VERSION 5.7 ;
  NOWIREEXTENSIONATPIN ON ;
  DIVIDERCHAR "/" ;
  BUSBITCHARS "[]" ;
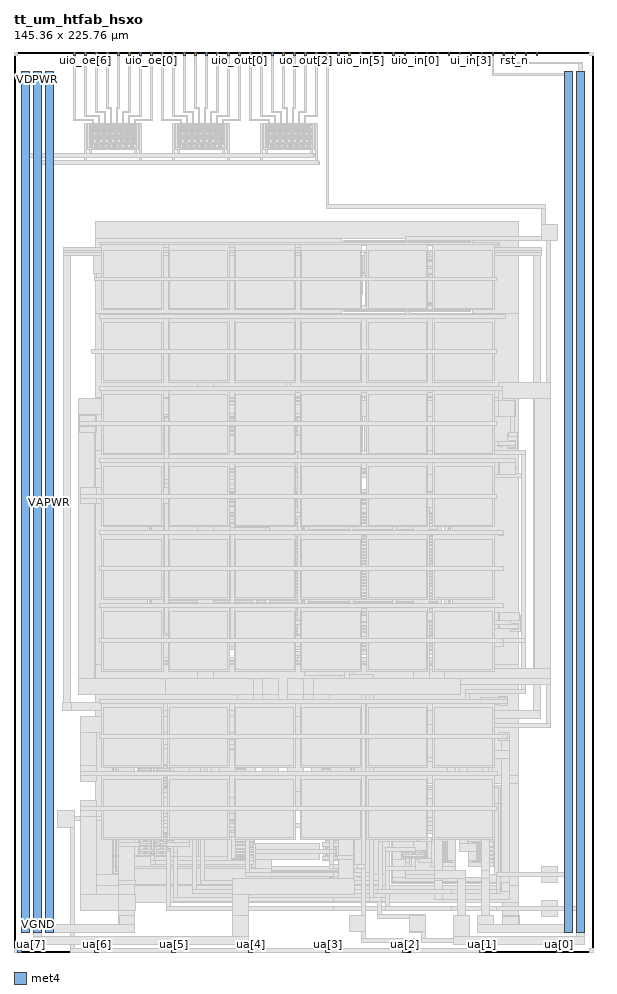
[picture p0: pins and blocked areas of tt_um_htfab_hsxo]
MACRO tt_um_htfab_hsxo
  CLASS BLOCK ;
  FOREIGN tt_um_htfab_hsxo ;
  ORIGIN 0.000 0.000 ;
  SIZE 145.360 BY 225.760 ;
  PIN clk
    DIRECTION INPUT ;
    USE SIGNAL ;
    PORT
      LAYER met4 ;
        RECT 128.190 224.760 128.490 225.760 ;
    END
  END clk
  PIN ena
    DIRECTION INPUT ;
    USE SIGNAL ;
    PORT
      LAYER met4 ;
        RECT 130.950 224.760 131.250 225.760 ;
    END
  END ena
  PIN rst_n
    DIRECTION INPUT ;
    USE SIGNAL ;
    PORT
      LAYER met4 ;
        RECT 125.430 224.760 125.730 225.760 ;
    END
  END rst_n
  PIN ua[0]
    DIRECTION INOUT ;
    USE SIGNAL ;
    ANTENNADIFFAREA 157.759995 ;
    PORT
      LAYER met4 ;
        RECT 136.170 0.000 137.070 1.000 ;
    END
  END ua[0]
  PIN ua[1]
    DIRECTION INOUT ;
    USE SIGNAL ;
    ANTENNAGATEAREA 18.202499 ;
    ANTENNADIFFAREA 0.405000 ;
    PORT
      LAYER met4 ;
        RECT 116.850 0.000 117.750 1.000 ;
    END
  END ua[1]
  PIN ua[2]
    DIRECTION INOUT ;
    USE SIGNAL ;
    ANTENNADIFFAREA 5.800000 ;
    PORT
      LAYER met4 ;
        RECT 97.530 0.000 98.430 1.000 ;
    END
  END ua[2]
  PIN ua[3]
    DIRECTION INOUT ;
    USE SIGNAL ;
    PORT
      LAYER met4 ;
        RECT 78.210 0.000 79.110 1.000 ;
    END
  END ua[3]
  PIN ua[4]
    DIRECTION INOUT ;
    USE SIGNAL ;
    PORT
      LAYER met4 ;
        RECT 58.890 0.000 59.790 1.000 ;
    END
  END ua[4]
  PIN ua[5]
    DIRECTION INOUT ;
    USE SIGNAL ;
    PORT
      LAYER met4 ;
        RECT 39.570 0.000 40.470 1.000 ;
    END
  END ua[5]
  PIN ua[6]
    DIRECTION INOUT ;
    USE SIGNAL ;
    PORT
      LAYER met4 ;
        RECT 20.250 0.000 21.150 1.000 ;
    END
  END ua[6]
  PIN ua[7]
    DIRECTION INOUT ;
    USE SIGNAL ;
    PORT
      LAYER met4 ;
        RECT 0.930 0.000 1.830 1.000 ;
    END
  END ua[7]
  PIN ui_in[0]
    DIRECTION INPUT ;
    USE SIGNAL ;
    ANTENNAGATEAREA 0.800000 ;
    PORT
      LAYER met4 ;
        RECT 122.670 224.760 122.970 225.760 ;
    END
  END ui_in[0]
  PIN ui_in[1]
    DIRECTION INPUT ;
    USE SIGNAL ;
    ANTENNAGATEAREA 10.400000 ;
    PORT
      LAYER met4 ;
        RECT 119.910 224.760 120.210 225.760 ;
    END
  END ui_in[1]
  PIN ui_in[2]
    DIRECTION INPUT ;
    USE SIGNAL ;
    PORT
      LAYER met4 ;
        RECT 117.150 224.760 117.450 225.760 ;
    END
  END ui_in[2]
  PIN ui_in[3]
    DIRECTION INPUT ;
    USE SIGNAL ;
    PORT
      LAYER met4 ;
        RECT 114.390 224.760 114.690 225.760 ;
    END
  END ui_in[3]
  PIN ui_in[4]
    DIRECTION INPUT ;
    USE SIGNAL ;
    PORT
      LAYER met4 ;
        RECT 111.630 224.760 111.930 225.760 ;
    END
  END ui_in[4]
  PIN ui_in[5]
    DIRECTION INPUT ;
    USE SIGNAL ;
    PORT
      LAYER met4 ;
        RECT 108.870 224.760 109.170 225.760 ;
    END
  END ui_in[5]
  PIN ui_in[6]
    DIRECTION INPUT ;
    USE SIGNAL ;
    PORT
      LAYER met4 ;
        RECT 106.110 224.760 106.410 225.760 ;
    END
  END ui_in[6]
  PIN ui_in[7]
    DIRECTION INPUT ;
    USE SIGNAL ;
    PORT
      LAYER met4 ;
        RECT 103.350 224.760 103.650 225.760 ;
    END
  END ui_in[7]
  PIN uio_in[0]
    DIRECTION INPUT ;
    USE SIGNAL ;
    PORT
      LAYER met4 ;
        RECT 100.590 224.760 100.890 225.760 ;
    END
  END uio_in[0]
  PIN uio_in[1]
    DIRECTION INPUT ;
    USE SIGNAL ;
    PORT
      LAYER met4 ;
        RECT 97.830 224.760 98.130 225.760 ;
    END
  END uio_in[1]
  PIN uio_in[2]
    DIRECTION INPUT ;
    USE SIGNAL ;
    PORT
      LAYER met4 ;
        RECT 95.070 224.760 95.370 225.760 ;
    END
  END uio_in[2]
  PIN uio_in[3]
    DIRECTION INPUT ;
    USE SIGNAL ;
    PORT
      LAYER met4 ;
        RECT 92.310 224.760 92.610 225.760 ;
    END
  END uio_in[3]
  PIN uio_in[4]
    DIRECTION INPUT ;
    USE SIGNAL ;
    PORT
      LAYER met4 ;
        RECT 89.550 224.760 89.850 225.760 ;
    END
  END uio_in[4]
  PIN uio_in[5]
    DIRECTION INPUT ;
    USE SIGNAL ;
    PORT
      LAYER met4 ;
        RECT 86.790 224.760 87.090 225.760 ;
    END
  END uio_in[5]
  PIN uio_in[6]
    DIRECTION INPUT ;
    USE SIGNAL ;
    PORT
      LAYER met4 ;
        RECT 84.030 224.760 84.330 225.760 ;
    END
  END uio_in[6]
  PIN uio_in[7]
    DIRECTION INPUT ;
    USE SIGNAL ;
    PORT
      LAYER met4 ;
        RECT 81.270 224.760 81.570 225.760 ;
    END
  END uio_in[7]
  PIN uio_oe[0]
    DIRECTION OUTPUT ;
    USE SIGNAL ;
    ANTENNADIFFAREA 0.227500 ;
    PORT
      LAYER met4 ;
        RECT 34.350 224.760 34.650 225.760 ;
    END
  END uio_oe[0]
  PIN uio_oe[1]
    DIRECTION OUTPUT ;
    USE SIGNAL ;
    ANTENNADIFFAREA 0.227500 ;
    PORT
      LAYER met4 ;
        RECT 31.590 224.760 31.890 225.760 ;
    END
  END uio_oe[1]
  PIN uio_oe[2]
    DIRECTION OUTPUT ;
    USE SIGNAL ;
    ANTENNADIFFAREA 0.227500 ;
    PORT
      LAYER met4 ;
        RECT 28.830 224.760 29.130 225.760 ;
    END
  END uio_oe[2]
  PIN uio_oe[3]
    DIRECTION OUTPUT ;
    USE SIGNAL ;
    ANTENNADIFFAREA 0.227500 ;
    PORT
      LAYER met4 ;
        RECT 26.070 224.760 26.370 225.760 ;
    END
  END uio_oe[3]
  PIN uio_oe[4]
    DIRECTION OUTPUT ;
    USE SIGNAL ;
    ANTENNADIFFAREA 0.227500 ;
    PORT
      LAYER met4 ;
        RECT 23.310 224.760 23.610 225.760 ;
    END
  END uio_oe[4]
  PIN uio_oe[5]
    DIRECTION OUTPUT ;
    USE SIGNAL ;
    ANTENNADIFFAREA 0.227500 ;
    PORT
      LAYER met4 ;
        RECT 20.550 224.760 20.850 225.760 ;
    END
  END uio_oe[5]
  PIN uio_oe[6]
    DIRECTION OUTPUT ;
    USE SIGNAL ;
    ANTENNADIFFAREA 0.227500 ;
    PORT
      LAYER met4 ;
        RECT 17.790 224.760 18.090 225.760 ;
    END
  END uio_oe[6]
  PIN uio_oe[7]
    DIRECTION OUTPUT ;
    USE SIGNAL ;
    ANTENNADIFFAREA 0.227500 ;
    PORT
      LAYER met4 ;
        RECT 15.030 224.760 15.330 225.760 ;
    END
  END uio_oe[7]
  PIN uio_out[0]
    DIRECTION OUTPUT ;
    USE SIGNAL ;
    ANTENNADIFFAREA 0.227500 ;
    PORT
      LAYER met4 ;
        RECT 56.430 224.760 56.730 225.760 ;
    END
  END uio_out[0]
  PIN uio_out[1]
    DIRECTION OUTPUT ;
    USE SIGNAL ;
    ANTENNADIFFAREA 0.227500 ;
    PORT
      LAYER met4 ;
        RECT 53.670 224.760 53.970 225.760 ;
    END
  END uio_out[1]
  PIN uio_out[2]
    DIRECTION OUTPUT ;
    USE SIGNAL ;
    ANTENNADIFFAREA 0.227500 ;
    PORT
      LAYER met4 ;
        RECT 50.910 224.760 51.210 225.760 ;
    END
  END uio_out[2]
  PIN uio_out[3]
    DIRECTION OUTPUT ;
    USE SIGNAL ;
    ANTENNADIFFAREA 0.227500 ;
    PORT
      LAYER met4 ;
        RECT 48.150 224.760 48.450 225.760 ;
    END
  END uio_out[3]
  PIN uio_out[4]
    DIRECTION OUTPUT ;
    USE SIGNAL ;
    ANTENNADIFFAREA 0.227500 ;
    PORT
      LAYER met4 ;
        RECT 45.390 224.760 45.690 225.760 ;
    END
  END uio_out[4]
  PIN uio_out[5]
    DIRECTION OUTPUT ;
    USE SIGNAL ;
    ANTENNADIFFAREA 0.227500 ;
    PORT
      LAYER met4 ;
        RECT 42.630 224.760 42.930 225.760 ;
    END
  END uio_out[5]
  PIN uio_out[6]
    DIRECTION OUTPUT ;
    USE SIGNAL ;
    ANTENNADIFFAREA 0.227500 ;
    PORT
      LAYER met4 ;
        RECT 39.870 224.760 40.170 225.760 ;
    END
  END uio_out[6]
  PIN uio_out[7]
    DIRECTION OUTPUT ;
    USE SIGNAL ;
    ANTENNADIFFAREA 0.227500 ;
    PORT
      LAYER met4 ;
        RECT 37.110 224.760 37.410 225.760 ;
    END
  END uio_out[7]
  PIN uo_out[0]
    DIRECTION OUTPUT ;
    USE SIGNAL ;
    ANTENNAGATEAREA 0.500000 ;
    ANTENNADIFFAREA 7.020000 ;
    PORT
      LAYER met4 ;
        RECT 78.510 224.760 78.810 225.760 ;
    END
  END uo_out[0]
  PIN uo_out[1]
    DIRECTION OUTPUT ;
    USE SIGNAL ;
    ANTENNADIFFAREA 0.227500 ;
    PORT
      LAYER met4 ;
        RECT 75.750 224.760 76.050 225.760 ;
    END
  END uo_out[1]
  PIN uo_out[2]
    DIRECTION OUTPUT ;
    USE SIGNAL ;
    ANTENNADIFFAREA 0.227500 ;
    PORT
      LAYER met4 ;
        RECT 72.990 224.760 73.290 225.760 ;
    END
  END uo_out[2]
  PIN uo_out[3]
    DIRECTION OUTPUT ;
    USE SIGNAL ;
    ANTENNADIFFAREA 0.227500 ;
    PORT
      LAYER met4 ;
        RECT 70.230 224.760 70.530 225.760 ;
    END
  END uo_out[3]
  PIN uo_out[4]
    DIRECTION OUTPUT ;
    USE SIGNAL ;
    ANTENNADIFFAREA 0.227500 ;
    PORT
      LAYER met4 ;
        RECT 67.470 224.760 67.770 225.760 ;
    END
  END uo_out[4]
  PIN uo_out[5]
    DIRECTION OUTPUT ;
    USE SIGNAL ;
    ANTENNADIFFAREA 0.227500 ;
    PORT
      LAYER met4 ;
        RECT 64.710 224.760 65.010 225.760 ;
    END
  END uo_out[5]
  PIN uo_out[6]
    DIRECTION OUTPUT ;
    USE SIGNAL ;
    ANTENNADIFFAREA 0.227500 ;
    PORT
      LAYER met4 ;
        RECT 61.950 224.760 62.250 225.760 ;
    END
  END uo_out[6]
  PIN uo_out[7]
    DIRECTION OUTPUT ;
    USE SIGNAL ;
    ANTENNADIFFAREA 0.227500 ;
    PORT
      LAYER met4 ;
        RECT 59.190 224.760 59.490 225.760 ;
    END
  END uo_out[7]
  PIN VDPWR
    DIRECTION INOUT ;
    USE POWER ;
    PORT
      LAYER met4 ;
        RECT 2.000 5.000 4.000 220.760 ;
    END
    PORT
      LAYER met4 ;
        RECT 141.000 5.000 143.000 220.760 ;
    END
  END VDPWR
  PIN VGND
    DIRECTION INOUT ;
    USE GROUND ;
    PORT
      LAYER met4 ;
        RECT 5.000 5.000 7.000 220.760 ;
    END
    PORT
      LAYER met4 ;
        RECT 138.000 5.000 140.000 220.760 ;
    END
  END VGND
  PIN VAPWR
    DIRECTION INOUT ;
    USE POWER ;
    PORT
      LAYER met4 ;
        RECT 8.000 5.000 10.000 220.760 ;
    END
  END VAPWR
  OBS
      LAYER nwell ;
        RECT 17.850 204.450 31.330 207.880 ;
        RECT 39.930 204.450 53.410 207.880 ;
        RECT 62.010 204.450 75.490 207.880 ;
      LAYER pwell ;
        RECT 17.850 204.200 18.780 204.205 ;
        RECT 39.930 204.200 40.860 204.205 ;
        RECT 62.010 204.200 62.940 204.205 ;
        RECT 17.850 201.420 31.330 204.200 ;
        RECT 39.930 201.420 53.410 204.200 ;
        RECT 62.010 201.420 75.490 204.200 ;
      LAYER nwell ;
        RECT 82.720 177.125 114.590 178.555 ;
        RECT 82.720 177.110 84.380 177.125 ;
        RECT 82.720 162.160 84.165 177.110 ;
      LAYER pwell ;
        RECT 84.235 170.340 94.215 174.810 ;
      LAYER nwell ;
        RECT 94.295 173.600 98.745 177.125 ;
        RECT 94.285 170.410 98.745 173.600 ;
      LAYER pwell ;
        RECT 98.745 173.560 101.845 175.720 ;
        RECT 103.015 173.560 112.995 174.810 ;
        RECT 98.785 170.460 112.995 173.560 ;
        RECT 103.015 170.340 112.995 170.460 ;
        RECT 84.235 170.310 112.995 170.340 ;
      LAYER nwell ;
        RECT 82.720 162.145 84.380 162.160 ;
        RECT 88.145 162.145 90.645 169.460 ;
      LAYER pwell ;
        RECT 90.975 162.520 112.995 170.310 ;
      LAYER nwell ;
        RECT 113.160 162.145 114.590 177.125 ;
        RECT 82.720 160.715 114.590 162.145 ;
        RECT 33.895 137.230 87.445 138.810 ;
        RECT 33.895 127.740 78.345 137.230 ;
      LAYER pwell ;
        RECT 78.615 129.710 85.195 132.490 ;
      LAYER nwell ;
        RECT 85.865 127.740 87.445 137.230 ;
        RECT 33.895 126.160 87.445 127.740 ;
        RECT 33.895 119.380 109.595 120.960 ;
        RECT 33.895 78.560 72.445 119.380 ;
      LAYER pwell ;
        RECT 96.715 115.960 107.295 118.690 ;
      LAYER nwell ;
        RECT 33.895 73.990 48.295 78.560 ;
      LAYER pwell ;
        RECT 72.715 78.400 107.295 115.960 ;
        RECT 50.085 75.850 107.295 78.400 ;
        RECT 72.715 75.810 107.295 75.850 ;
      LAYER nwell ;
        RECT 108.015 73.990 109.595 119.380 ;
        RECT 33.895 72.410 109.595 73.990 ;
        RECT 25.015 55.180 85.065 56.760 ;
        RECT 25.015 55.160 34.665 55.180 ;
        RECT 82.915 55.160 85.065 55.180 ;
        RECT 25.015 30.810 28.665 55.160 ;
      LAYER pwell ;
        RECT 35.135 51.740 81.585 55.030 ;
      LAYER nwell ;
        RECT 30.885 30.810 34.885 47.230 ;
      LAYER pwell ;
        RECT 35.135 47.030 46.335 51.740 ;
      LAYER nwell ;
        RECT 53.285 51.680 60.335 51.690 ;
      LAYER pwell ;
        RECT 35.155 44.280 46.335 47.030 ;
        RECT 35.135 44.030 46.335 44.280 ;
        RECT 35.155 41.230 46.335 44.030 ;
        RECT 38.735 41.180 46.335 41.230 ;
      LAYER nwell ;
        RECT 25.015 24.130 34.885 30.810 ;
      LAYER pwell ;
        RECT 35.135 29.980 46.335 41.180 ;
        RECT 38.735 29.960 46.335 29.980 ;
      LAYER nwell ;
        RECT 25.015 23.880 34.905 24.130 ;
      LAYER pwell ;
        RECT 34.905 23.880 46.335 29.960 ;
      LAYER nwell ;
        RECT 46.335 23.880 60.335 51.680 ;
      LAYER pwell ;
        RECT 60.335 48.580 74.985 51.740 ;
        RECT 75.005 43.430 81.585 51.740 ;
        RECT 75.035 40.740 81.535 43.430 ;
        RECT 75.005 32.430 81.585 40.740 ;
        RECT 76.135 31.680 81.285 32.430 ;
        RECT 78.135 27.360 81.285 31.680 ;
      LAYER nwell ;
        RECT 25.015 21.340 60.335 23.880 ;
      LAYER pwell ;
        RECT 77.605 26.460 81.835 27.360 ;
        RECT 77.605 24.030 78.505 26.460 ;
      LAYER nwell ;
        RECT 78.505 24.030 80.935 26.460 ;
      LAYER pwell ;
        RECT 80.935 24.030 81.835 26.460 ;
        RECT 77.605 23.130 81.835 24.030 ;
      LAYER nwell ;
        RECT 83.415 21.340 85.065 55.160 ;
        RECT 25.015 19.760 85.065 21.340 ;
        RECT 94.615 37.230 121.915 41.660 ;
        RECT 94.615 35.570 97.375 37.230 ;
        RECT 94.615 23.190 100.315 35.570 ;
      LAYER pwell ;
        RECT 100.315 35.560 103.415 35.570 ;
        RECT 100.315 35.540 106.265 35.560 ;
        RECT 111.615 35.540 120.165 36.640 ;
        RECT 100.315 31.110 120.165 35.540 ;
        RECT 100.315 25.340 103.415 31.110 ;
        RECT 100.315 23.190 103.415 25.300 ;
      LAYER nwell ;
        RECT 104.575 23.190 110.765 27.850 ;
        RECT 94.615 18.590 110.765 23.190 ;
      LAYER pwell ;
        RECT 114.065 22.350 120.165 31.110 ;
      LAYER nwell ;
        RECT 120.485 18.590 121.915 37.230 ;
        RECT 94.615 17.160 121.915 18.590 ;
      LAYER li1 ;
        RECT 18.240 207.320 30.940 207.490 ;
        RECT 18.240 205.100 18.410 207.320 ;
        RECT 19.090 206.900 19.590 207.070 ;
        RECT 20.590 206.900 21.090 207.070 ;
        RECT 22.090 206.900 22.590 207.070 ;
        RECT 23.590 206.900 24.090 207.070 ;
        RECT 25.090 206.900 25.590 207.070 ;
        RECT 26.590 206.900 27.090 207.070 ;
        RECT 28.090 206.900 28.590 207.070 ;
        RECT 29.590 206.900 30.090 207.070 ;
        RECT 18.800 205.645 18.970 206.685 ;
        RECT 19.710 205.645 19.880 206.685 ;
        RECT 20.300 205.645 20.470 206.685 ;
        RECT 21.210 205.645 21.380 206.685 ;
        RECT 21.800 205.645 21.970 206.685 ;
        RECT 22.710 205.645 22.880 206.685 ;
        RECT 23.300 205.645 23.470 206.685 ;
        RECT 24.210 205.645 24.380 206.685 ;
        RECT 24.800 205.645 24.970 206.685 ;
        RECT 25.710 205.645 25.880 206.685 ;
        RECT 26.300 205.645 26.470 206.685 ;
        RECT 27.210 205.645 27.380 206.685 ;
        RECT 27.800 205.645 27.970 206.685 ;
        RECT 28.710 205.645 28.880 206.685 ;
        RECT 29.300 205.645 29.470 206.685 ;
        RECT 30.210 205.645 30.380 206.685 ;
        RECT 19.090 205.260 19.590 205.430 ;
        RECT 20.590 205.260 21.090 205.430 ;
        RECT 22.090 205.260 22.590 205.430 ;
        RECT 23.590 205.260 24.090 205.430 ;
        RECT 25.090 205.260 25.590 205.430 ;
        RECT 26.590 205.260 27.090 205.430 ;
        RECT 28.090 205.260 28.590 205.430 ;
        RECT 29.590 205.260 30.090 205.430 ;
        RECT 30.770 205.100 30.940 207.320 ;
        RECT 40.320 207.320 53.020 207.490 ;
        RECT 40.320 205.100 40.490 207.320 ;
        RECT 41.170 206.900 41.670 207.070 ;
        RECT 42.670 206.900 43.170 207.070 ;
        RECT 44.170 206.900 44.670 207.070 ;
        RECT 45.670 206.900 46.170 207.070 ;
        RECT 47.170 206.900 47.670 207.070 ;
        RECT 48.670 206.900 49.170 207.070 ;
        RECT 50.170 206.900 50.670 207.070 ;
        RECT 51.670 206.900 52.170 207.070 ;
        RECT 40.880 205.645 41.050 206.685 ;
        RECT 41.790 205.645 41.960 206.685 ;
        RECT 42.380 205.645 42.550 206.685 ;
        RECT 43.290 205.645 43.460 206.685 ;
        RECT 43.880 205.645 44.050 206.685 ;
        RECT 44.790 205.645 44.960 206.685 ;
        RECT 45.380 205.645 45.550 206.685 ;
        RECT 46.290 205.645 46.460 206.685 ;
        RECT 46.880 205.645 47.050 206.685 ;
        RECT 47.790 205.645 47.960 206.685 ;
        RECT 48.380 205.645 48.550 206.685 ;
        RECT 49.290 205.645 49.460 206.685 ;
        RECT 49.880 205.645 50.050 206.685 ;
        RECT 50.790 205.645 50.960 206.685 ;
        RECT 51.380 205.645 51.550 206.685 ;
        RECT 52.290 205.645 52.460 206.685 ;
        RECT 41.170 205.260 41.670 205.430 ;
        RECT 42.670 205.260 43.170 205.430 ;
        RECT 44.170 205.260 44.670 205.430 ;
        RECT 45.670 205.260 46.170 205.430 ;
        RECT 47.170 205.260 47.670 205.430 ;
        RECT 48.670 205.260 49.170 205.430 ;
        RECT 50.170 205.260 50.670 205.430 ;
        RECT 51.670 205.260 52.170 205.430 ;
        RECT 52.850 205.100 53.020 207.320 ;
        RECT 62.400 207.320 75.100 207.490 ;
        RECT 62.400 205.100 62.570 207.320 ;
        RECT 63.250 206.900 63.750 207.070 ;
        RECT 64.750 206.900 65.250 207.070 ;
        RECT 66.250 206.900 66.750 207.070 ;
        RECT 67.750 206.900 68.250 207.070 ;
        RECT 69.250 206.900 69.750 207.070 ;
        RECT 70.750 206.900 71.250 207.070 ;
        RECT 72.250 206.900 72.750 207.070 ;
        RECT 73.750 206.900 74.250 207.070 ;
        RECT 62.960 205.645 63.130 206.685 ;
        RECT 63.870 205.645 64.040 206.685 ;
        RECT 64.460 205.645 64.630 206.685 ;
        RECT 65.370 205.645 65.540 206.685 ;
        RECT 65.960 205.645 66.130 206.685 ;
        RECT 66.870 205.645 67.040 206.685 ;
        RECT 67.460 205.645 67.630 206.685 ;
        RECT 68.370 205.645 68.540 206.685 ;
        RECT 68.960 205.645 69.130 206.685 ;
        RECT 69.870 205.645 70.040 206.685 ;
        RECT 70.460 205.645 70.630 206.685 ;
        RECT 71.370 205.645 71.540 206.685 ;
        RECT 71.960 205.645 72.130 206.685 ;
        RECT 72.870 205.645 73.040 206.685 ;
        RECT 73.460 205.645 73.630 206.685 ;
        RECT 74.370 205.645 74.540 206.685 ;
        RECT 63.250 205.260 63.750 205.430 ;
        RECT 64.750 205.260 65.250 205.430 ;
        RECT 66.250 205.260 66.750 205.430 ;
        RECT 67.750 205.260 68.250 205.430 ;
        RECT 69.250 205.260 69.750 205.430 ;
        RECT 70.750 205.260 71.250 205.430 ;
        RECT 72.250 205.260 72.750 205.430 ;
        RECT 73.750 205.260 74.250 205.430 ;
        RECT 74.930 205.100 75.100 207.320 ;
        RECT 18.240 205.010 18.850 205.100 ;
        RECT 30.770 205.010 31.330 205.100 ;
        RECT 18.240 204.840 31.330 205.010 ;
        RECT 40.320 205.010 40.930 205.100 ;
        RECT 52.850 205.010 53.410 205.100 ;
        RECT 40.320 204.840 53.410 205.010 ;
        RECT 62.400 205.010 63.010 205.100 ;
        RECT 74.930 205.010 75.490 205.100 ;
        RECT 62.400 204.840 75.490 205.010 ;
        RECT 18.350 204.750 18.850 204.840 ;
        RECT 30.770 204.750 31.330 204.840 ;
        RECT 40.430 204.750 40.930 204.840 ;
        RECT 52.850 204.750 53.410 204.840 ;
        RECT 62.510 204.750 63.010 204.840 ;
        RECT 74.930 204.750 75.490 204.840 ;
        RECT 18.140 203.960 18.850 204.050 ;
        RECT 30.830 203.960 31.330 204.050 ;
        RECT 18.140 203.790 31.330 203.960 ;
        RECT 18.140 203.700 18.850 203.790 ;
        RECT 30.830 203.700 31.330 203.790 ;
        RECT 40.220 203.960 40.930 204.050 ;
        RECT 52.910 203.960 53.410 204.050 ;
        RECT 40.220 203.790 53.410 203.960 ;
        RECT 40.220 203.700 40.930 203.790 ;
        RECT 52.910 203.700 53.410 203.790 ;
        RECT 62.300 203.960 63.010 204.050 ;
        RECT 74.990 203.960 75.490 204.050 ;
        RECT 62.300 203.790 75.490 203.960 ;
        RECT 62.300 203.700 63.010 203.790 ;
        RECT 74.990 203.700 75.490 203.790 ;
        RECT 18.140 201.830 18.310 203.700 ;
        RECT 19.090 203.325 19.590 203.495 ;
        RECT 20.590 203.325 21.090 203.495 ;
        RECT 22.090 203.325 22.590 203.495 ;
        RECT 23.590 203.325 24.090 203.495 ;
        RECT 25.090 203.325 25.590 203.495 ;
        RECT 26.590 203.325 27.090 203.495 ;
        RECT 28.090 203.325 28.590 203.495 ;
        RECT 29.590 203.325 30.090 203.495 ;
        RECT 18.800 202.465 18.970 203.155 ;
        RECT 19.710 202.465 19.880 203.155 ;
        RECT 20.300 202.465 20.470 203.155 ;
        RECT 21.210 202.465 21.380 203.155 ;
        RECT 21.800 202.465 21.970 203.155 ;
        RECT 22.710 202.465 22.880 203.155 ;
        RECT 23.300 202.465 23.470 203.155 ;
        RECT 24.210 202.465 24.380 203.155 ;
        RECT 24.800 202.465 24.970 203.155 ;
        RECT 25.710 202.465 25.880 203.155 ;
        RECT 26.300 202.465 26.470 203.155 ;
        RECT 27.210 202.465 27.380 203.155 ;
        RECT 27.800 202.465 27.970 203.155 ;
        RECT 28.710 202.465 28.880 203.155 ;
        RECT 29.300 202.465 29.470 203.155 ;
        RECT 30.210 202.465 30.380 203.155 ;
        RECT 19.090 202.125 19.590 202.295 ;
        RECT 20.590 202.125 21.090 202.295 ;
        RECT 22.090 202.125 22.590 202.295 ;
        RECT 23.590 202.125 24.090 202.295 ;
        RECT 25.090 202.125 25.590 202.295 ;
        RECT 26.590 202.125 27.090 202.295 ;
        RECT 28.090 202.125 28.590 202.295 ;
        RECT 29.590 202.125 30.090 202.295 ;
        RECT 30.920 201.830 31.090 203.700 ;
        RECT 18.140 201.660 31.090 201.830 ;
        RECT 40.220 201.830 40.390 203.700 ;
        RECT 41.170 203.325 41.670 203.495 ;
        RECT 42.670 203.325 43.170 203.495 ;
        RECT 44.170 203.325 44.670 203.495 ;
        RECT 45.670 203.325 46.170 203.495 ;
        RECT 47.170 203.325 47.670 203.495 ;
        RECT 48.670 203.325 49.170 203.495 ;
        RECT 50.170 203.325 50.670 203.495 ;
        RECT 51.670 203.325 52.170 203.495 ;
        RECT 40.880 202.465 41.050 203.155 ;
        RECT 41.790 202.465 41.960 203.155 ;
        RECT 42.380 202.465 42.550 203.155 ;
        RECT 43.290 202.465 43.460 203.155 ;
        RECT 43.880 202.465 44.050 203.155 ;
        RECT 44.790 202.465 44.960 203.155 ;
        RECT 45.380 202.465 45.550 203.155 ;
        RECT 46.290 202.465 46.460 203.155 ;
        RECT 46.880 202.465 47.050 203.155 ;
        RECT 47.790 202.465 47.960 203.155 ;
        RECT 48.380 202.465 48.550 203.155 ;
        RECT 49.290 202.465 49.460 203.155 ;
        RECT 49.880 202.465 50.050 203.155 ;
        RECT 50.790 202.465 50.960 203.155 ;
        RECT 51.380 202.465 51.550 203.155 ;
        RECT 52.290 202.465 52.460 203.155 ;
        RECT 41.170 202.125 41.670 202.295 ;
        RECT 42.670 202.125 43.170 202.295 ;
        RECT 44.170 202.125 44.670 202.295 ;
        RECT 45.670 202.125 46.170 202.295 ;
        RECT 47.170 202.125 47.670 202.295 ;
        RECT 48.670 202.125 49.170 202.295 ;
        RECT 50.170 202.125 50.670 202.295 ;
        RECT 51.670 202.125 52.170 202.295 ;
        RECT 53.000 201.830 53.170 203.700 ;
        RECT 40.220 201.660 53.170 201.830 ;
        RECT 62.300 201.830 62.470 203.700 ;
        RECT 63.250 203.325 63.750 203.495 ;
        RECT 64.750 203.325 65.250 203.495 ;
        RECT 66.250 203.325 66.750 203.495 ;
        RECT 67.750 203.325 68.250 203.495 ;
        RECT 69.250 203.325 69.750 203.495 ;
        RECT 70.750 203.325 71.250 203.495 ;
        RECT 72.250 203.325 72.750 203.495 ;
        RECT 73.750 203.325 74.250 203.495 ;
        RECT 62.960 202.465 63.130 203.155 ;
        RECT 63.870 202.465 64.040 203.155 ;
        RECT 64.460 202.465 64.630 203.155 ;
        RECT 65.370 202.465 65.540 203.155 ;
        RECT 65.960 202.465 66.130 203.155 ;
        RECT 66.870 202.465 67.040 203.155 ;
        RECT 67.460 202.465 67.630 203.155 ;
        RECT 68.370 202.465 68.540 203.155 ;
        RECT 68.960 202.465 69.130 203.155 ;
        RECT 69.870 202.465 70.040 203.155 ;
        RECT 70.460 202.465 70.630 203.155 ;
        RECT 71.370 202.465 71.540 203.155 ;
        RECT 71.960 202.465 72.130 203.155 ;
        RECT 72.870 202.465 73.040 203.155 ;
        RECT 73.460 202.465 73.630 203.155 ;
        RECT 74.370 202.465 74.540 203.155 ;
        RECT 63.250 202.125 63.750 202.295 ;
        RECT 64.750 202.125 65.250 202.295 ;
        RECT 66.250 202.125 66.750 202.295 ;
        RECT 67.750 202.125 68.250 202.295 ;
        RECT 69.250 202.125 69.750 202.295 ;
        RECT 70.750 202.125 71.250 202.295 ;
        RECT 72.250 202.125 72.750 202.295 ;
        RECT 73.750 202.125 74.250 202.295 ;
        RECT 75.080 201.830 75.250 203.700 ;
        RECT 62.300 201.660 75.250 201.830 ;
        RECT 78.035 183.260 83.335 183.270 ;
        RECT 114.005 183.260 119.305 183.270 ;
        RECT 20.395 179.100 126.645 183.260 ;
        RECT 20.395 160.170 82.205 179.100 ;
        RECT 83.005 178.100 114.305 178.270 ;
        RECT 83.005 161.170 83.175 178.100 ;
        RECT 98.295 175.690 98.665 175.695 ;
        RECT 95.665 175.660 98.665 175.690 ;
        RECT 95.635 175.320 98.665 175.660 ;
        RECT 84.345 174.700 94.105 174.730 ;
        RECT 84.315 174.360 94.135 174.700 ;
        RECT 84.315 170.760 84.685 174.360 ;
        RECT 85.065 173.630 87.225 173.980 ;
        RECT 91.225 173.630 93.385 173.980 ;
        RECT 85.065 172.800 87.225 173.150 ;
        RECT 91.225 172.800 93.385 173.150 ;
        RECT 85.065 171.970 87.225 172.320 ;
        RECT 91.225 171.970 93.385 172.320 ;
        RECT 85.065 171.140 87.225 171.490 ;
        RECT 91.225 171.140 93.385 171.490 ;
        RECT 93.765 170.760 94.135 174.360 ;
        RECT 95.635 174.310 96.005 175.320 ;
        RECT 96.630 174.850 97.670 175.020 ;
        RECT 96.245 174.475 96.415 174.805 ;
        RECT 97.885 174.475 98.055 174.805 ;
        RECT 94.795 173.960 96.005 174.310 ;
        RECT 96.630 174.260 97.670 174.430 ;
        RECT 98.295 173.960 98.665 175.320 ;
        RECT 94.795 173.520 98.665 173.960 ;
        RECT 94.395 173.490 98.665 173.520 ;
        RECT 84.315 170.420 94.135 170.760 ;
        RECT 94.365 173.150 98.665 173.490 ;
        RECT 94.365 170.860 94.735 173.150 ;
        RECT 95.250 172.740 95.580 172.910 ;
        RECT 95.035 171.485 95.205 172.525 ;
        RECT 95.625 171.485 95.795 172.525 ;
        RECT 95.250 171.100 95.580 171.270 ;
        RECT 96.095 170.860 96.935 173.150 ;
        RECT 97.450 172.740 97.780 172.910 ;
        RECT 97.235 171.485 97.405 172.525 ;
        RECT 97.825 171.485 97.995 172.525 ;
        RECT 97.450 171.100 97.780 171.270 ;
        RECT 98.295 170.860 98.665 173.150 ;
        RECT 94.365 170.520 98.665 170.860 ;
        RECT 98.865 175.640 99.235 175.645 ;
        RECT 98.865 175.610 101.735 175.640 ;
        RECT 98.865 175.270 101.765 175.610 ;
        RECT 98.865 174.010 99.235 175.270 ;
        RECT 99.435 174.475 99.605 174.805 ;
        RECT 99.775 174.800 100.815 174.970 ;
        RECT 99.775 174.310 100.815 174.480 ;
        RECT 100.985 174.475 101.155 174.805 ;
        RECT 101.395 174.010 101.765 175.270 ;
        RECT 103.125 174.700 112.885 174.730 ;
        RECT 98.865 173.480 101.765 174.010 ;
        RECT 103.095 174.360 112.915 174.700 ;
        RECT 103.095 173.480 103.465 174.360 ;
        RECT 103.845 173.630 106.005 173.980 ;
        RECT 110.005 173.630 112.165 173.980 ;
        RECT 98.865 173.110 103.465 173.480 ;
        RECT 98.865 170.910 99.235 173.110 ;
        RECT 99.700 172.700 100.030 172.870 ;
        RECT 99.535 171.490 99.705 172.530 ;
        RECT 100.025 171.490 100.195 172.530 ;
        RECT 99.700 171.150 100.030 171.320 ;
        RECT 100.495 170.910 101.335 173.110 ;
        RECT 101.800 172.700 102.130 172.870 ;
        RECT 101.635 171.490 101.805 172.530 ;
        RECT 102.125 171.490 102.295 172.530 ;
        RECT 101.800 171.150 102.130 171.320 ;
        RECT 102.595 170.910 103.465 173.110 ;
        RECT 103.845 172.800 106.005 173.150 ;
        RECT 110.005 172.800 112.165 173.150 ;
        RECT 103.845 171.970 106.005 172.320 ;
        RECT 110.005 171.970 112.165 172.320 ;
        RECT 103.845 171.140 106.005 171.490 ;
        RECT 110.005 171.140 112.165 171.490 ;
        RECT 98.865 170.760 103.465 170.910 ;
        RECT 112.545 170.760 112.915 174.360 ;
        RECT 98.865 170.570 112.915 170.760 ;
        RECT 98.895 170.540 112.915 170.570 ;
        RECT 94.395 170.490 98.635 170.520 ;
        RECT 84.345 170.390 94.135 170.420 ;
        RECT 86.445 164.880 87.445 170.390 ;
        RECT 91.055 170.300 94.135 170.390 ;
        RECT 102.810 170.300 112.915 170.540 ;
        RECT 91.055 169.930 112.915 170.300 ;
        RECT 88.945 164.880 89.945 169.040 ;
        RECT 91.055 162.970 91.425 169.930 ;
        RECT 91.805 169.160 93.965 169.510 ;
        RECT 110.005 169.160 112.165 169.510 ;
        RECT 91.805 168.330 93.965 168.680 ;
        RECT 110.005 168.330 112.165 168.680 ;
        RECT 91.805 167.500 93.965 167.850 ;
        RECT 110.005 167.500 112.165 167.850 ;
        RECT 91.805 166.670 93.965 167.020 ;
        RECT 110.005 166.670 112.165 167.020 ;
        RECT 91.805 165.840 93.965 166.190 ;
        RECT 110.005 165.840 112.165 166.190 ;
        RECT 91.805 165.010 93.965 165.360 ;
        RECT 110.005 165.010 112.165 165.360 ;
        RECT 91.805 164.180 93.965 164.530 ;
        RECT 110.005 164.180 112.165 164.530 ;
        RECT 91.805 163.350 93.965 163.700 ;
        RECT 110.005 163.350 112.165 163.700 ;
        RECT 112.545 162.970 112.915 169.930 ;
        RECT 91.055 162.630 112.915 162.970 ;
        RECT 91.085 162.600 112.885 162.630 ;
        RECT 114.135 161.170 114.305 178.100 ;
        RECT 83.005 161.000 114.305 161.170 ;
        RECT 115.135 160.170 126.645 179.100 ;
        RECT 20.395 139.205 126.645 160.170 ;
        RECT 20.395 125.765 33.500 139.205 ;
        RECT 34.330 138.205 87.010 138.375 ;
        RECT 34.330 126.765 34.500 138.205 ;
        RECT 37.565 134.350 72.355 135.120 ;
        RECT 37.565 130.620 38.335 134.350 ;
        RECT 38.940 133.980 70.980 134.150 ;
        RECT 38.555 133.420 38.725 133.920 ;
        RECT 71.195 133.420 71.365 133.920 ;
        RECT 38.940 133.190 70.980 133.360 ;
        RECT 71.585 133.310 72.355 134.350 ;
        RECT 79.715 134.310 84.875 136.310 ;
        RECT 38.555 132.630 38.725 133.130 ;
        RECT 71.195 132.630 71.365 133.130 ;
        RECT 38.940 132.400 70.980 132.570 ;
        RECT 38.555 131.840 38.725 132.340 ;
        RECT 71.195 131.840 71.365 132.340 ;
        RECT 38.940 131.610 70.980 131.780 ;
        RECT 38.555 131.050 38.725 131.550 ;
        RECT 71.195 131.050 71.365 131.550 ;
        RECT 71.585 131.310 77.975 133.310 ;
        RECT 79.795 132.550 84.795 134.310 ;
        RECT 78.555 131.780 85.255 132.550 ;
        RECT 38.940 130.820 70.980 130.990 ;
        RECT 71.585 130.620 72.355 131.310 ;
        RECT 37.565 129.850 72.355 130.620 ;
        RECT 78.555 130.420 79.325 131.780 ;
        RECT 79.885 131.410 83.925 131.580 ;
        RECT 79.545 130.850 79.715 131.350 ;
        RECT 84.095 130.850 84.265 131.350 ;
        RECT 79.885 130.620 83.925 130.790 ;
        RECT 84.485 130.420 85.255 131.780 ;
        RECT 78.555 129.650 85.255 130.420 ;
        RECT 86.840 126.765 87.010 138.205 ;
        RECT 34.330 126.595 87.010 126.765 ;
        RECT 87.840 125.765 126.645 139.205 ;
        RECT 20.395 121.355 126.645 125.765 ;
        RECT 20.395 72.015 33.500 121.355 ;
        RECT 34.330 120.355 109.160 120.525 ;
        RECT 34.330 73.015 34.500 120.355 ;
        RECT 96.855 118.550 107.155 118.750 ;
        RECT 37.565 115.450 72.355 116.220 ;
        RECT 90.665 116.210 95.825 118.210 ;
        RECT 96.655 117.980 107.355 118.550 ;
        RECT 96.655 116.620 97.425 117.980 ;
        RECT 97.985 117.610 106.025 117.780 ;
        RECT 97.645 117.050 97.815 117.550 ;
        RECT 106.195 117.050 106.365 117.550 ;
        RECT 97.985 116.820 106.025 116.990 ;
        RECT 106.585 116.620 107.355 117.980 ;
        RECT 90.745 116.020 95.745 116.210 ;
        RECT 96.655 116.020 107.355 116.620 ;
        RECT 37.565 111.720 38.335 115.450 ;
        RECT 38.940 115.080 70.980 115.250 ;
        RECT 38.555 114.520 38.725 115.020 ;
        RECT 71.195 114.520 71.365 115.020 ;
        RECT 38.940 114.290 70.980 114.460 ;
        RECT 38.555 113.730 38.725 114.230 ;
        RECT 71.195 113.730 71.365 114.230 ;
        RECT 38.940 113.500 70.980 113.670 ;
        RECT 38.555 112.940 38.725 113.440 ;
        RECT 71.195 112.940 71.365 113.440 ;
        RECT 38.940 112.710 70.980 112.880 ;
        RECT 38.555 112.150 38.725 112.650 ;
        RECT 71.195 112.150 71.365 112.650 ;
        RECT 38.940 111.920 70.980 112.090 ;
        RECT 71.585 111.720 72.355 115.450 ;
        RECT 37.565 110.350 72.355 111.720 ;
        RECT 37.565 106.620 38.335 110.350 ;
        RECT 38.940 109.980 70.980 110.150 ;
        RECT 38.555 109.420 38.725 109.920 ;
        RECT 71.195 109.420 71.365 109.920 ;
        RECT 38.940 109.190 70.980 109.360 ;
        RECT 38.555 108.630 38.725 109.130 ;
        RECT 71.195 108.630 71.365 109.130 ;
        RECT 38.940 108.400 70.980 108.570 ;
        RECT 38.555 107.840 38.725 108.340 ;
        RECT 71.195 107.840 71.365 108.340 ;
        RECT 38.940 107.610 70.980 107.780 ;
        RECT 38.555 107.050 38.725 107.550 ;
        RECT 71.195 107.050 71.365 107.550 ;
        RECT 38.940 106.820 70.980 106.990 ;
        RECT 71.585 106.620 72.355 110.350 ;
        RECT 37.565 105.270 72.355 106.620 ;
        RECT 37.565 79.420 38.335 105.270 ;
        RECT 38.940 104.900 70.980 105.070 ;
        RECT 38.555 104.340 38.725 104.840 ;
        RECT 71.195 104.340 71.365 104.840 ;
        RECT 38.940 104.110 70.980 104.280 ;
        RECT 38.555 103.550 38.725 104.050 ;
        RECT 71.195 103.550 71.365 104.050 ;
        RECT 38.940 103.320 70.980 103.490 ;
        RECT 38.555 102.760 38.725 103.260 ;
        RECT 71.195 102.760 71.365 103.260 ;
        RECT 38.940 102.530 70.980 102.700 ;
        RECT 38.555 101.970 38.725 102.470 ;
        RECT 71.195 101.970 71.365 102.470 ;
        RECT 38.940 101.740 70.980 101.910 ;
        RECT 38.555 101.180 38.725 101.680 ;
        RECT 71.195 101.180 71.365 101.680 ;
        RECT 38.940 100.950 70.980 101.120 ;
        RECT 38.555 100.390 38.725 100.890 ;
        RECT 71.195 100.390 71.365 100.890 ;
        RECT 38.940 100.160 70.980 100.330 ;
        RECT 38.555 99.600 38.725 100.100 ;
        RECT 71.195 99.600 71.365 100.100 ;
        RECT 38.940 99.370 70.980 99.540 ;
        RECT 38.555 98.810 38.725 99.310 ;
        RECT 71.195 98.810 71.365 99.310 ;
        RECT 38.940 98.580 70.980 98.750 ;
        RECT 38.555 98.020 38.725 98.520 ;
        RECT 71.195 98.020 71.365 98.520 ;
        RECT 38.940 97.790 70.980 97.960 ;
        RECT 38.555 97.230 38.725 97.730 ;
        RECT 71.195 97.230 71.365 97.730 ;
        RECT 38.940 97.000 70.980 97.170 ;
        RECT 38.555 96.440 38.725 96.940 ;
        RECT 71.195 96.440 71.365 96.940 ;
        RECT 38.940 96.210 70.980 96.380 ;
        RECT 38.555 95.650 38.725 96.150 ;
        RECT 71.195 95.650 71.365 96.150 ;
        RECT 38.940 95.420 70.980 95.590 ;
        RECT 38.555 94.860 38.725 95.360 ;
        RECT 71.195 94.860 71.365 95.360 ;
        RECT 38.940 94.630 70.980 94.800 ;
        RECT 38.555 94.070 38.725 94.570 ;
        RECT 71.195 94.070 71.365 94.570 ;
        RECT 38.940 93.840 70.980 94.010 ;
        RECT 38.555 93.280 38.725 93.780 ;
        RECT 71.195 93.280 71.365 93.780 ;
        RECT 38.940 93.050 70.980 93.220 ;
        RECT 38.555 92.490 38.725 92.990 ;
        RECT 71.195 92.490 71.365 92.990 ;
        RECT 38.940 92.260 70.980 92.430 ;
        RECT 38.555 91.700 38.725 92.200 ;
        RECT 71.195 91.700 71.365 92.200 ;
        RECT 38.940 91.470 70.980 91.640 ;
        RECT 38.555 90.910 38.725 91.410 ;
        RECT 71.195 90.910 71.365 91.410 ;
        RECT 38.940 90.680 70.980 90.850 ;
        RECT 38.555 90.120 38.725 90.620 ;
        RECT 71.195 90.120 71.365 90.620 ;
        RECT 38.940 89.890 70.980 90.060 ;
        RECT 38.555 89.330 38.725 89.830 ;
        RECT 71.195 89.330 71.365 89.830 ;
        RECT 38.940 89.100 70.980 89.270 ;
        RECT 38.555 88.540 38.725 89.040 ;
        RECT 71.195 88.540 71.365 89.040 ;
        RECT 38.940 88.310 70.980 88.480 ;
        RECT 38.555 87.750 38.725 88.250 ;
        RECT 71.195 87.750 71.365 88.250 ;
        RECT 38.940 87.520 70.980 87.690 ;
        RECT 38.555 86.960 38.725 87.460 ;
        RECT 71.195 86.960 71.365 87.460 ;
        RECT 38.940 86.730 70.980 86.900 ;
        RECT 38.555 86.170 38.725 86.670 ;
        RECT 71.195 86.170 71.365 86.670 ;
        RECT 38.940 85.940 70.980 86.110 ;
        RECT 38.555 85.380 38.725 85.880 ;
        RECT 71.195 85.380 71.365 85.880 ;
        RECT 38.940 85.150 70.980 85.320 ;
        RECT 38.555 84.590 38.725 85.090 ;
        RECT 71.195 84.590 71.365 85.090 ;
        RECT 38.940 84.360 70.980 84.530 ;
        RECT 38.555 83.800 38.725 84.300 ;
        RECT 71.195 83.800 71.365 84.300 ;
        RECT 38.940 83.570 70.980 83.740 ;
        RECT 38.555 83.010 38.725 83.510 ;
        RECT 71.195 83.010 71.365 83.510 ;
        RECT 38.940 82.780 70.980 82.950 ;
        RECT 38.555 82.220 38.725 82.720 ;
        RECT 71.195 82.220 71.365 82.720 ;
        RECT 38.940 81.990 70.980 82.160 ;
        RECT 38.555 81.430 38.725 81.930 ;
        RECT 71.195 81.430 71.365 81.930 ;
        RECT 38.940 81.200 70.980 81.370 ;
        RECT 38.555 80.640 38.725 81.140 ;
        RECT 71.195 80.640 71.365 81.140 ;
        RECT 38.940 80.410 70.980 80.580 ;
        RECT 38.555 79.850 38.725 80.350 ;
        RECT 71.195 79.850 71.365 80.350 ;
        RECT 38.940 79.620 70.980 79.790 ;
        RECT 71.585 79.420 72.355 105.270 ;
        RECT 37.565 78.650 72.355 79.420 ;
        RECT 72.655 115.250 107.355 116.020 ;
        RECT 72.655 111.520 73.425 115.250 ;
        RECT 73.985 114.880 106.025 115.050 ;
        RECT 73.645 114.320 73.815 114.820 ;
        RECT 106.195 114.320 106.365 114.820 ;
        RECT 73.985 114.090 106.025 114.260 ;
        RECT 73.645 113.530 73.815 114.030 ;
        RECT 106.195 113.530 106.365 114.030 ;
        RECT 73.985 113.300 106.025 113.470 ;
        RECT 73.645 112.740 73.815 113.240 ;
        RECT 106.195 112.740 106.365 113.240 ;
        RECT 73.985 112.510 106.025 112.680 ;
        RECT 73.645 111.950 73.815 112.450 ;
        RECT 106.195 111.950 106.365 112.450 ;
        RECT 73.985 111.720 106.025 111.890 ;
        RECT 106.585 111.520 107.355 115.250 ;
        RECT 72.655 110.170 107.355 111.520 ;
        RECT 72.655 84.320 73.425 110.170 ;
        RECT 73.985 109.800 106.025 109.970 ;
        RECT 73.645 109.240 73.815 109.740 ;
        RECT 106.195 109.240 106.365 109.740 ;
        RECT 73.985 109.010 106.025 109.180 ;
        RECT 73.645 108.450 73.815 108.950 ;
        RECT 106.195 108.450 106.365 108.950 ;
        RECT 73.985 108.220 106.025 108.390 ;
        RECT 73.645 107.660 73.815 108.160 ;
        RECT 106.195 107.660 106.365 108.160 ;
        RECT 73.985 107.430 106.025 107.600 ;
        RECT 73.645 106.870 73.815 107.370 ;
        RECT 106.195 106.870 106.365 107.370 ;
        RECT 73.985 106.640 106.025 106.810 ;
        RECT 73.645 106.080 73.815 106.580 ;
        RECT 106.195 106.080 106.365 106.580 ;
        RECT 73.985 105.850 106.025 106.020 ;
        RECT 73.645 105.290 73.815 105.790 ;
        RECT 106.195 105.290 106.365 105.790 ;
        RECT 73.985 105.060 106.025 105.230 ;
        RECT 73.645 104.500 73.815 105.000 ;
        RECT 106.195 104.500 106.365 105.000 ;
        RECT 73.985 104.270 106.025 104.440 ;
        RECT 73.645 103.710 73.815 104.210 ;
        RECT 106.195 103.710 106.365 104.210 ;
        RECT 73.985 103.480 106.025 103.650 ;
        RECT 73.645 102.920 73.815 103.420 ;
        RECT 106.195 102.920 106.365 103.420 ;
        RECT 73.985 102.690 106.025 102.860 ;
        RECT 73.645 102.130 73.815 102.630 ;
        RECT 106.195 102.130 106.365 102.630 ;
        RECT 73.985 101.900 106.025 102.070 ;
        RECT 73.645 101.340 73.815 101.840 ;
        RECT 106.195 101.340 106.365 101.840 ;
        RECT 73.985 101.110 106.025 101.280 ;
        RECT 73.645 100.550 73.815 101.050 ;
        RECT 106.195 100.550 106.365 101.050 ;
        RECT 73.985 100.320 106.025 100.490 ;
        RECT 73.645 99.760 73.815 100.260 ;
        RECT 106.195 99.760 106.365 100.260 ;
        RECT 73.985 99.530 106.025 99.700 ;
        RECT 73.645 98.970 73.815 99.470 ;
        RECT 106.195 98.970 106.365 99.470 ;
        RECT 73.985 98.740 106.025 98.910 ;
        RECT 73.645 98.180 73.815 98.680 ;
        RECT 106.195 98.180 106.365 98.680 ;
        RECT 73.985 97.950 106.025 98.120 ;
        RECT 73.645 97.390 73.815 97.890 ;
        RECT 106.195 97.390 106.365 97.890 ;
        RECT 73.985 97.160 106.025 97.330 ;
        RECT 73.645 96.600 73.815 97.100 ;
        RECT 106.195 96.600 106.365 97.100 ;
        RECT 73.985 96.370 106.025 96.540 ;
        RECT 73.645 95.810 73.815 96.310 ;
        RECT 106.195 95.810 106.365 96.310 ;
        RECT 73.985 95.580 106.025 95.750 ;
        RECT 73.645 95.020 73.815 95.520 ;
        RECT 106.195 95.020 106.365 95.520 ;
        RECT 73.985 94.790 106.025 94.960 ;
        RECT 73.645 94.230 73.815 94.730 ;
        RECT 106.195 94.230 106.365 94.730 ;
        RECT 73.985 94.000 106.025 94.170 ;
        RECT 73.645 93.440 73.815 93.940 ;
        RECT 106.195 93.440 106.365 93.940 ;
        RECT 73.985 93.210 106.025 93.380 ;
        RECT 73.645 92.650 73.815 93.150 ;
        RECT 106.195 92.650 106.365 93.150 ;
        RECT 73.985 92.420 106.025 92.590 ;
        RECT 73.645 91.860 73.815 92.360 ;
        RECT 106.195 91.860 106.365 92.360 ;
        RECT 73.985 91.630 106.025 91.800 ;
        RECT 73.645 91.070 73.815 91.570 ;
        RECT 106.195 91.070 106.365 91.570 ;
        RECT 73.985 90.840 106.025 91.010 ;
        RECT 73.645 90.280 73.815 90.780 ;
        RECT 106.195 90.280 106.365 90.780 ;
        RECT 73.985 90.050 106.025 90.220 ;
        RECT 73.645 89.490 73.815 89.990 ;
        RECT 106.195 89.490 106.365 89.990 ;
        RECT 73.985 89.260 106.025 89.430 ;
        RECT 73.645 88.700 73.815 89.200 ;
        RECT 106.195 88.700 106.365 89.200 ;
        RECT 73.985 88.470 106.025 88.640 ;
        RECT 73.645 87.910 73.815 88.410 ;
        RECT 106.195 87.910 106.365 88.410 ;
        RECT 73.985 87.680 106.025 87.850 ;
        RECT 73.645 87.120 73.815 87.620 ;
        RECT 106.195 87.120 106.365 87.620 ;
        RECT 73.985 86.890 106.025 87.060 ;
        RECT 73.645 86.330 73.815 86.830 ;
        RECT 106.195 86.330 106.365 86.830 ;
        RECT 73.985 86.100 106.025 86.270 ;
        RECT 73.645 85.540 73.815 86.040 ;
        RECT 106.195 85.540 106.365 86.040 ;
        RECT 73.985 85.310 106.025 85.480 ;
        RECT 73.645 84.750 73.815 85.250 ;
        RECT 106.195 84.750 106.365 85.250 ;
        RECT 73.985 84.520 106.025 84.690 ;
        RECT 106.585 84.320 107.355 110.170 ;
        RECT 72.655 82.950 107.355 84.320 ;
        RECT 72.655 79.220 73.425 82.950 ;
        RECT 73.985 82.580 106.025 82.750 ;
        RECT 73.645 82.020 73.815 82.520 ;
        RECT 106.195 82.020 106.365 82.520 ;
        RECT 73.985 81.790 106.025 81.960 ;
        RECT 73.645 81.230 73.815 81.730 ;
        RECT 106.195 81.230 106.365 81.730 ;
        RECT 73.985 81.000 106.025 81.170 ;
        RECT 73.645 80.440 73.815 80.940 ;
        RECT 106.195 80.440 106.365 80.940 ;
        RECT 73.985 80.210 106.025 80.380 ;
        RECT 73.645 79.650 73.815 80.150 ;
        RECT 106.195 79.650 106.365 80.150 ;
        RECT 73.985 79.420 106.025 79.590 ;
        RECT 106.585 79.220 107.355 82.950 ;
        RECT 42.845 78.410 47.845 78.650 ;
        RECT 42.765 76.410 47.925 78.410 ;
        RECT 50.175 78.310 50.945 78.330 ;
        RECT 72.655 78.310 107.355 79.220 ;
        RECT 50.155 77.880 107.355 78.310 ;
        RECT 50.155 77.540 73.425 77.880 ;
        RECT 50.175 76.710 50.945 77.540 ;
        RECT 51.185 76.950 53.345 77.300 ;
        RECT 60.345 76.950 62.505 77.300 ;
        RECT 62.745 76.710 64.345 77.540 ;
        RECT 64.585 76.950 66.745 77.300 ;
        RECT 69.545 76.950 71.705 77.300 ;
        RECT 72.245 76.710 72.415 77.540 ;
        RECT 72.655 76.710 73.425 77.540 ;
        RECT 73.985 77.510 106.025 77.680 ;
        RECT 73.645 76.950 73.815 77.450 ;
        RECT 106.195 76.950 106.365 77.450 ;
        RECT 73.985 76.720 106.025 76.890 ;
        RECT 50.155 76.520 73.425 76.710 ;
        RECT 106.585 76.520 107.355 77.880 ;
        RECT 50.155 75.940 107.355 76.520 ;
        RECT 50.175 75.920 50.945 75.940 ;
        RECT 72.655 75.750 107.355 75.940 ;
        RECT 108.990 73.015 109.160 120.355 ;
        RECT 34.330 72.845 109.160 73.015 ;
        RECT 109.990 72.015 126.645 121.355 ;
        RECT 20.395 57.155 126.645 72.015 ;
        RECT 20.395 19.365 24.620 57.155 ;
        RECT 25.450 56.155 84.630 56.325 ;
        RECT 25.450 20.365 25.620 56.155 ;
        RECT 75.175 51.570 81.415 51.600 ;
        RECT 53.635 51.370 59.965 51.400 ;
        RECT 53.605 51.030 59.995 51.370 ;
        RECT 31.235 46.890 34.565 46.920 ;
        RECT 35.325 46.890 38.565 46.920 ;
        RECT 31.205 46.550 34.595 46.890 ;
        RECT 31.205 44.790 31.575 46.550 ;
        RECT 32.380 45.980 33.420 46.150 ;
        RECT 31.995 45.420 32.165 45.920 ;
        RECT 33.635 45.420 33.805 45.920 ;
        RECT 32.380 45.190 33.420 45.360 ;
        RECT 34.225 44.790 34.595 46.550 ;
        RECT 31.205 44.630 34.595 44.790 ;
        RECT 29.335 44.450 34.595 44.630 ;
        RECT 35.295 46.550 38.595 46.890 ;
        RECT 35.295 44.790 35.665 46.550 ;
        RECT 36.425 45.980 37.465 46.150 ;
        RECT 36.085 45.420 36.255 45.920 ;
        RECT 37.635 45.420 37.805 45.920 ;
        RECT 36.425 45.190 37.465 45.360 ;
        RECT 38.225 44.790 38.595 46.550 ;
        RECT 35.295 44.630 38.595 44.790 ;
        RECT 35.295 44.450 41.085 44.630 ;
        RECT 29.335 44.420 34.565 44.450 ;
        RECT 35.325 44.420 41.085 44.450 ;
        RECT 29.335 43.870 32.235 44.420 ;
        RECT 37.585 43.870 41.085 44.420 ;
        RECT 29.335 43.840 34.565 43.870 ;
        RECT 35.325 43.840 41.085 43.870 ;
        RECT 29.335 43.630 34.595 43.840 ;
        RECT 31.205 43.500 34.595 43.630 ;
        RECT 31.205 41.740 31.575 43.500 ;
        RECT 32.380 42.930 33.420 43.100 ;
        RECT 31.995 42.370 32.165 42.870 ;
        RECT 33.635 42.370 33.805 42.870 ;
        RECT 32.380 42.140 33.420 42.310 ;
        RECT 34.225 41.740 34.595 43.500 ;
        RECT 31.205 41.400 34.595 41.740 ;
        RECT 35.295 43.630 41.085 43.840 ;
        RECT 53.605 43.740 53.975 51.030 ;
        RECT 54.780 50.460 58.820 50.630 ;
        RECT 54.395 49.900 54.565 50.400 ;
        RECT 59.035 49.900 59.205 50.400 ;
        RECT 54.780 49.670 58.820 49.840 ;
        RECT 54.395 49.110 54.565 49.610 ;
        RECT 59.035 49.110 59.205 49.610 ;
        RECT 54.780 48.880 58.820 49.050 ;
        RECT 54.395 48.320 54.565 48.820 ;
        RECT 59.035 48.320 59.205 48.820 ;
        RECT 54.780 48.090 58.820 48.260 ;
        RECT 54.395 47.530 54.565 48.030 ;
        RECT 59.035 47.530 59.205 48.030 ;
        RECT 54.780 47.300 58.820 47.470 ;
        RECT 54.395 46.740 54.565 47.240 ;
        RECT 59.035 46.740 59.205 47.240 ;
        RECT 54.780 46.510 58.820 46.680 ;
        RECT 54.395 45.950 54.565 46.450 ;
        RECT 59.035 45.950 59.205 46.450 ;
        RECT 54.780 45.720 58.820 45.890 ;
        RECT 54.395 45.160 54.565 45.660 ;
        RECT 59.035 45.160 59.205 45.660 ;
        RECT 54.780 44.930 58.820 45.100 ;
        RECT 54.395 44.370 54.565 44.870 ;
        RECT 59.035 44.370 59.205 44.870 ;
        RECT 54.780 44.140 58.820 44.310 ;
        RECT 59.625 43.740 59.995 51.030 ;
        RECT 35.295 43.500 38.595 43.630 ;
        RECT 53.605 43.580 59.995 43.740 ;
        RECT 75.145 51.230 81.445 51.570 ;
        RECT 75.145 43.940 75.515 51.230 ;
        RECT 76.275 50.660 80.315 50.830 ;
        RECT 75.935 50.100 76.105 50.600 ;
        RECT 80.485 50.100 80.655 50.600 ;
        RECT 76.275 49.870 80.315 50.040 ;
        RECT 75.935 49.310 76.105 49.810 ;
        RECT 80.485 49.310 80.655 49.810 ;
        RECT 76.275 49.080 80.315 49.250 ;
        RECT 75.935 48.520 76.105 49.020 ;
        RECT 80.485 48.520 80.655 49.020 ;
        RECT 76.275 48.290 80.315 48.460 ;
        RECT 75.935 47.730 76.105 48.230 ;
        RECT 80.485 47.730 80.655 48.230 ;
        RECT 76.275 47.500 80.315 47.670 ;
        RECT 75.935 46.940 76.105 47.440 ;
        RECT 80.485 46.940 80.655 47.440 ;
        RECT 76.275 46.710 80.315 46.880 ;
        RECT 75.935 46.150 76.105 46.650 ;
        RECT 80.485 46.150 80.655 46.650 ;
        RECT 76.275 45.920 80.315 46.090 ;
        RECT 75.935 45.360 76.105 45.860 ;
        RECT 80.485 45.360 80.655 45.860 ;
        RECT 76.275 45.130 80.315 45.300 ;
        RECT 75.935 44.570 76.105 45.070 ;
        RECT 80.485 44.570 80.655 45.070 ;
        RECT 76.275 44.340 80.315 44.510 ;
        RECT 81.075 43.940 81.445 51.230 ;
        RECT 75.145 43.840 81.445 43.940 ;
        RECT 75.145 43.600 81.485 43.840 ;
        RECT 35.295 41.740 35.665 43.500 ;
        RECT 36.425 42.930 37.465 43.100 ;
        RECT 36.085 42.370 36.255 42.870 ;
        RECT 37.635 42.370 37.805 42.870 ;
        RECT 36.425 42.140 37.465 42.310 ;
        RECT 38.225 41.740 38.595 43.500 ;
        RECT 53.585 43.400 59.995 43.580 ;
        RECT 75.175 43.570 81.485 43.600 ;
        RECT 53.585 43.370 59.965 43.400 ;
        RECT 53.585 41.840 54.585 43.370 ;
        RECT 35.295 41.400 38.595 41.740 ;
        RECT 31.235 41.370 34.565 41.400 ;
        RECT 35.325 41.370 38.565 41.400 ;
        RECT 53.185 40.550 54.585 41.840 ;
        RECT 80.460 40.600 81.485 43.570 ;
        RECT 75.175 40.570 81.485 40.600 ;
        RECT 53.185 40.520 59.965 40.550 ;
        RECT 53.185 40.180 59.995 40.520 ;
        RECT 53.185 38.680 53.975 40.180 ;
        RECT 54.780 39.610 58.820 39.780 ;
        RECT 54.395 39.050 54.565 39.550 ;
        RECT 59.035 39.050 59.205 39.550 ;
        RECT 54.780 38.820 58.820 38.990 ;
        RECT 52.385 38.650 53.975 38.680 ;
        RECT 48.665 34.710 53.975 38.650 ;
        RECT 54.395 38.260 54.565 38.760 ;
        RECT 59.035 38.260 59.205 38.760 ;
        RECT 54.780 38.030 58.820 38.200 ;
        RECT 54.395 37.470 54.565 37.970 ;
        RECT 59.035 37.470 59.205 37.970 ;
        RECT 54.780 37.240 58.820 37.410 ;
        RECT 54.395 36.680 54.565 37.180 ;
        RECT 59.035 36.680 59.205 37.180 ;
        RECT 54.780 36.450 58.820 36.620 ;
        RECT 54.395 35.890 54.565 36.390 ;
        RECT 59.035 35.890 59.205 36.390 ;
        RECT 54.780 35.660 58.820 35.830 ;
        RECT 54.395 35.100 54.565 35.600 ;
        RECT 59.035 35.100 59.205 35.600 ;
        RECT 54.780 34.870 58.820 35.040 ;
        RECT 51.635 34.680 53.975 34.710 ;
        RECT 53.585 34.180 53.975 34.680 ;
        RECT 54.395 34.310 54.565 34.810 ;
        RECT 59.035 34.310 59.205 34.810 ;
        RECT 53.605 32.890 53.975 34.180 ;
        RECT 54.780 34.080 58.820 34.250 ;
        RECT 54.395 33.520 54.565 34.020 ;
        RECT 59.035 33.520 59.205 34.020 ;
        RECT 54.780 33.290 58.820 33.460 ;
        RECT 59.625 32.890 59.995 40.180 ;
        RECT 53.605 32.790 59.995 32.890 ;
        RECT 53.585 32.550 59.995 32.790 ;
        RECT 75.145 40.340 81.485 40.570 ;
        RECT 75.145 40.230 81.445 40.340 ;
        RECT 75.145 32.940 75.515 40.230 ;
        RECT 76.275 39.660 80.315 39.830 ;
        RECT 75.935 39.100 76.105 39.600 ;
        RECT 80.485 39.100 80.655 39.600 ;
        RECT 76.275 38.870 80.315 39.040 ;
        RECT 75.935 38.310 76.105 38.810 ;
        RECT 80.485 38.310 80.655 38.810 ;
        RECT 76.275 38.080 80.315 38.250 ;
        RECT 75.935 37.520 76.105 38.020 ;
        RECT 80.485 37.520 80.655 38.020 ;
        RECT 76.275 37.290 80.315 37.460 ;
        RECT 75.935 36.730 76.105 37.230 ;
        RECT 80.485 36.730 80.655 37.230 ;
        RECT 76.275 36.500 80.315 36.670 ;
        RECT 75.935 35.940 76.105 36.440 ;
        RECT 80.485 35.940 80.655 36.440 ;
        RECT 76.275 35.710 80.315 35.880 ;
        RECT 75.935 35.150 76.105 35.650 ;
        RECT 80.485 35.150 80.655 35.650 ;
        RECT 76.275 34.920 80.315 35.090 ;
        RECT 75.935 34.360 76.105 34.860 ;
        RECT 80.485 34.360 80.655 34.860 ;
        RECT 76.275 34.130 80.315 34.300 ;
        RECT 75.935 33.570 76.105 34.070 ;
        RECT 80.485 33.570 80.655 34.070 ;
        RECT 76.275 33.340 80.315 33.510 ;
        RECT 81.075 32.940 81.445 40.230 ;
        RECT 75.145 32.830 81.445 32.940 ;
        RECT 75.145 32.600 82.285 32.830 ;
        RECT 75.175 32.570 82.285 32.600 ;
        RECT 53.585 30.720 59.985 32.550 ;
        RECT 53.585 30.430 59.995 30.720 ;
        RECT 53.605 30.380 59.995 30.430 ;
        RECT 31.235 29.790 34.565 29.820 ;
        RECT 35.325 29.790 38.565 29.820 ;
        RECT 31.205 29.450 34.595 29.790 ;
        RECT 31.205 27.690 31.575 29.450 ;
        RECT 32.380 28.880 33.420 29.050 ;
        RECT 31.995 28.320 32.165 28.820 ;
        RECT 33.635 28.320 33.805 28.820 ;
        RECT 32.380 28.090 33.420 28.260 ;
        RECT 34.225 27.690 34.595 29.450 ;
        RECT 31.205 27.530 34.595 27.690 ;
        RECT 29.335 27.350 34.595 27.530 ;
        RECT 35.295 29.450 38.595 29.790 ;
        RECT 35.295 27.690 35.665 29.450 ;
        RECT 36.425 28.880 37.465 29.050 ;
        RECT 36.085 28.320 36.255 28.820 ;
        RECT 37.635 28.320 37.805 28.820 ;
        RECT 36.425 28.090 37.465 28.260 ;
        RECT 38.225 27.690 38.595 29.450 ;
        RECT 35.295 27.350 38.595 27.690 ;
        RECT 29.335 27.320 34.565 27.350 ;
        RECT 35.315 27.320 38.565 27.350 ;
        RECT 29.335 26.770 32.235 27.320 ;
        RECT 35.315 26.770 36.255 27.320 ;
        RECT 29.335 26.740 34.565 26.770 ;
        RECT 35.315 26.740 38.565 26.770 ;
        RECT 29.335 26.530 34.595 26.740 ;
        RECT 31.205 26.400 34.595 26.530 ;
        RECT 31.205 24.640 31.575 26.400 ;
        RECT 32.380 25.830 33.420 26.000 ;
        RECT 31.995 25.270 32.165 25.770 ;
        RECT 33.635 25.270 33.805 25.770 ;
        RECT 32.380 25.040 33.420 25.210 ;
        RECT 34.225 24.640 34.595 26.400 ;
        RECT 31.205 24.300 34.595 24.640 ;
        RECT 35.295 26.400 38.595 26.740 ;
        RECT 35.295 24.640 35.665 26.400 ;
        RECT 36.425 25.830 37.465 26.000 ;
        RECT 36.085 25.270 36.255 25.770 ;
        RECT 37.635 25.270 37.805 25.770 ;
        RECT 36.425 25.040 37.465 25.210 ;
        RECT 38.225 24.640 38.595 26.400 ;
        RECT 35.295 24.300 38.595 24.640 ;
        RECT 31.235 24.270 34.565 24.300 ;
        RECT 35.325 24.270 38.565 24.300 ;
        RECT 53.605 23.090 53.975 30.380 ;
        RECT 54.780 29.810 58.820 29.980 ;
        RECT 54.395 29.250 54.565 29.750 ;
        RECT 59.035 29.250 59.205 29.750 ;
        RECT 54.780 29.020 58.820 29.190 ;
        RECT 54.395 28.460 54.565 28.960 ;
        RECT 59.035 28.460 59.205 28.960 ;
        RECT 54.780 28.230 58.820 28.400 ;
        RECT 54.395 27.670 54.565 28.170 ;
        RECT 59.035 27.670 59.205 28.170 ;
        RECT 54.780 27.440 58.820 27.610 ;
        RECT 54.395 26.880 54.565 27.380 ;
        RECT 59.035 26.880 59.205 27.380 ;
        RECT 59.625 27.230 59.995 30.380 ;
        RECT 78.710 29.950 80.730 30.450 ;
        RECT 81.285 29.980 82.285 32.570 ;
        RECT 78.710 28.940 79.210 29.950 ;
        RECT 79.555 29.195 79.885 29.685 ;
        RECT 80.230 28.940 80.730 29.950 ;
        RECT 78.710 28.430 80.730 28.940 ;
        RECT 54.780 26.650 58.820 26.820 ;
        RECT 54.395 26.090 54.565 26.590 ;
        RECT 59.035 26.090 59.205 26.590 ;
        RECT 54.780 25.860 58.820 26.030 ;
        RECT 54.395 25.300 54.565 25.800 ;
        RECT 59.035 25.300 59.205 25.800 ;
        RECT 54.780 25.070 58.820 25.240 ;
        RECT 54.395 24.510 54.565 25.010 ;
        RECT 59.035 24.510 59.205 25.010 ;
        RECT 54.780 24.280 58.820 24.450 ;
        RECT 54.395 23.720 54.565 24.220 ;
        RECT 59.035 23.720 59.205 24.220 ;
        RECT 54.780 23.490 58.820 23.660 ;
        RECT 59.625 23.090 61.785 27.230 ;
        RECT 77.680 26.780 81.760 27.285 ;
        RECT 77.680 23.730 78.185 26.780 ;
        RECT 78.730 25.735 80.710 26.235 ;
        RECT 78.730 24.755 79.230 25.735 ;
        RECT 79.555 25.000 79.885 25.490 ;
        RECT 80.210 24.755 80.710 25.735 ;
        RECT 78.730 24.255 80.710 24.755 ;
        RECT 81.235 23.730 81.760 26.780 ;
        RECT 77.680 23.205 81.760 23.730 ;
        RECT 53.605 22.750 61.785 23.090 ;
        RECT 53.635 22.720 61.785 22.750 ;
        RECT 59.635 21.230 61.785 22.720 ;
        RECT 84.460 20.365 84.630 56.155 ;
        RECT 25.450 20.195 84.630 20.365 ;
        RECT 85.460 44.310 126.645 57.155 ;
        RECT 85.460 42.205 126.630 44.310 ;
        RECT 85.460 19.365 94.070 42.205 ;
        RECT 20.395 16.615 94.070 19.365 ;
        RECT 94.900 41.205 121.630 41.375 ;
        RECT 94.900 17.615 95.070 41.205 ;
        RECT 117.310 36.540 119.320 40.640 ;
        RECT 114.175 36.510 120.055 36.540 ;
        RECT 114.145 36.170 120.085 36.510 ;
        RECT 97.235 35.460 100.205 35.490 ;
        RECT 100.425 35.460 103.305 35.490 ;
        RECT 97.205 35.120 100.215 35.460 ;
        RECT 97.205 33.910 97.575 35.120 ;
        RECT 97.815 34.350 97.985 34.680 ;
        RECT 98.200 34.650 99.240 34.820 ;
        RECT 98.200 34.210 99.240 34.380 ;
        RECT 99.455 34.350 99.625 34.680 ;
        RECT 99.865 33.910 100.215 35.120 ;
        RECT 97.205 33.570 100.215 33.910 ;
        RECT 100.415 35.120 103.335 35.460 ;
        RECT 100.415 33.910 100.765 35.120 ;
        RECT 101.005 34.350 101.175 34.680 ;
        RECT 101.345 34.650 102.385 34.820 ;
        RECT 101.345 34.210 102.385 34.380 ;
        RECT 102.555 34.350 102.725 34.680 ;
        RECT 102.965 33.910 103.335 35.120 ;
        RECT 100.415 33.660 103.335 33.910 ;
        RECT 100.415 33.570 104.615 33.660 ;
        RECT 97.235 33.540 100.205 33.570 ;
        RECT 100.425 33.540 104.615 33.570 ;
        RECT 98.215 30.640 99.215 33.540 ;
        RECT 102.315 32.660 104.615 33.540 ;
        RECT 105.465 27.770 107.465 31.640 ;
        RECT 114.145 31.560 114.515 36.170 ;
        RECT 114.755 35.380 114.925 35.710 ;
        RECT 115.095 35.700 119.135 35.870 ;
        RECT 115.095 35.220 119.135 35.390 ;
        RECT 114.755 34.420 114.925 34.750 ;
        RECT 115.095 34.740 119.135 34.910 ;
        RECT 119.305 34.900 119.475 35.230 ;
        RECT 115.095 34.260 119.135 34.430 ;
        RECT 114.755 33.460 114.925 33.790 ;
        RECT 115.095 33.780 119.135 33.950 ;
        RECT 119.305 33.940 119.475 34.270 ;
        RECT 115.095 33.300 119.135 33.470 ;
        RECT 114.755 32.500 114.925 32.830 ;
        RECT 115.095 32.820 119.135 32.990 ;
        RECT 119.305 32.980 119.475 33.310 ;
        RECT 115.095 32.340 119.135 32.510 ;
        RECT 115.095 31.860 119.135 32.030 ;
        RECT 119.305 32.020 119.475 32.350 ;
        RECT 119.715 31.560 120.085 36.170 ;
        RECT 114.145 31.220 120.085 31.560 ;
        RECT 114.175 31.190 120.055 31.220 ;
        RECT 117.315 27.780 119.315 31.190 ;
        RECT 104.685 27.740 110.655 27.770 ;
        RECT 114.175 27.750 120.055 27.780 ;
        RECT 104.655 27.400 110.685 27.740 ;
        RECT 97.235 25.190 100.205 25.220 ;
        RECT 100.425 25.190 103.305 25.220 ;
        RECT 97.205 24.850 100.215 25.190 ;
        RECT 97.205 23.640 97.575 24.850 ;
        RECT 97.815 24.080 97.985 24.410 ;
        RECT 98.200 24.380 99.240 24.550 ;
        RECT 98.200 23.940 99.240 24.110 ;
        RECT 99.455 24.080 99.625 24.410 ;
        RECT 99.865 23.640 100.215 24.850 ;
        RECT 97.205 23.300 100.215 23.640 ;
        RECT 100.415 24.850 103.335 25.190 ;
        RECT 100.415 23.640 100.765 24.850 ;
        RECT 101.005 24.080 101.175 24.410 ;
        RECT 101.345 24.380 102.385 24.550 ;
        RECT 101.345 23.940 102.385 24.110 ;
        RECT 102.555 24.080 102.725 24.410 ;
        RECT 102.965 23.640 103.335 24.850 ;
        RECT 100.415 23.300 103.335 23.640 ;
        RECT 97.235 23.270 100.205 23.300 ;
        RECT 100.425 23.270 103.305 23.300 ;
        RECT 98.215 19.390 99.215 23.270 ;
        RECT 104.655 22.790 105.025 27.400 ;
        RECT 105.265 26.610 105.435 26.940 ;
        RECT 105.650 26.930 109.690 27.100 ;
        RECT 105.650 26.450 109.690 26.620 ;
        RECT 105.265 25.650 105.435 25.980 ;
        RECT 105.650 25.970 109.690 26.140 ;
        RECT 109.905 26.130 110.075 26.460 ;
        RECT 105.650 25.490 109.690 25.660 ;
        RECT 105.265 24.690 105.435 25.020 ;
        RECT 105.650 25.010 109.690 25.180 ;
        RECT 109.905 25.170 110.075 25.500 ;
        RECT 105.650 24.530 109.690 24.700 ;
        RECT 105.265 23.730 105.435 24.060 ;
        RECT 105.650 24.050 109.690 24.220 ;
        RECT 109.905 24.210 110.075 24.540 ;
        RECT 105.650 23.570 109.690 23.740 ;
        RECT 105.650 23.090 109.690 23.260 ;
        RECT 109.905 23.250 110.075 23.580 ;
        RECT 110.315 22.790 110.685 27.400 ;
        RECT 104.655 22.450 110.685 22.790 ;
        RECT 114.145 27.410 120.085 27.750 ;
        RECT 114.145 22.800 114.515 27.410 ;
        RECT 114.755 26.620 114.925 26.950 ;
        RECT 115.095 26.940 119.135 27.110 ;
        RECT 115.095 26.460 119.135 26.630 ;
        RECT 114.755 25.660 114.925 25.990 ;
        RECT 115.095 25.980 119.135 26.150 ;
        RECT 119.305 26.140 119.475 26.470 ;
        RECT 115.095 25.500 119.135 25.670 ;
        RECT 114.755 24.700 114.925 25.030 ;
        RECT 115.095 25.020 119.135 25.190 ;
        RECT 119.305 25.180 119.475 25.510 ;
        RECT 115.095 24.540 119.135 24.710 ;
        RECT 114.755 23.740 114.925 24.070 ;
        RECT 115.095 24.060 119.135 24.230 ;
        RECT 119.305 24.220 119.475 24.550 ;
        RECT 115.095 23.580 119.135 23.750 ;
        RECT 115.095 23.100 119.135 23.270 ;
        RECT 119.305 23.260 119.475 23.590 ;
        RECT 119.715 22.800 120.085 27.410 ;
        RECT 114.145 22.460 120.085 22.800 ;
        RECT 104.685 22.420 110.655 22.450 ;
        RECT 114.175 22.430 120.055 22.460 ;
        RECT 121.460 17.615 121.630 41.205 ;
        RECT 94.900 17.445 121.630 17.615 ;
        RECT 122.460 16.615 126.630 42.205 ;
        RECT 20.395 12.460 126.630 16.615 ;
        RECT 24.395 12.445 126.630 12.460 ;
        RECT 122.630 5.080 126.630 12.445 ;
      LAYER met1 ;
        RECT 0.000 224.760 1.000 225.760 ;
        RECT 144.360 224.760 145.360 225.760 ;
        RECT 18.350 207.550 18.850 207.580 ;
        RECT 30.830 207.550 31.330 207.580 ;
        RECT 18.350 207.260 31.330 207.550 ;
        RECT 18.350 207.230 18.970 207.260 ;
        RECT 18.800 206.665 18.970 207.230 ;
        RECT 19.110 206.870 19.570 207.100 ;
        RECT 18.770 205.665 19.000 206.665 ;
        RECT 19.255 206.250 19.425 206.870 ;
        RECT 19.710 206.665 19.880 206.685 ;
        RECT 20.300 206.665 20.470 207.260 ;
        RECT 20.610 206.870 21.070 207.100 ;
        RECT 19.680 206.250 19.910 206.665 ;
        RECT 19.255 206.080 19.910 206.250 ;
        RECT 18.800 205.645 18.970 205.665 ;
        RECT 19.255 205.460 19.425 206.080 ;
        RECT 19.680 205.665 19.910 206.080 ;
        RECT 20.270 205.665 20.500 206.665 ;
        RECT 20.755 206.250 20.925 206.870 ;
        RECT 21.210 206.665 21.380 206.685 ;
        RECT 21.800 206.665 21.970 207.260 ;
        RECT 22.110 206.870 22.570 207.100 ;
        RECT 21.180 206.250 21.410 206.665 ;
        RECT 20.755 206.080 21.410 206.250 ;
        RECT 19.710 205.645 19.880 205.665 ;
        RECT 20.300 205.645 20.470 205.665 ;
        RECT 20.755 205.460 20.925 206.080 ;
        RECT 21.180 205.665 21.410 206.080 ;
        RECT 21.770 205.665 22.000 206.665 ;
        RECT 22.255 206.250 22.425 206.870 ;
        RECT 22.710 206.665 22.880 206.685 ;
        RECT 23.300 206.665 23.470 207.260 ;
        RECT 23.610 206.870 24.070 207.100 ;
        RECT 22.680 206.250 22.910 206.665 ;
        RECT 22.255 206.080 22.910 206.250 ;
        RECT 21.210 205.645 21.380 205.665 ;
        RECT 21.800 205.645 21.970 205.665 ;
        RECT 22.255 205.460 22.425 206.080 ;
        RECT 22.680 205.665 22.910 206.080 ;
        RECT 23.270 205.665 23.500 206.665 ;
        RECT 23.755 206.250 23.925 206.870 ;
        RECT 24.210 206.665 24.380 206.685 ;
        RECT 24.800 206.665 24.970 207.260 ;
        RECT 25.110 206.870 25.570 207.100 ;
        RECT 24.180 206.250 24.410 206.665 ;
        RECT 23.755 206.080 24.410 206.250 ;
        RECT 22.710 205.645 22.880 205.665 ;
        RECT 23.300 205.645 23.470 205.665 ;
        RECT 23.755 205.460 23.925 206.080 ;
        RECT 24.180 205.665 24.410 206.080 ;
        RECT 24.770 205.665 25.000 206.665 ;
        RECT 25.255 206.250 25.425 206.870 ;
        RECT 25.710 206.665 25.880 206.685 ;
        RECT 26.300 206.665 26.470 207.260 ;
        RECT 26.610 206.870 27.070 207.100 ;
        RECT 25.680 206.250 25.910 206.665 ;
        RECT 25.255 206.080 25.910 206.250 ;
        RECT 24.210 205.645 24.380 205.665 ;
        RECT 24.800 205.645 24.970 205.665 ;
        RECT 25.255 205.460 25.425 206.080 ;
        RECT 25.680 205.665 25.910 206.080 ;
        RECT 26.270 205.665 26.500 206.665 ;
        RECT 26.755 206.250 26.925 206.870 ;
        RECT 27.210 206.665 27.380 206.685 ;
        RECT 27.800 206.665 27.970 207.260 ;
        RECT 28.110 206.870 28.570 207.100 ;
        RECT 27.180 206.250 27.410 206.665 ;
        RECT 26.755 206.080 27.410 206.250 ;
        RECT 25.710 205.645 25.880 205.665 ;
        RECT 26.300 205.645 26.470 205.665 ;
        RECT 26.755 205.460 26.925 206.080 ;
        RECT 27.180 205.665 27.410 206.080 ;
        RECT 27.770 205.665 28.000 206.665 ;
        RECT 28.255 206.250 28.425 206.870 ;
        RECT 28.710 206.665 28.880 206.685 ;
        RECT 29.300 206.665 29.470 207.260 ;
        RECT 30.830 207.230 31.330 207.260 ;
        RECT 40.430 207.550 40.930 207.580 ;
        RECT 52.910 207.550 53.410 207.580 ;
        RECT 40.430 207.260 53.410 207.550 ;
        RECT 40.430 207.230 41.050 207.260 ;
        RECT 29.610 206.870 30.070 207.100 ;
        RECT 28.680 206.250 28.910 206.665 ;
        RECT 28.255 206.080 28.910 206.250 ;
        RECT 27.210 205.645 27.380 205.665 ;
        RECT 27.800 205.645 27.970 205.665 ;
        RECT 28.255 205.460 28.425 206.080 ;
        RECT 28.680 205.665 28.910 206.080 ;
        RECT 29.270 205.665 29.500 206.665 ;
        RECT 29.755 206.250 29.925 206.870 ;
        RECT 30.210 206.665 30.380 206.685 ;
        RECT 40.880 206.665 41.050 207.230 ;
        RECT 41.190 206.870 41.650 207.100 ;
        RECT 30.180 206.250 30.410 206.665 ;
        RECT 29.755 206.080 30.410 206.250 ;
        RECT 28.710 205.645 28.880 205.665 ;
        RECT 29.300 205.645 29.470 205.665 ;
        RECT 29.755 205.460 29.925 206.080 ;
        RECT 30.180 205.665 30.410 206.080 ;
        RECT 40.850 205.665 41.080 206.665 ;
        RECT 41.335 206.250 41.505 206.870 ;
        RECT 41.790 206.665 41.960 206.685 ;
        RECT 42.380 206.665 42.550 207.260 ;
        RECT 42.690 206.870 43.150 207.100 ;
        RECT 41.760 206.250 41.990 206.665 ;
        RECT 41.335 206.080 41.990 206.250 ;
        RECT 30.210 205.645 30.380 205.665 ;
        RECT 40.880 205.645 41.050 205.665 ;
        RECT 41.335 205.460 41.505 206.080 ;
        RECT 41.760 205.665 41.990 206.080 ;
        RECT 42.350 205.665 42.580 206.665 ;
        RECT 42.835 206.250 43.005 206.870 ;
        RECT 43.290 206.665 43.460 206.685 ;
        RECT 43.880 206.665 44.050 207.260 ;
        RECT 44.190 206.870 44.650 207.100 ;
        RECT 43.260 206.250 43.490 206.665 ;
        RECT 42.835 206.080 43.490 206.250 ;
        RECT 41.790 205.645 41.960 205.665 ;
        RECT 42.380 205.645 42.550 205.665 ;
        RECT 42.835 205.460 43.005 206.080 ;
        RECT 43.260 205.665 43.490 206.080 ;
        RECT 43.850 205.665 44.080 206.665 ;
        RECT 44.335 206.250 44.505 206.870 ;
        RECT 44.790 206.665 44.960 206.685 ;
        RECT 45.380 206.665 45.550 207.260 ;
        RECT 45.690 206.870 46.150 207.100 ;
        RECT 44.760 206.250 44.990 206.665 ;
        RECT 44.335 206.080 44.990 206.250 ;
        RECT 43.290 205.645 43.460 205.665 ;
        RECT 43.880 205.645 44.050 205.665 ;
        RECT 44.335 205.460 44.505 206.080 ;
        RECT 44.760 205.665 44.990 206.080 ;
        RECT 45.350 205.665 45.580 206.665 ;
        RECT 45.835 206.250 46.005 206.870 ;
        RECT 46.290 206.665 46.460 206.685 ;
        RECT 46.880 206.665 47.050 207.260 ;
        RECT 47.190 206.870 47.650 207.100 ;
        RECT 46.260 206.250 46.490 206.665 ;
        RECT 45.835 206.080 46.490 206.250 ;
        RECT 44.790 205.645 44.960 205.665 ;
        RECT 45.380 205.645 45.550 205.665 ;
        RECT 45.835 205.460 46.005 206.080 ;
        RECT 46.260 205.665 46.490 206.080 ;
        RECT 46.850 205.665 47.080 206.665 ;
        RECT 47.335 206.250 47.505 206.870 ;
        RECT 47.790 206.665 47.960 206.685 ;
        RECT 48.380 206.665 48.550 207.260 ;
        RECT 48.690 206.870 49.150 207.100 ;
        RECT 47.760 206.250 47.990 206.665 ;
        RECT 47.335 206.080 47.990 206.250 ;
        RECT 46.290 205.645 46.460 205.665 ;
        RECT 46.880 205.645 47.050 205.665 ;
        RECT 47.335 205.460 47.505 206.080 ;
        RECT 47.760 205.665 47.990 206.080 ;
        RECT 48.350 205.665 48.580 206.665 ;
        RECT 48.835 206.250 49.005 206.870 ;
        RECT 49.290 206.665 49.460 206.685 ;
        RECT 49.880 206.665 50.050 207.260 ;
        RECT 50.190 206.870 50.650 207.100 ;
        RECT 49.260 206.250 49.490 206.665 ;
        RECT 48.835 206.080 49.490 206.250 ;
        RECT 47.790 205.645 47.960 205.665 ;
        RECT 48.380 205.645 48.550 205.665 ;
        RECT 48.835 205.460 49.005 206.080 ;
        RECT 49.260 205.665 49.490 206.080 ;
        RECT 49.850 205.665 50.080 206.665 ;
        RECT 50.335 206.250 50.505 206.870 ;
        RECT 50.790 206.665 50.960 206.685 ;
        RECT 51.380 206.665 51.550 207.260 ;
        RECT 52.910 207.230 53.410 207.260 ;
        RECT 62.510 207.550 63.010 207.580 ;
        RECT 74.990 207.550 75.490 207.580 ;
        RECT 62.510 207.260 75.490 207.550 ;
        RECT 62.510 207.230 63.130 207.260 ;
        RECT 51.690 206.870 52.150 207.100 ;
        RECT 50.760 206.250 50.990 206.665 ;
        RECT 50.335 206.080 50.990 206.250 ;
        RECT 49.290 205.645 49.460 205.665 ;
        RECT 49.880 205.645 50.050 205.665 ;
        RECT 50.335 205.460 50.505 206.080 ;
        RECT 50.760 205.665 50.990 206.080 ;
        RECT 51.350 205.665 51.580 206.665 ;
        RECT 51.835 206.250 52.005 206.870 ;
        RECT 52.290 206.665 52.460 206.685 ;
        RECT 62.960 206.665 63.130 207.230 ;
        RECT 63.270 206.870 63.730 207.100 ;
        RECT 52.260 206.250 52.490 206.665 ;
        RECT 51.835 206.080 52.490 206.250 ;
        RECT 50.790 205.645 50.960 205.665 ;
        RECT 51.380 205.645 51.550 205.665 ;
        RECT 51.835 205.460 52.005 206.080 ;
        RECT 52.260 205.665 52.490 206.080 ;
        RECT 62.930 205.665 63.160 206.665 ;
        RECT 63.415 206.250 63.585 206.870 ;
        RECT 63.870 206.665 64.040 206.685 ;
        RECT 64.460 206.665 64.630 207.260 ;
        RECT 64.770 206.870 65.230 207.100 ;
        RECT 63.840 206.250 64.070 206.665 ;
        RECT 63.415 206.080 64.070 206.250 ;
        RECT 52.290 205.645 52.460 205.665 ;
        RECT 62.960 205.645 63.130 205.665 ;
        RECT 63.415 205.460 63.585 206.080 ;
        RECT 63.840 205.665 64.070 206.080 ;
        RECT 64.430 205.665 64.660 206.665 ;
        RECT 64.915 206.250 65.085 206.870 ;
        RECT 65.370 206.665 65.540 206.685 ;
        RECT 65.960 206.665 66.130 207.260 ;
        RECT 66.270 206.870 66.730 207.100 ;
        RECT 65.340 206.250 65.570 206.665 ;
        RECT 64.915 206.080 65.570 206.250 ;
        RECT 63.870 205.645 64.040 205.665 ;
        RECT 64.460 205.645 64.630 205.665 ;
        RECT 64.915 205.460 65.085 206.080 ;
        RECT 65.340 205.665 65.570 206.080 ;
        RECT 65.930 205.665 66.160 206.665 ;
        RECT 66.415 206.250 66.585 206.870 ;
        RECT 66.870 206.665 67.040 206.685 ;
        RECT 67.460 206.665 67.630 207.260 ;
        RECT 67.770 206.870 68.230 207.100 ;
        RECT 66.840 206.250 67.070 206.665 ;
        RECT 66.415 206.080 67.070 206.250 ;
        RECT 65.370 205.645 65.540 205.665 ;
        RECT 65.960 205.645 66.130 205.665 ;
        RECT 66.415 205.460 66.585 206.080 ;
        RECT 66.840 205.665 67.070 206.080 ;
        RECT 67.430 205.665 67.660 206.665 ;
        RECT 67.915 206.250 68.085 206.870 ;
        RECT 68.370 206.665 68.540 206.685 ;
        RECT 68.960 206.665 69.130 207.260 ;
        RECT 69.270 206.870 69.730 207.100 ;
        RECT 68.340 206.250 68.570 206.665 ;
        RECT 67.915 206.080 68.570 206.250 ;
        RECT 66.870 205.645 67.040 205.665 ;
        RECT 67.460 205.645 67.630 205.665 ;
        RECT 67.915 205.460 68.085 206.080 ;
        RECT 68.340 205.665 68.570 206.080 ;
        RECT 68.930 205.665 69.160 206.665 ;
        RECT 69.415 206.250 69.585 206.870 ;
        RECT 69.870 206.665 70.040 206.685 ;
        RECT 70.460 206.665 70.630 207.260 ;
        RECT 70.770 206.870 71.230 207.100 ;
        RECT 69.840 206.250 70.070 206.665 ;
        RECT 69.415 206.080 70.070 206.250 ;
        RECT 68.370 205.645 68.540 205.665 ;
        RECT 68.960 205.645 69.130 205.665 ;
        RECT 69.415 205.460 69.585 206.080 ;
        RECT 69.840 205.665 70.070 206.080 ;
        RECT 70.430 205.665 70.660 206.665 ;
        RECT 70.915 206.250 71.085 206.870 ;
        RECT 71.370 206.665 71.540 206.685 ;
        RECT 71.960 206.665 72.130 207.260 ;
        RECT 72.270 206.870 72.730 207.100 ;
        RECT 71.340 206.250 71.570 206.665 ;
        RECT 70.915 206.080 71.570 206.250 ;
        RECT 69.870 205.645 70.040 205.665 ;
        RECT 70.460 205.645 70.630 205.665 ;
        RECT 70.915 205.460 71.085 206.080 ;
        RECT 71.340 205.665 71.570 206.080 ;
        RECT 71.930 205.665 72.160 206.665 ;
        RECT 72.415 206.250 72.585 206.870 ;
        RECT 72.870 206.665 73.040 206.685 ;
        RECT 73.460 206.665 73.630 207.260 ;
        RECT 74.990 207.230 75.490 207.260 ;
        RECT 73.770 206.870 74.230 207.100 ;
        RECT 72.840 206.250 73.070 206.665 ;
        RECT 72.415 206.080 73.070 206.250 ;
        RECT 71.370 205.645 71.540 205.665 ;
        RECT 71.960 205.645 72.130 205.665 ;
        RECT 72.415 205.460 72.585 206.080 ;
        RECT 72.840 205.665 73.070 206.080 ;
        RECT 73.430 205.665 73.660 206.665 ;
        RECT 73.915 206.250 74.085 206.870 ;
        RECT 74.370 206.665 74.540 206.685 ;
        RECT 74.340 206.250 74.570 206.665 ;
        RECT 73.915 206.080 74.570 206.250 ;
        RECT 72.870 205.645 73.040 205.665 ;
        RECT 73.460 205.645 73.630 205.665 ;
        RECT 73.915 205.460 74.085 206.080 ;
        RECT 74.340 205.665 74.570 206.080 ;
        RECT 74.370 205.645 74.540 205.665 ;
        RECT 19.110 205.230 19.570 205.460 ;
        RECT 20.610 205.230 21.070 205.460 ;
        RECT 22.110 205.230 22.570 205.460 ;
        RECT 23.610 205.230 24.070 205.460 ;
        RECT 25.110 205.230 25.570 205.460 ;
        RECT 26.610 205.230 27.070 205.460 ;
        RECT 28.110 205.230 28.570 205.460 ;
        RECT 29.610 205.230 30.070 205.460 ;
        RECT 41.190 205.230 41.650 205.460 ;
        RECT 42.690 205.230 43.150 205.460 ;
        RECT 44.190 205.230 44.650 205.460 ;
        RECT 45.690 205.230 46.150 205.460 ;
        RECT 47.190 205.230 47.650 205.460 ;
        RECT 48.690 205.230 49.150 205.460 ;
        RECT 50.190 205.230 50.650 205.460 ;
        RECT 51.690 205.230 52.150 205.460 ;
        RECT 63.270 205.230 63.730 205.460 ;
        RECT 64.770 205.230 65.230 205.460 ;
        RECT 66.270 205.230 66.730 205.460 ;
        RECT 67.770 205.230 68.230 205.460 ;
        RECT 69.270 205.230 69.730 205.460 ;
        RECT 70.770 205.230 71.230 205.460 ;
        RECT 72.270 205.230 72.730 205.460 ;
        RECT 73.770 205.230 74.230 205.460 ;
        RECT 18.350 204.750 18.850 205.100 ;
        RECT 17.600 203.700 18.850 204.050 ;
        RECT 19.255 203.525 19.425 205.230 ;
        RECT 20.755 203.525 20.925 205.230 ;
        RECT 22.255 203.525 22.425 205.230 ;
        RECT 23.755 203.525 23.925 205.230 ;
        RECT 25.255 203.525 25.425 205.230 ;
        RECT 26.755 203.525 26.925 205.230 ;
        RECT 28.255 203.525 28.425 205.230 ;
        RECT 29.755 203.525 29.925 205.230 ;
        RECT 30.770 204.750 31.330 205.100 ;
        RECT 40.430 204.750 40.930 205.100 ;
        RECT 30.830 203.700 32.080 204.050 ;
        RECT 39.680 203.700 40.930 204.050 ;
        RECT 41.335 203.525 41.505 205.230 ;
        RECT 42.835 203.525 43.005 205.230 ;
        RECT 44.335 203.525 44.505 205.230 ;
        RECT 45.835 203.525 46.005 205.230 ;
        RECT 47.335 203.525 47.505 205.230 ;
        RECT 48.835 203.525 49.005 205.230 ;
        RECT 50.335 203.525 50.505 205.230 ;
        RECT 51.835 203.525 52.005 205.230 ;
        RECT 52.850 204.750 53.410 205.100 ;
        RECT 62.510 204.750 63.010 205.100 ;
        RECT 52.910 203.700 54.160 204.050 ;
        RECT 61.760 203.700 63.010 204.050 ;
        RECT 63.415 203.525 63.585 205.230 ;
        RECT 64.915 203.525 65.085 205.230 ;
        RECT 66.415 203.525 66.585 205.230 ;
        RECT 67.915 203.525 68.085 205.230 ;
        RECT 69.415 203.525 69.585 205.230 ;
        RECT 70.915 203.525 71.085 205.230 ;
        RECT 72.415 203.525 72.585 205.230 ;
        RECT 73.915 203.525 74.085 205.230 ;
        RECT 74.930 204.750 75.490 205.100 ;
        RECT 74.990 203.700 76.240 204.050 ;
        RECT 19.110 203.295 19.570 203.525 ;
        RECT 20.610 203.295 21.070 203.525 ;
        RECT 22.110 203.295 22.570 203.525 ;
        RECT 23.610 203.295 24.070 203.525 ;
        RECT 25.110 203.295 25.570 203.525 ;
        RECT 26.610 203.295 27.070 203.525 ;
        RECT 28.110 203.295 28.570 203.525 ;
        RECT 29.610 203.295 30.070 203.525 ;
        RECT 41.190 203.295 41.650 203.525 ;
        RECT 42.690 203.295 43.150 203.525 ;
        RECT 44.190 203.295 44.650 203.525 ;
        RECT 45.690 203.295 46.150 203.525 ;
        RECT 47.190 203.295 47.650 203.525 ;
        RECT 48.690 203.295 49.150 203.525 ;
        RECT 50.190 203.295 50.650 203.525 ;
        RECT 51.690 203.295 52.150 203.525 ;
        RECT 63.270 203.295 63.730 203.525 ;
        RECT 64.770 203.295 65.230 203.525 ;
        RECT 66.270 203.295 66.730 203.525 ;
        RECT 67.770 203.295 68.230 203.525 ;
        RECT 69.270 203.295 69.730 203.525 ;
        RECT 70.770 203.295 71.230 203.525 ;
        RECT 72.270 203.295 72.730 203.525 ;
        RECT 73.770 203.295 74.230 203.525 ;
        RECT 18.800 203.135 18.970 203.155 ;
        RECT 18.770 202.485 19.000 203.135 ;
        RECT 17.600 201.890 18.100 201.920 ;
        RECT 18.800 201.890 18.970 202.485 ;
        RECT 19.255 202.325 19.425 203.295 ;
        RECT 19.665 202.860 19.925 203.180 ;
        RECT 20.300 203.135 20.470 203.155 ;
        RECT 19.680 202.485 19.910 202.860 ;
        RECT 20.270 202.485 20.500 203.135 ;
        RECT 19.710 202.465 19.880 202.485 ;
        RECT 19.110 202.095 19.570 202.325 ;
        RECT 20.300 201.890 20.470 202.485 ;
        RECT 20.755 202.325 20.925 203.295 ;
        RECT 21.165 202.860 21.425 203.180 ;
        RECT 21.800 203.135 21.970 203.155 ;
        RECT 21.180 202.485 21.410 202.860 ;
        RECT 21.770 202.485 22.000 203.135 ;
        RECT 21.210 202.465 21.380 202.485 ;
        RECT 20.610 202.095 21.070 202.325 ;
        RECT 21.800 201.890 21.970 202.485 ;
        RECT 22.255 202.325 22.425 203.295 ;
        RECT 22.665 202.860 22.925 203.180 ;
        RECT 23.300 203.135 23.470 203.155 ;
        RECT 22.680 202.485 22.910 202.860 ;
        RECT 23.270 202.485 23.500 203.135 ;
        RECT 22.710 202.465 22.880 202.485 ;
        RECT 22.110 202.095 22.570 202.325 ;
        RECT 23.300 201.890 23.470 202.485 ;
        RECT 23.755 202.325 23.925 203.295 ;
        RECT 24.165 202.860 24.425 203.180 ;
        RECT 24.800 203.135 24.970 203.155 ;
        RECT 24.180 202.485 24.410 202.860 ;
        RECT 24.770 202.485 25.000 203.135 ;
        RECT 24.210 202.465 24.380 202.485 ;
        RECT 23.610 202.095 24.070 202.325 ;
        RECT 24.800 201.890 24.970 202.485 ;
        RECT 25.255 202.325 25.425 203.295 ;
        RECT 25.665 202.860 25.925 203.180 ;
        RECT 26.300 203.135 26.470 203.155 ;
        RECT 25.680 202.485 25.910 202.860 ;
        RECT 26.270 202.485 26.500 203.135 ;
        RECT 25.710 202.465 25.880 202.485 ;
        RECT 25.110 202.095 25.570 202.325 ;
        RECT 26.300 201.890 26.470 202.485 ;
        RECT 26.755 202.325 26.925 203.295 ;
        RECT 27.165 202.860 27.425 203.180 ;
        RECT 27.800 203.135 27.970 203.155 ;
        RECT 27.180 202.485 27.410 202.860 ;
        RECT 27.770 202.485 28.000 203.135 ;
        RECT 27.210 202.465 27.380 202.485 ;
        RECT 26.610 202.095 27.070 202.325 ;
        RECT 27.800 201.890 27.970 202.485 ;
        RECT 28.255 202.325 28.425 203.295 ;
        RECT 28.665 202.860 28.925 203.180 ;
        RECT 29.300 203.135 29.470 203.155 ;
        RECT 28.680 202.485 28.910 202.860 ;
        RECT 29.270 202.485 29.500 203.135 ;
        RECT 28.710 202.465 28.880 202.485 ;
        RECT 28.110 202.095 28.570 202.325 ;
        RECT 29.300 201.890 29.470 202.485 ;
        RECT 29.755 202.325 29.925 203.295 ;
        RECT 30.165 202.860 30.425 203.180 ;
        RECT 40.880 203.135 41.050 203.155 ;
        RECT 30.180 202.485 30.410 202.860 ;
        RECT 40.850 202.485 41.080 203.135 ;
        RECT 30.210 202.465 30.380 202.485 ;
        RECT 29.610 202.095 30.070 202.325 ;
        RECT 31.580 201.890 32.080 201.920 ;
        RECT 17.600 201.600 32.080 201.890 ;
        RECT 17.600 201.570 18.100 201.600 ;
        RECT 31.580 201.570 32.080 201.600 ;
        RECT 39.680 201.890 40.180 201.920 ;
        RECT 40.880 201.890 41.050 202.485 ;
        RECT 41.335 202.325 41.505 203.295 ;
        RECT 41.745 202.860 42.005 203.180 ;
        RECT 42.380 203.135 42.550 203.155 ;
        RECT 41.760 202.485 41.990 202.860 ;
        RECT 42.350 202.485 42.580 203.135 ;
        RECT 41.790 202.465 41.960 202.485 ;
        RECT 41.190 202.095 41.650 202.325 ;
        RECT 42.380 201.890 42.550 202.485 ;
        RECT 42.835 202.325 43.005 203.295 ;
        RECT 43.245 202.860 43.505 203.180 ;
        RECT 43.880 203.135 44.050 203.155 ;
        RECT 43.260 202.485 43.490 202.860 ;
        RECT 43.850 202.485 44.080 203.135 ;
        RECT 43.290 202.465 43.460 202.485 ;
        RECT 42.690 202.095 43.150 202.325 ;
        RECT 43.880 201.890 44.050 202.485 ;
        RECT 44.335 202.325 44.505 203.295 ;
        RECT 44.745 202.860 45.005 203.180 ;
        RECT 45.380 203.135 45.550 203.155 ;
        RECT 44.760 202.485 44.990 202.860 ;
        RECT 45.350 202.485 45.580 203.135 ;
        RECT 44.790 202.465 44.960 202.485 ;
        RECT 44.190 202.095 44.650 202.325 ;
        RECT 45.380 201.890 45.550 202.485 ;
        RECT 45.835 202.325 46.005 203.295 ;
        RECT 46.245 202.860 46.505 203.180 ;
        RECT 46.880 203.135 47.050 203.155 ;
        RECT 46.260 202.485 46.490 202.860 ;
        RECT 46.850 202.485 47.080 203.135 ;
        RECT 46.290 202.465 46.460 202.485 ;
        RECT 45.690 202.095 46.150 202.325 ;
        RECT 46.880 201.890 47.050 202.485 ;
        RECT 47.335 202.325 47.505 203.295 ;
        RECT 47.745 202.860 48.005 203.180 ;
        RECT 48.380 203.135 48.550 203.155 ;
        RECT 47.760 202.485 47.990 202.860 ;
        RECT 48.350 202.485 48.580 203.135 ;
        RECT 47.790 202.465 47.960 202.485 ;
        RECT 47.190 202.095 47.650 202.325 ;
        RECT 48.380 201.890 48.550 202.485 ;
        RECT 48.835 202.325 49.005 203.295 ;
        RECT 49.245 202.860 49.505 203.180 ;
        RECT 49.880 203.135 50.050 203.155 ;
        RECT 49.260 202.485 49.490 202.860 ;
        RECT 49.850 202.485 50.080 203.135 ;
        RECT 49.290 202.465 49.460 202.485 ;
        RECT 48.690 202.095 49.150 202.325 ;
        RECT 49.880 201.890 50.050 202.485 ;
        RECT 50.335 202.325 50.505 203.295 ;
        RECT 50.745 202.860 51.005 203.180 ;
        RECT 51.380 203.135 51.550 203.155 ;
        RECT 50.760 202.485 50.990 202.860 ;
        RECT 51.350 202.485 51.580 203.135 ;
        RECT 50.790 202.465 50.960 202.485 ;
        RECT 50.190 202.095 50.650 202.325 ;
        RECT 51.380 201.890 51.550 202.485 ;
        RECT 51.835 202.325 52.005 203.295 ;
        RECT 52.245 202.860 52.505 203.180 ;
        RECT 62.960 203.135 63.130 203.155 ;
        RECT 52.260 202.485 52.490 202.860 ;
        RECT 62.930 202.485 63.160 203.135 ;
        RECT 52.290 202.465 52.460 202.485 ;
        RECT 51.690 202.095 52.150 202.325 ;
        RECT 53.660 201.890 54.160 201.920 ;
        RECT 39.680 201.600 54.160 201.890 ;
        RECT 39.680 201.570 40.180 201.600 ;
        RECT 53.660 201.570 54.160 201.600 ;
        RECT 61.760 201.890 62.260 201.920 ;
        RECT 62.960 201.890 63.130 202.485 ;
        RECT 63.415 202.325 63.585 203.295 ;
        RECT 63.825 202.860 64.085 203.180 ;
        RECT 64.460 203.135 64.630 203.155 ;
        RECT 63.840 202.485 64.070 202.860 ;
        RECT 64.430 202.485 64.660 203.135 ;
        RECT 63.870 202.465 64.040 202.485 ;
        RECT 63.270 202.095 63.730 202.325 ;
        RECT 64.460 201.890 64.630 202.485 ;
        RECT 64.915 202.325 65.085 203.295 ;
        RECT 65.325 202.860 65.585 203.180 ;
        RECT 65.960 203.135 66.130 203.155 ;
        RECT 65.340 202.485 65.570 202.860 ;
        RECT 65.930 202.485 66.160 203.135 ;
        RECT 65.370 202.465 65.540 202.485 ;
        RECT 64.770 202.095 65.230 202.325 ;
        RECT 65.960 201.890 66.130 202.485 ;
        RECT 66.415 202.325 66.585 203.295 ;
        RECT 66.825 202.860 67.085 203.180 ;
        RECT 67.460 203.135 67.630 203.155 ;
        RECT 66.840 202.485 67.070 202.860 ;
        RECT 67.430 202.485 67.660 203.135 ;
        RECT 66.870 202.465 67.040 202.485 ;
        RECT 66.270 202.095 66.730 202.325 ;
        RECT 67.460 201.890 67.630 202.485 ;
        RECT 67.915 202.325 68.085 203.295 ;
        RECT 68.325 202.860 68.585 203.180 ;
        RECT 68.960 203.135 69.130 203.155 ;
        RECT 68.340 202.485 68.570 202.860 ;
        RECT 68.930 202.485 69.160 203.135 ;
        RECT 68.370 202.465 68.540 202.485 ;
        RECT 67.770 202.095 68.230 202.325 ;
        RECT 68.960 201.890 69.130 202.485 ;
        RECT 69.415 202.325 69.585 203.295 ;
        RECT 69.825 202.860 70.085 203.180 ;
        RECT 70.460 203.135 70.630 203.155 ;
        RECT 69.840 202.485 70.070 202.860 ;
        RECT 70.430 202.485 70.660 203.135 ;
        RECT 69.870 202.465 70.040 202.485 ;
        RECT 69.270 202.095 69.730 202.325 ;
        RECT 70.460 201.890 70.630 202.485 ;
        RECT 70.915 202.325 71.085 203.295 ;
        RECT 71.325 202.860 71.585 203.180 ;
        RECT 71.960 203.135 72.130 203.155 ;
        RECT 71.340 202.485 71.570 202.860 ;
        RECT 71.930 202.485 72.160 203.135 ;
        RECT 71.370 202.465 71.540 202.485 ;
        RECT 70.770 202.095 71.230 202.325 ;
        RECT 71.960 201.890 72.130 202.485 ;
        RECT 72.415 202.325 72.585 203.295 ;
        RECT 72.825 202.860 73.085 203.180 ;
        RECT 73.460 203.135 73.630 203.155 ;
        RECT 72.840 202.485 73.070 202.860 ;
        RECT 73.430 202.485 73.660 203.135 ;
        RECT 72.870 202.465 73.040 202.485 ;
        RECT 72.270 202.095 72.730 202.325 ;
        RECT 73.460 201.890 73.630 202.485 ;
        RECT 73.915 202.325 74.085 203.295 ;
        RECT 74.325 202.860 74.585 203.180 ;
        RECT 74.340 202.485 74.570 202.860 ;
        RECT 74.370 202.465 74.540 202.485 ;
        RECT 73.770 202.095 74.230 202.325 ;
        RECT 75.740 201.890 76.240 201.920 ;
        RECT 61.760 201.600 76.240 201.890 ;
        RECT 61.760 201.570 62.260 201.600 ;
        RECT 75.740 201.570 76.240 201.600 ;
        RECT 96.795 175.910 97.295 175.940 ;
        RECT 87.895 175.410 97.295 175.910 ;
        RECT 85.215 173.930 87.415 174.010 ;
        RECT 85.095 173.680 87.415 173.930 ;
        RECT 85.215 173.100 87.415 173.680 ;
        RECT 85.095 172.850 87.415 173.100 ;
        RECT 85.215 172.760 87.415 172.850 ;
        RECT 85.215 172.270 87.415 172.360 ;
        RECT 85.095 172.020 87.415 172.270 ;
        RECT 85.215 171.440 87.415 172.020 ;
        RECT 85.095 171.190 87.415 171.440 ;
        RECT 85.215 171.110 87.415 171.190 ;
        RECT 87.895 170.110 88.395 175.410 ;
        RECT 96.795 175.050 97.295 175.410 ;
        RECT 91.215 174.365 93.445 174.860 ;
        RECT 96.650 174.820 97.650 175.050 ;
        RECT 97.795 174.890 98.295 174.920 ;
        RECT 98.495 174.890 98.995 179.040 ;
        RECT 132.265 178.535 136.325 182.535 ;
        RECT 132.295 178.510 136.325 178.535 ;
        RECT 132.295 178.460 136.295 178.510 ;
        RECT 100.165 176.410 100.720 176.905 ;
        RECT 100.195 175.000 100.695 176.410 ;
        RECT 99.145 174.890 99.645 174.920 ;
        RECT 96.215 174.770 96.445 174.785 ;
        RECT 97.795 174.770 99.645 174.890 ;
        RECT 99.795 174.770 100.795 175.000 ;
        RECT 100.955 174.770 101.185 174.785 ;
        RECT 96.170 174.510 96.490 174.770 ;
        RECT 97.795 174.510 99.655 174.770 ;
        RECT 100.195 174.760 100.695 174.770 ;
        RECT 100.195 174.755 100.425 174.760 ;
        RECT 100.935 174.725 101.255 174.770 ;
        RECT 100.935 174.555 101.280 174.725 ;
        RECT 100.935 174.510 101.255 174.555 ;
        RECT 96.215 174.495 96.445 174.510 ;
        RECT 91.215 173.610 93.415 174.365 ;
        RECT 94.795 173.780 95.295 174.340 ;
        RECT 96.650 174.230 97.650 174.460 ;
        RECT 97.795 174.390 99.645 174.510 ;
        RECT 97.795 174.360 98.295 174.390 ;
        RECT 91.215 171.910 93.415 173.160 ;
        RECT 95.285 172.940 95.545 172.985 ;
        RECT 95.270 172.710 95.560 172.940 ;
        RECT 95.285 172.665 95.545 172.710 ;
        RECT 96.795 172.505 97.295 174.230 ;
        RECT 97.485 172.940 97.745 172.985 ;
        RECT 97.470 172.710 97.760 172.940 ;
        RECT 97.485 172.665 97.745 172.710 ;
        RECT 95.005 172.260 95.235 172.505 ;
        RECT 94.215 172.255 95.235 172.260 ;
        RECT 95.595 172.255 95.825 172.505 ;
        RECT 96.795 172.255 97.435 172.505 ;
        RECT 97.795 172.255 98.025 172.505 ;
        RECT 98.495 172.255 98.995 174.390 ;
        RECT 99.145 174.360 99.645 174.390 ;
        RECT 99.795 174.280 100.795 174.510 ;
        RECT 100.955 174.495 101.185 174.510 ;
        RECT 103.815 174.360 106.045 174.860 ;
        RECT 99.780 172.970 99.950 172.995 ;
        RECT 99.735 172.900 99.995 172.970 ;
        RECT 99.720 172.670 100.010 172.900 ;
        RECT 99.735 172.650 99.995 172.670 ;
        RECT 100.195 172.510 100.695 174.280 ;
        RECT 103.845 173.610 106.045 174.360 ;
        RECT 101.880 172.970 102.050 172.995 ;
        RECT 101.835 172.900 102.095 172.970 ;
        RECT 101.820 172.670 102.110 172.900 ;
        RECT 101.835 172.650 102.095 172.670 ;
        RECT 99.505 172.255 99.735 172.510 ;
        RECT 99.995 172.260 100.695 172.510 ;
        RECT 101.605 172.260 101.835 172.510 ;
        RECT 102.095 172.260 102.325 172.510 ;
        RECT 102.545 172.260 103.045 172.290 ;
        RECT 94.195 172.135 95.245 172.255 ;
        RECT 95.595 172.135 97.445 172.255 ;
        RECT 97.795 172.140 99.745 172.255 ;
        RECT 99.995 172.140 101.845 172.260 ;
        RECT 102.095 172.140 103.045 172.260 ;
        RECT 94.195 171.875 95.250 172.135 ;
        RECT 95.580 171.875 97.450 172.135 ;
        RECT 97.765 171.880 99.750 172.140 ;
        RECT 99.980 171.880 101.850 172.140 ;
        RECT 102.080 171.880 103.045 172.140 ;
        RECT 103.845 171.910 106.045 173.160 ;
        RECT 109.995 172.760 112.195 174.010 ;
        RECT 97.780 171.875 99.745 171.880 ;
        RECT 94.195 171.755 95.245 171.875 ;
        RECT 95.595 171.755 97.445 171.875 ;
        RECT 97.795 171.755 99.745 171.875 ;
        RECT 99.995 171.760 101.845 171.880 ;
        RECT 102.095 171.760 103.045 171.880 ;
        RECT 91.215 170.260 93.415 171.510 ;
        RECT 95.005 171.505 95.235 171.755 ;
        RECT 95.595 171.505 95.825 171.755 ;
        RECT 97.205 171.505 97.435 171.755 ;
        RECT 97.795 171.505 98.025 171.755 ;
        RECT 99.505 171.510 99.735 171.755 ;
        RECT 99.995 171.510 100.225 171.760 ;
        RECT 101.605 171.510 101.835 171.760 ;
        RECT 102.095 171.510 102.325 171.760 ;
        RECT 102.545 171.730 103.045 171.760 ;
        RECT 99.735 171.350 99.995 171.370 ;
        RECT 101.835 171.350 102.095 171.370 ;
        RECT 95.285 171.300 95.545 171.345 ;
        RECT 97.485 171.300 97.745 171.345 ;
        RECT 95.270 171.070 95.560 171.300 ;
        RECT 97.470 171.070 97.760 171.300 ;
        RECT 99.720 171.120 100.010 171.350 ;
        RECT 101.820 171.120 102.110 171.350 ;
        RECT 95.285 171.025 95.545 171.070 ;
        RECT 97.485 171.025 97.745 171.070 ;
        RECT 99.735 171.050 99.995 171.120 ;
        RECT 101.835 171.050 102.095 171.120 ;
        RECT 99.780 171.025 99.950 171.050 ;
        RECT 101.880 171.025 102.050 171.050 ;
        RECT 91.765 170.250 93.415 170.260 ;
        RECT 86.695 169.610 88.395 170.110 ;
        RECT 91.795 169.620 93.415 170.250 ;
        RECT 103.845 170.260 106.045 171.510 ;
        RECT 109.995 171.110 112.195 172.360 ;
        RECT 103.845 169.620 104.295 170.260 ;
        RECT 86.695 166.630 87.195 169.610 ;
        RECT 91.795 169.120 104.295 169.620 ;
        RECT 91.795 167.470 93.995 168.720 ;
        RECT 109.995 168.270 112.195 169.520 ;
        RECT 89.195 167.110 89.695 167.140 ;
        RECT 89.165 166.610 89.725 167.110 ;
        RECT 89.195 166.580 89.695 166.610 ;
        RECT 91.795 165.820 93.995 167.070 ;
        RECT 109.995 166.620 112.195 167.870 ;
        RECT 91.795 164.120 93.995 165.370 ;
        RECT 109.995 164.970 112.195 166.220 ;
        RECT 91.795 163.220 99.025 163.720 ;
        RECT 109.995 163.320 112.195 164.570 ;
        RECT 16.145 138.910 20.145 138.960 ;
        RECT 16.115 134.910 20.175 138.910 ;
        RECT 16.145 68.610 20.145 134.910 ;
        RECT 45.995 134.180 49.995 134.385 ;
        RECT 79.795 134.310 84.795 136.310 ;
        RECT 37.795 79.810 38.795 134.010 ;
        RECT 38.960 133.950 70.960 134.180 ;
        RECT 45.995 133.745 49.995 133.950 ;
        RECT 59.945 133.390 60.945 133.595 ;
        RECT 38.960 133.160 70.960 133.390 ;
        RECT 59.945 132.955 60.945 133.160 ;
        RECT 45.995 132.600 49.995 132.805 ;
        RECT 38.960 132.370 70.960 132.600 ;
        RECT 45.995 132.165 49.995 132.370 ;
        RECT 59.945 131.810 60.945 132.015 ;
        RECT 38.960 131.580 70.960 131.810 ;
        RECT 59.945 131.375 60.945 131.580 ;
        RECT 45.995 131.020 49.995 131.225 ;
        RECT 38.960 130.790 70.960 131.020 ;
        RECT 45.995 130.585 49.995 130.790 ;
        RECT 45.995 115.280 49.995 115.485 ;
        RECT 38.960 115.050 70.960 115.280 ;
        RECT 45.995 114.845 49.995 115.050 ;
        RECT 59.945 114.490 60.945 114.695 ;
        RECT 38.960 114.260 70.960 114.490 ;
        RECT 59.945 114.055 60.945 114.260 ;
        RECT 45.995 113.700 49.995 113.905 ;
        RECT 38.960 113.470 70.960 113.700 ;
        RECT 45.995 113.265 49.995 113.470 ;
        RECT 59.945 112.910 60.945 113.115 ;
        RECT 38.960 112.680 70.960 112.910 ;
        RECT 59.945 112.475 60.945 112.680 ;
        RECT 45.995 112.120 49.995 112.325 ;
        RECT 38.960 111.890 70.960 112.120 ;
        RECT 45.995 111.685 49.995 111.890 ;
        RECT 45.995 110.180 49.995 110.385 ;
        RECT 38.960 109.950 70.960 110.180 ;
        RECT 45.995 109.745 49.995 109.950 ;
        RECT 59.945 109.390 60.945 109.595 ;
        RECT 38.960 109.160 70.960 109.390 ;
        RECT 59.945 108.955 60.945 109.160 ;
        RECT 45.995 108.600 49.995 108.805 ;
        RECT 38.960 108.370 70.960 108.600 ;
        RECT 45.995 108.165 49.995 108.370 ;
        RECT 59.945 107.810 60.945 108.015 ;
        RECT 38.960 107.580 70.960 107.810 ;
        RECT 59.945 107.375 60.945 107.580 ;
        RECT 45.995 107.020 49.995 107.225 ;
        RECT 38.960 106.790 70.960 107.020 ;
        RECT 45.995 106.585 49.995 106.790 ;
        RECT 45.995 105.100 49.995 105.305 ;
        RECT 38.960 104.870 70.960 105.100 ;
        RECT 45.995 104.665 49.995 104.870 ;
        RECT 59.945 104.310 60.945 104.515 ;
        RECT 38.960 104.080 70.960 104.310 ;
        RECT 59.945 103.875 60.945 104.080 ;
        RECT 45.995 103.520 49.995 103.725 ;
        RECT 38.960 103.290 70.960 103.520 ;
        RECT 45.995 103.085 49.995 103.290 ;
        RECT 59.945 102.730 60.945 102.935 ;
        RECT 38.960 102.500 70.960 102.730 ;
        RECT 59.945 102.295 60.945 102.500 ;
        RECT 45.995 101.940 49.995 102.145 ;
        RECT 38.960 101.710 70.960 101.940 ;
        RECT 45.995 101.505 49.995 101.710 ;
        RECT 59.945 101.150 60.945 101.355 ;
        RECT 38.960 100.920 70.960 101.150 ;
        RECT 59.945 100.715 60.945 100.920 ;
        RECT 45.995 100.360 49.995 100.565 ;
        RECT 38.960 100.130 70.960 100.360 ;
        RECT 45.995 99.925 49.995 100.130 ;
        RECT 59.945 99.570 60.945 99.775 ;
        RECT 38.960 99.340 70.960 99.570 ;
        RECT 59.945 99.135 60.945 99.340 ;
        RECT 45.995 98.780 49.995 98.985 ;
        RECT 38.960 98.550 70.960 98.780 ;
        RECT 45.995 98.345 49.995 98.550 ;
        RECT 59.945 97.990 60.945 98.195 ;
        RECT 38.960 97.760 70.960 97.990 ;
        RECT 59.945 97.555 60.945 97.760 ;
        RECT 45.995 97.200 49.995 97.405 ;
        RECT 38.960 96.970 70.960 97.200 ;
        RECT 45.995 96.765 49.995 96.970 ;
        RECT 59.945 96.410 60.945 96.615 ;
        RECT 38.960 96.180 70.960 96.410 ;
        RECT 59.945 95.975 60.945 96.180 ;
        RECT 45.995 95.620 49.995 95.825 ;
        RECT 38.960 95.390 70.960 95.620 ;
        RECT 45.995 95.185 49.995 95.390 ;
        RECT 59.945 94.830 60.945 95.035 ;
        RECT 38.960 94.600 70.960 94.830 ;
        RECT 59.945 94.395 60.945 94.600 ;
        RECT 45.995 94.040 49.995 94.245 ;
        RECT 38.960 93.810 70.960 94.040 ;
        RECT 45.995 93.605 49.995 93.810 ;
        RECT 59.945 93.250 60.945 93.455 ;
        RECT 38.960 93.020 70.960 93.250 ;
        RECT 59.945 92.815 60.945 93.020 ;
        RECT 45.995 92.460 49.995 92.665 ;
        RECT 38.960 92.230 70.960 92.460 ;
        RECT 45.995 92.025 49.995 92.230 ;
        RECT 59.945 91.670 60.945 91.875 ;
        RECT 38.960 91.440 70.960 91.670 ;
        RECT 59.945 91.235 60.945 91.440 ;
        RECT 45.995 90.880 49.995 91.085 ;
        RECT 38.960 90.650 70.960 90.880 ;
        RECT 45.995 90.445 49.995 90.650 ;
        RECT 59.945 90.090 60.945 90.295 ;
        RECT 38.960 89.860 70.960 90.090 ;
        RECT 59.945 89.655 60.945 89.860 ;
        RECT 45.995 89.300 49.995 89.505 ;
        RECT 38.960 89.070 70.960 89.300 ;
        RECT 45.995 88.865 49.995 89.070 ;
        RECT 59.945 88.510 60.945 88.715 ;
        RECT 38.960 88.280 70.960 88.510 ;
        RECT 59.945 88.075 60.945 88.280 ;
        RECT 45.995 87.720 49.995 87.925 ;
        RECT 38.960 87.490 70.960 87.720 ;
        RECT 45.995 87.285 49.995 87.490 ;
        RECT 59.945 86.930 60.945 87.135 ;
        RECT 38.960 86.700 70.960 86.930 ;
        RECT 59.945 86.495 60.945 86.700 ;
        RECT 45.995 86.140 49.995 86.345 ;
        RECT 38.960 85.910 70.960 86.140 ;
        RECT 45.995 85.705 49.995 85.910 ;
        RECT 59.945 85.350 60.945 85.555 ;
        RECT 38.960 85.120 70.960 85.350 ;
        RECT 59.945 84.915 60.945 85.120 ;
        RECT 45.995 84.560 49.995 84.765 ;
        RECT 38.960 84.330 70.960 84.560 ;
        RECT 45.995 84.125 49.995 84.330 ;
        RECT 59.945 83.770 60.945 83.975 ;
        RECT 38.960 83.540 70.960 83.770 ;
        RECT 59.945 83.335 60.945 83.540 ;
        RECT 45.995 82.980 49.995 83.185 ;
        RECT 38.960 82.750 70.960 82.980 ;
        RECT 45.995 82.545 49.995 82.750 ;
        RECT 59.945 82.190 60.945 82.395 ;
        RECT 38.960 81.960 70.960 82.190 ;
        RECT 59.945 81.755 60.945 81.960 ;
        RECT 45.995 81.400 49.995 81.605 ;
        RECT 38.960 81.170 70.960 81.400 ;
        RECT 45.995 80.965 49.995 81.170 ;
        RECT 59.945 80.610 60.945 80.815 ;
        RECT 38.960 80.380 70.960 80.610 ;
        RECT 59.945 80.175 60.945 80.380 ;
        RECT 45.995 79.820 49.995 80.025 ;
        RECT 38.960 79.590 70.960 79.820 ;
        RECT 71.145 79.760 72.145 134.010 ;
        RECT 72.865 131.250 77.925 133.370 ;
        RECT 81.845 131.610 83.645 131.815 ;
        RECT 73.545 125.430 77.545 131.250 ;
        RECT 78.745 129.360 79.745 131.460 ;
        RECT 79.905 131.380 83.905 131.610 ;
        RECT 81.845 131.175 83.645 131.380 ;
        RECT 80.365 130.820 81.365 131.025 ;
        RECT 79.905 130.590 83.905 130.820 ;
        RECT 80.365 130.385 81.365 130.590 ;
        RECT 84.045 129.360 85.045 131.460 ;
        RECT 78.745 128.360 86.895 129.360 ;
        RECT 85.895 124.830 86.895 128.360 ;
        RECT 118.395 127.960 119.395 140.390 ;
        RECT 118.395 126.960 122.675 127.960 ;
        RECT 72.845 118.910 97.845 119.910 ;
        RECT 99.795 118.910 128.395 119.910 ;
        RECT 72.845 111.860 73.845 118.910 ;
        RECT 90.715 116.150 95.775 118.270 ;
        RECT 96.845 117.810 97.845 118.910 ;
        RECT 103.145 117.810 104.145 118.015 ;
        RECT 96.795 116.810 97.845 117.810 ;
        RECT 98.005 117.580 106.005 117.810 ;
        RECT 103.145 117.375 104.145 117.580 ;
        RECT 99.845 117.020 100.845 117.225 ;
        RECT 96.845 116.780 97.845 116.810 ;
        RECT 98.005 116.790 106.005 117.020 ;
        RECT 99.845 116.585 100.845 116.790 ;
        RECT 84.045 115.080 85.045 115.285 ;
        RECT 74.005 114.850 106.005 115.080 ;
        RECT 84.045 114.645 85.045 114.850 ;
        RECT 91.945 114.290 95.945 114.495 ;
        RECT 74.005 114.060 106.005 114.290 ;
        RECT 91.945 113.855 95.945 114.060 ;
        RECT 84.045 113.500 85.045 113.705 ;
        RECT 74.005 113.270 106.005 113.500 ;
        RECT 84.045 113.065 85.045 113.270 ;
        RECT 91.945 112.710 95.945 112.915 ;
        RECT 74.005 112.480 106.005 112.710 ;
        RECT 91.945 112.275 95.945 112.480 ;
        RECT 84.045 111.920 85.045 112.125 ;
        RECT 74.005 111.690 106.005 111.920 ;
        RECT 106.145 111.860 107.145 118.910 ;
        RECT 84.045 111.485 85.045 111.690 ;
        RECT 84.045 110.000 85.045 110.205 ;
        RECT 45.995 79.385 49.995 79.590 ;
        RECT 72.845 79.560 73.845 109.810 ;
        RECT 74.005 109.770 106.005 110.000 ;
        RECT 84.045 109.565 85.045 109.770 ;
        RECT 94.945 109.210 95.945 109.415 ;
        RECT 74.005 108.980 106.005 109.210 ;
        RECT 94.945 108.775 95.945 108.980 ;
        RECT 84.045 108.420 85.045 108.625 ;
        RECT 74.005 108.190 106.005 108.420 ;
        RECT 84.045 107.985 85.045 108.190 ;
        RECT 94.945 107.630 95.945 107.835 ;
        RECT 74.005 107.400 106.005 107.630 ;
        RECT 94.945 107.195 95.945 107.400 ;
        RECT 84.045 106.840 85.045 107.045 ;
        RECT 74.005 106.610 106.005 106.840 ;
        RECT 84.045 106.405 85.045 106.610 ;
        RECT 94.945 106.050 95.945 106.255 ;
        RECT 74.005 105.820 106.005 106.050 ;
        RECT 94.945 105.615 95.945 105.820 ;
        RECT 84.045 105.260 85.045 105.465 ;
        RECT 74.005 105.030 106.005 105.260 ;
        RECT 84.045 104.825 85.045 105.030 ;
        RECT 94.945 104.470 95.945 104.675 ;
        RECT 74.005 104.240 106.005 104.470 ;
        RECT 94.945 104.035 95.945 104.240 ;
        RECT 84.045 103.680 85.045 103.885 ;
        RECT 74.005 103.450 106.005 103.680 ;
        RECT 84.045 103.245 85.045 103.450 ;
        RECT 94.945 102.890 95.945 103.095 ;
        RECT 74.005 102.660 106.005 102.890 ;
        RECT 94.945 102.455 95.945 102.660 ;
        RECT 84.045 102.100 85.045 102.305 ;
        RECT 74.005 101.870 106.005 102.100 ;
        RECT 84.045 101.665 85.045 101.870 ;
        RECT 94.945 101.310 95.945 101.515 ;
        RECT 74.005 101.080 106.005 101.310 ;
        RECT 94.945 100.875 95.945 101.080 ;
        RECT 84.045 100.520 85.045 100.725 ;
        RECT 74.005 100.290 106.005 100.520 ;
        RECT 84.045 100.085 85.045 100.290 ;
        RECT 94.945 99.730 95.945 99.935 ;
        RECT 74.005 99.500 106.005 99.730 ;
        RECT 94.945 99.295 95.945 99.500 ;
        RECT 84.045 98.940 85.045 99.145 ;
        RECT 74.005 98.710 106.005 98.940 ;
        RECT 84.045 98.505 85.045 98.710 ;
        RECT 94.945 98.150 95.945 98.355 ;
        RECT 74.005 97.920 106.005 98.150 ;
        RECT 94.945 97.715 95.945 97.920 ;
        RECT 84.045 97.360 85.045 97.565 ;
        RECT 74.005 97.130 106.005 97.360 ;
        RECT 84.045 96.925 85.045 97.130 ;
        RECT 94.945 96.570 95.945 96.775 ;
        RECT 106.145 96.710 107.145 109.860 ;
        RECT 74.005 96.340 106.005 96.570 ;
        RECT 94.945 96.135 95.945 96.340 ;
        RECT 84.045 95.780 85.045 95.985 ;
        RECT 74.005 95.550 106.005 95.780 ;
        RECT 106.145 95.710 122.730 96.710 ;
        RECT 84.045 95.345 85.045 95.550 ;
        RECT 94.945 94.990 95.945 95.195 ;
        RECT 74.005 94.760 106.005 94.990 ;
        RECT 94.945 94.555 95.945 94.760 ;
        RECT 84.045 94.200 85.045 94.405 ;
        RECT 74.005 93.970 106.005 94.200 ;
        RECT 84.045 93.765 85.045 93.970 ;
        RECT 94.945 93.410 95.945 93.615 ;
        RECT 74.005 93.180 106.005 93.410 ;
        RECT 94.945 92.975 95.945 93.180 ;
        RECT 84.045 92.620 85.045 92.825 ;
        RECT 74.005 92.390 106.005 92.620 ;
        RECT 84.045 92.185 85.045 92.390 ;
        RECT 94.945 91.830 95.945 92.035 ;
        RECT 74.005 91.600 106.005 91.830 ;
        RECT 94.945 91.395 95.945 91.600 ;
        RECT 84.045 91.040 85.045 91.245 ;
        RECT 74.005 90.810 106.005 91.040 ;
        RECT 84.045 90.605 85.045 90.810 ;
        RECT 94.945 90.250 95.945 90.455 ;
        RECT 74.005 90.020 106.005 90.250 ;
        RECT 94.945 89.815 95.945 90.020 ;
        RECT 84.045 89.460 85.045 89.665 ;
        RECT 74.005 89.230 106.005 89.460 ;
        RECT 84.045 89.025 85.045 89.230 ;
        RECT 94.945 88.670 95.945 88.875 ;
        RECT 74.005 88.440 106.005 88.670 ;
        RECT 94.945 88.235 95.945 88.440 ;
        RECT 84.045 87.880 85.045 88.085 ;
        RECT 74.005 87.650 106.005 87.880 ;
        RECT 84.045 87.445 85.045 87.650 ;
        RECT 106.145 87.460 107.145 95.710 ;
        RECT 94.945 87.090 95.945 87.295 ;
        RECT 74.005 86.860 106.005 87.090 ;
        RECT 94.945 86.655 95.945 86.860 ;
        RECT 84.045 86.300 85.045 86.505 ;
        RECT 106.145 86.460 122.730 87.460 ;
        RECT 74.005 86.070 106.005 86.300 ;
        RECT 84.045 85.865 85.045 86.070 ;
        RECT 94.945 85.510 95.945 85.715 ;
        RECT 74.005 85.280 106.005 85.510 ;
        RECT 94.945 85.075 95.945 85.280 ;
        RECT 84.045 84.720 85.045 84.925 ;
        RECT 74.005 84.490 106.005 84.720 ;
        RECT 84.045 84.285 85.045 84.490 ;
        RECT 84.045 82.780 85.045 82.985 ;
        RECT 74.005 82.550 106.005 82.780 ;
        RECT 84.045 82.345 85.045 82.550 ;
        RECT 91.945 81.990 95.945 82.195 ;
        RECT 74.005 81.760 106.005 81.990 ;
        RECT 91.945 81.555 95.945 81.760 ;
        RECT 84.045 81.200 85.045 81.405 ;
        RECT 74.005 80.970 106.005 81.200 ;
        RECT 84.045 80.765 85.045 80.970 ;
        RECT 91.945 80.410 95.945 80.615 ;
        RECT 106.145 80.560 107.145 86.460 ;
        RECT 110.145 81.210 122.705 82.210 ;
        RECT 74.005 80.180 106.005 80.410 ;
        RECT 91.945 79.975 95.945 80.180 ;
        RECT 84.045 79.620 85.045 79.825 ;
        RECT 74.005 79.390 106.005 79.620 ;
        RECT 106.145 79.560 109.295 80.560 ;
        RECT 84.045 79.185 85.045 79.390 ;
        RECT 42.815 76.350 47.875 78.470 ;
        RECT 91.945 77.710 95.945 77.915 ;
        RECT 51.115 76.625 53.425 77.625 ;
        RECT 60.295 76.625 62.545 77.625 ;
        RECT 64.515 76.625 66.775 77.625 ;
        RECT 69.545 76.625 73.845 77.625 ;
        RECT 74.005 77.480 106.005 77.710 ;
        RECT 91.945 77.275 95.945 77.480 ;
        RECT 84.045 76.920 85.045 77.125 ;
        RECT 74.005 76.690 106.005 76.920 ;
        RECT 61.545 75.460 62.545 76.625 ;
        RECT 72.845 75.710 73.845 76.625 ;
        RECT 84.045 76.485 85.045 76.690 ;
        RECT 106.145 75.710 107.145 77.590 ;
        RECT 61.545 74.460 71.995 75.460 ;
        RECT 72.845 74.710 107.145 75.710 ;
        RECT 72.845 74.680 73.845 74.710 ;
        RECT 70.995 73.860 71.995 74.460 ;
        RECT 108.295 73.860 109.295 79.560 ;
        RECT 70.995 72.860 109.295 73.860 ;
        RECT 110.145 71.910 111.145 81.210 ;
        RECT 89.165 70.910 111.145 71.910 ;
        RECT 45.995 68.610 49.995 68.640 ;
        RECT 62.285 68.610 66.285 68.640 ;
        RECT 16.145 64.610 42.075 68.610 ;
        RECT 45.995 64.610 66.285 68.610 ;
        RECT 45.995 64.580 49.995 64.610 ;
        RECT 62.285 64.580 66.285 64.610 ;
        RECT 68.665 68.610 72.665 68.640 ;
        RECT 100.145 68.610 104.145 68.640 ;
        RECT 68.665 64.610 104.145 68.610 ;
        RECT 127.395 65.910 128.395 118.910 ;
        RECT 68.665 64.580 72.665 64.610 ;
        RECT 100.145 64.580 104.145 64.610 ;
        RECT 113.195 64.910 128.395 65.910 ;
        RECT 12.295 62.660 14.295 62.690 ;
        RECT 108.865 62.660 110.865 62.690 ;
        RECT 12.295 60.660 110.865 62.660 ;
        RECT 12.295 60.630 14.295 60.660 ;
        RECT 108.865 60.630 110.865 60.660 ;
        RECT 40.085 59.130 44.085 59.160 ;
        RECT 80.435 59.130 84.435 59.160 ;
        RECT 16.765 55.130 84.465 59.130 ;
        RECT 16.765 46.760 20.765 55.130 ;
        RECT 40.085 55.100 44.085 55.130 ;
        RECT 80.435 55.100 84.435 55.130 ;
        RECT 48.625 54.250 49.650 54.270 ;
        RECT 48.595 53.225 76.110 54.250 ;
        RECT 48.625 53.215 50.795 53.225 ;
        RECT 48.625 53.185 49.650 53.215 ;
        RECT 34.305 51.090 60.035 52.090 ;
        RECT 34.475 51.065 60.035 51.090 ;
        RECT 16.735 42.760 20.795 46.760 ;
        RECT 32.650 46.480 37.195 46.980 ;
        RECT 32.650 46.180 33.150 46.480 ;
        RECT 36.695 46.180 37.195 46.480 ;
        RECT 38.285 46.180 39.285 46.210 ;
        RECT 32.400 45.950 33.400 46.180 ;
        RECT 36.445 45.950 37.445 46.180 ;
        RECT 31.735 45.390 32.235 45.950 ;
        RECT 33.585 45.920 34.085 45.950 ;
        RECT 33.555 45.420 35.085 45.920 ;
        RECT 32.400 45.160 33.400 45.390 ;
        RECT 32.650 44.790 33.150 45.160 ;
        RECT 29.335 44.630 30.335 44.660 ;
        RECT 29.305 43.630 30.365 44.630 ;
        RECT 31.685 44.420 34.115 44.790 ;
        RECT 31.685 44.380 33.150 44.420 ;
        RECT 30.705 43.880 33.150 44.380 ;
        RECT 31.685 43.870 33.150 43.880 ;
        RECT 29.335 43.600 30.335 43.630 ;
        RECT 31.685 43.500 34.115 43.870 ;
        RECT 32.650 43.130 33.150 43.500 ;
        RECT 32.400 42.900 33.400 43.130 ;
        RECT 31.735 42.340 32.235 42.900 ;
        RECT 33.585 42.340 34.085 42.900 ;
        RECT 32.400 42.110 33.400 42.340 ;
        RECT 32.650 41.830 33.150 42.110 ;
        RECT 34.585 41.830 35.085 45.420 ;
        RECT 35.785 45.390 36.285 45.950 ;
        RECT 37.585 45.400 38.085 45.960 ;
        RECT 36.445 45.160 37.445 45.390 ;
        RECT 38.285 45.180 47.715 46.180 ;
        RECT 36.695 44.790 37.195 45.160 ;
        RECT 38.285 45.150 39.285 45.180 ;
        RECT 35.775 44.420 38.115 44.790 ;
        RECT 36.695 44.380 38.115 44.420 ;
        RECT 36.695 43.880 39.065 44.380 ;
        RECT 36.695 43.870 38.115 43.880 ;
        RECT 35.775 43.500 38.115 43.870 ;
        RECT 40.055 43.630 41.115 44.630 ;
        RECT 53.585 43.705 54.610 51.065 ;
        RECT 54.810 50.660 55.630 50.680 ;
        RECT 54.800 50.430 58.800 50.660 ;
        RECT 54.810 50.410 55.630 50.430 ;
        RECT 59.010 50.380 60.035 51.065 ;
        RECT 59.005 49.920 60.035 50.380 ;
        RECT 57.970 49.870 58.790 49.890 ;
        RECT 54.800 49.640 58.800 49.870 ;
        RECT 57.970 49.620 58.790 49.640 ;
        RECT 59.010 49.590 60.035 49.920 ;
        RECT 59.005 49.130 60.035 49.590 ;
        RECT 54.810 49.080 55.630 49.100 ;
        RECT 54.800 48.850 58.800 49.080 ;
        RECT 54.810 48.830 55.630 48.850 ;
        RECT 59.010 48.800 60.035 49.130 ;
        RECT 59.005 48.340 60.035 48.800 ;
        RECT 57.970 48.290 58.790 48.310 ;
        RECT 54.800 48.060 58.800 48.290 ;
        RECT 57.970 48.040 58.790 48.060 ;
        RECT 59.010 48.010 60.035 48.340 ;
        RECT 59.005 47.550 60.035 48.010 ;
        RECT 54.810 47.500 55.630 47.520 ;
        RECT 54.800 47.270 58.800 47.500 ;
        RECT 54.810 47.250 55.630 47.270 ;
        RECT 59.010 47.220 60.035 47.550 ;
        RECT 59.005 46.760 60.035 47.220 ;
        RECT 57.970 46.710 58.790 46.730 ;
        RECT 54.800 46.480 58.800 46.710 ;
        RECT 57.970 46.460 58.790 46.480 ;
        RECT 59.010 46.430 60.035 46.760 ;
        RECT 59.005 45.970 60.035 46.430 ;
        RECT 54.810 45.920 55.630 45.940 ;
        RECT 54.800 45.690 58.800 45.920 ;
        RECT 54.810 45.670 55.630 45.690 ;
        RECT 59.010 45.640 60.035 45.970 ;
        RECT 59.005 45.180 60.035 45.640 ;
        RECT 57.970 45.130 58.790 45.150 ;
        RECT 54.800 44.900 58.800 45.130 ;
        RECT 57.970 44.880 58.790 44.900 ;
        RECT 59.010 44.850 60.035 45.180 ;
        RECT 59.005 44.390 60.035 44.850 ;
        RECT 54.810 44.340 55.630 44.360 ;
        RECT 54.800 44.110 58.800 44.340 ;
        RECT 54.810 44.090 55.630 44.110 ;
        RECT 59.010 43.705 60.035 44.390 ;
        RECT 36.695 43.130 37.195 43.500 ;
        RECT 38.315 43.130 39.315 43.160 ;
        RECT 36.445 42.900 37.445 43.130 ;
        RECT 35.785 42.340 36.285 42.900 ;
        RECT 37.585 42.340 38.085 42.900 ;
        RECT 36.445 42.110 37.445 42.340 ;
        RECT 38.315 42.130 45.915 43.130 ;
        RECT 53.585 42.680 60.035 43.705 ;
        RECT 75.085 52.040 76.110 53.225 ;
        RECT 75.085 51.040 81.485 52.040 ;
        RECT 75.085 50.580 76.110 51.040 ;
        RECT 76.305 50.860 77.125 50.880 ;
        RECT 76.295 50.630 80.295 50.860 ;
        RECT 76.305 50.610 77.125 50.630 ;
        RECT 80.460 50.580 81.485 51.040 ;
        RECT 75.085 50.120 76.135 50.580 ;
        RECT 80.455 50.120 81.485 50.580 ;
        RECT 75.085 49.790 76.110 50.120 ;
        RECT 79.465 50.070 80.285 50.090 ;
        RECT 76.295 49.840 80.295 50.070 ;
        RECT 79.465 49.820 80.285 49.840 ;
        RECT 80.460 49.790 81.485 50.120 ;
        RECT 75.085 49.330 76.135 49.790 ;
        RECT 80.455 49.330 81.485 49.790 ;
        RECT 75.085 49.000 76.110 49.330 ;
        RECT 76.305 49.280 77.125 49.300 ;
        RECT 76.295 49.050 80.295 49.280 ;
        RECT 76.305 49.030 77.125 49.050 ;
        RECT 80.460 49.000 81.485 49.330 ;
        RECT 75.085 48.540 76.135 49.000 ;
        RECT 80.455 48.540 81.485 49.000 ;
        RECT 113.195 48.910 114.195 64.910 ;
        RECT 130.195 60.610 132.195 176.690 ;
        RECT 75.085 48.210 76.110 48.540 ;
        RECT 79.465 48.490 80.285 48.510 ;
        RECT 76.295 48.260 80.295 48.490 ;
        RECT 79.465 48.240 80.285 48.260 ;
        RECT 80.460 48.210 81.485 48.540 ;
        RECT 75.085 47.750 76.135 48.210 ;
        RECT 80.455 47.750 81.485 48.210 ;
        RECT 75.085 47.420 76.110 47.750 ;
        RECT 76.305 47.700 77.125 47.720 ;
        RECT 76.295 47.470 80.295 47.700 ;
        RECT 76.305 47.450 77.125 47.470 ;
        RECT 80.460 47.420 81.485 47.750 ;
        RECT 75.085 46.960 76.135 47.420 ;
        RECT 80.455 46.960 81.485 47.420 ;
        RECT 75.085 46.630 76.110 46.960 ;
        RECT 79.465 46.910 80.285 46.930 ;
        RECT 76.295 46.680 80.295 46.910 ;
        RECT 79.465 46.660 80.285 46.680 ;
        RECT 80.460 46.630 81.485 46.960 ;
        RECT 75.085 46.170 76.135 46.630 ;
        RECT 80.455 46.170 81.485 46.630 ;
        RECT 75.085 45.840 76.110 46.170 ;
        RECT 76.305 46.120 77.125 46.140 ;
        RECT 76.295 45.890 80.295 46.120 ;
        RECT 76.305 45.870 77.125 45.890 ;
        RECT 80.460 45.840 81.485 46.170 ;
        RECT 75.085 45.380 76.135 45.840 ;
        RECT 80.455 45.380 81.485 45.840 ;
        RECT 75.085 45.050 76.110 45.380 ;
        RECT 79.465 45.330 80.285 45.350 ;
        RECT 76.295 45.100 80.295 45.330 ;
        RECT 79.465 45.080 80.285 45.100 ;
        RECT 80.460 45.050 81.485 45.380 ;
        RECT 75.085 44.590 76.135 45.050 ;
        RECT 80.455 44.590 81.485 45.050 ;
        RECT 75.085 43.730 76.110 44.590 ;
        RECT 76.305 44.540 77.125 44.560 ;
        RECT 76.295 44.310 80.295 44.540 ;
        RECT 76.305 44.290 77.125 44.310 ;
        RECT 80.460 43.730 81.485 44.590 ;
        RECT 75.085 42.730 81.485 43.730 ;
        RECT 88.245 47.910 114.195 48.910 ;
        RECT 115.595 58.610 132.195 60.610 ;
        RECT 36.695 41.830 37.195 42.110 ;
        RECT 38.315 42.100 39.315 42.130 ;
        RECT 32.650 41.330 37.195 41.830 ;
        RECT 34.335 40.995 35.335 41.330 ;
        RECT 48.625 40.995 49.650 41.025 ;
        RECT 34.335 40.895 49.650 40.995 ;
        RECT 34.325 39.970 49.650 40.895 ;
        RECT 48.625 39.940 49.650 39.970 ;
        RECT 53.585 40.215 60.035 41.240 ;
        RECT 26.335 38.680 30.335 38.710 ;
        RECT 11.045 35.380 15.045 35.410 ;
        RECT 11.015 33.880 15.105 35.380 ;
        RECT 26.335 34.680 52.665 38.680 ;
        RECT 26.335 34.650 30.335 34.680 ;
        RECT 49.785 33.880 50.785 33.910 ;
        RECT 11.015 32.880 50.785 33.880 ;
        RECT 11.015 31.380 15.105 32.880 ;
        RECT 24.315 32.860 25.315 32.880 ;
        RECT 49.785 32.850 50.785 32.880 ;
        RECT 53.585 32.855 54.610 40.215 ;
        RECT 54.810 39.810 55.630 39.830 ;
        RECT 54.800 39.580 58.800 39.810 ;
        RECT 54.810 39.560 55.630 39.580 ;
        RECT 59.010 39.530 60.035 40.215 ;
        RECT 59.005 39.070 60.035 39.530 ;
        RECT 57.970 39.020 58.790 39.040 ;
        RECT 54.800 38.790 58.800 39.020 ;
        RECT 57.970 38.770 58.790 38.790 ;
        RECT 59.010 38.740 60.035 39.070 ;
        RECT 59.005 38.280 60.035 38.740 ;
        RECT 54.810 38.230 55.630 38.250 ;
        RECT 54.800 38.000 58.800 38.230 ;
        RECT 54.810 37.980 55.630 38.000 ;
        RECT 59.010 37.950 60.035 38.280 ;
        RECT 59.005 37.490 60.035 37.950 ;
        RECT 57.970 37.440 58.790 37.460 ;
        RECT 54.800 37.210 58.800 37.440 ;
        RECT 57.970 37.190 58.790 37.210 ;
        RECT 59.010 37.160 60.035 37.490 ;
        RECT 59.005 36.700 60.035 37.160 ;
        RECT 54.810 36.650 55.630 36.670 ;
        RECT 54.800 36.420 58.800 36.650 ;
        RECT 54.810 36.400 55.630 36.420 ;
        RECT 59.010 36.370 60.035 36.700 ;
        RECT 59.005 35.910 60.035 36.370 ;
        RECT 57.970 35.860 58.790 35.880 ;
        RECT 54.800 35.630 58.800 35.860 ;
        RECT 57.970 35.610 58.790 35.630 ;
        RECT 59.010 35.580 60.035 35.910 ;
        RECT 59.005 35.120 60.035 35.580 ;
        RECT 54.810 35.070 55.630 35.090 ;
        RECT 54.800 34.840 58.800 35.070 ;
        RECT 54.810 34.820 55.630 34.840 ;
        RECT 59.010 34.790 60.035 35.120 ;
        RECT 59.005 34.330 60.035 34.790 ;
        RECT 57.970 34.280 58.790 34.300 ;
        RECT 54.800 34.050 58.800 34.280 ;
        RECT 57.970 34.030 58.790 34.050 ;
        RECT 59.010 34.000 60.035 34.330 ;
        RECT 59.005 33.540 60.035 34.000 ;
        RECT 54.810 33.490 55.630 33.510 ;
        RECT 54.800 33.260 58.800 33.490 ;
        RECT 54.810 33.240 55.630 33.260 ;
        RECT 59.010 32.855 60.035 33.540 ;
        RECT 75.085 40.240 81.485 41.240 ;
        RECT 75.085 39.580 76.110 40.240 ;
        RECT 76.305 39.860 77.125 39.880 ;
        RECT 76.295 39.630 80.295 39.860 ;
        RECT 76.305 39.610 77.125 39.630 ;
        RECT 80.460 39.580 81.485 40.240 ;
        RECT 75.085 39.120 76.135 39.580 ;
        RECT 80.455 39.120 81.485 39.580 ;
        RECT 75.085 38.790 76.110 39.120 ;
        RECT 79.465 39.070 80.285 39.090 ;
        RECT 76.295 38.840 80.295 39.070 ;
        RECT 79.465 38.820 80.285 38.840 ;
        RECT 80.460 38.790 81.485 39.120 ;
        RECT 75.085 38.330 76.135 38.790 ;
        RECT 80.455 38.330 81.485 38.790 ;
        RECT 75.085 38.000 76.110 38.330 ;
        RECT 76.305 38.280 77.125 38.300 ;
        RECT 76.295 38.050 80.295 38.280 ;
        RECT 76.305 38.030 77.125 38.050 ;
        RECT 80.460 38.000 81.485 38.330 ;
        RECT 75.085 37.540 76.135 38.000 ;
        RECT 80.455 37.540 81.485 38.000 ;
        RECT 75.085 37.210 76.110 37.540 ;
        RECT 79.465 37.490 80.285 37.510 ;
        RECT 76.295 37.260 80.295 37.490 ;
        RECT 79.465 37.240 80.285 37.260 ;
        RECT 80.460 37.210 81.485 37.540 ;
        RECT 75.085 36.750 76.135 37.210 ;
        RECT 80.455 36.750 81.485 37.210 ;
        RECT 75.085 36.420 76.110 36.750 ;
        RECT 76.305 36.700 77.125 36.720 ;
        RECT 76.295 36.470 80.295 36.700 ;
        RECT 76.305 36.450 77.125 36.470 ;
        RECT 80.460 36.420 81.485 36.750 ;
        RECT 75.085 35.960 76.135 36.420 ;
        RECT 80.455 35.960 81.485 36.420 ;
        RECT 75.085 35.630 76.110 35.960 ;
        RECT 79.465 35.910 80.285 35.930 ;
        RECT 76.295 35.680 80.295 35.910 ;
        RECT 79.465 35.660 80.285 35.680 ;
        RECT 80.460 35.630 81.485 35.960 ;
        RECT 75.085 35.170 76.135 35.630 ;
        RECT 80.455 35.170 81.485 35.630 ;
        RECT 75.085 34.840 76.110 35.170 ;
        RECT 76.305 35.120 77.125 35.140 ;
        RECT 76.295 34.890 80.295 35.120 ;
        RECT 76.305 34.870 77.125 34.890 ;
        RECT 80.460 34.840 81.485 35.170 ;
        RECT 75.085 34.380 76.135 34.840 ;
        RECT 80.455 34.380 81.485 34.840 ;
        RECT 75.085 34.050 76.110 34.380 ;
        RECT 79.465 34.330 80.285 34.350 ;
        RECT 76.295 34.100 80.295 34.330 ;
        RECT 79.465 34.080 80.285 34.100 ;
        RECT 80.460 34.050 81.485 34.380 ;
        RECT 75.085 33.590 76.135 34.050 ;
        RECT 80.455 33.590 81.485 34.050 ;
        RECT 75.085 32.855 76.110 33.590 ;
        RECT 76.305 33.540 77.125 33.560 ;
        RECT 76.295 33.310 80.295 33.540 ;
        RECT 76.305 33.290 77.125 33.310 ;
        RECT 34.325 32.145 35.350 32.175 ;
        RECT 51.675 32.145 52.700 32.175 ;
        RECT 11.045 31.350 15.045 31.380 ;
        RECT 34.325 31.120 52.700 32.145 ;
        RECT 34.325 31.090 35.350 31.120 ;
        RECT 51.675 31.090 52.700 31.120 ;
        RECT 34.335 29.880 35.335 30.580 ;
        RECT 53.585 30.415 60.035 32.855 ;
        RECT 74.475 32.830 76.110 32.855 ;
        RECT 80.460 32.830 81.485 33.590 ;
        RECT 74.475 31.830 81.485 32.830 ;
        RECT 74.475 31.090 75.500 31.830 ;
        RECT 81.285 30.980 82.285 31.010 ;
        RECT 32.650 29.380 37.195 29.880 ;
        RECT 32.650 29.080 33.150 29.380 ;
        RECT 36.695 29.080 37.195 29.380 ;
        RECT 38.285 29.080 39.285 29.110 ;
        RECT 32.400 28.850 33.400 29.080 ;
        RECT 36.445 28.850 37.445 29.080 ;
        RECT 31.735 28.290 32.235 28.850 ;
        RECT 33.585 28.820 34.085 28.850 ;
        RECT 33.555 28.320 35.085 28.820 ;
        RECT 32.400 28.060 33.400 28.290 ;
        RECT 32.650 27.690 33.150 28.060 ;
        RECT 29.335 27.530 30.335 27.560 ;
        RECT 29.305 26.530 30.365 27.530 ;
        RECT 31.685 27.320 34.115 27.690 ;
        RECT 31.685 27.280 33.150 27.320 ;
        RECT 30.705 26.780 33.150 27.280 ;
        RECT 31.685 26.770 33.150 26.780 ;
        RECT 29.335 26.500 30.335 26.530 ;
        RECT 31.685 26.400 34.115 26.770 ;
        RECT 32.650 26.030 33.150 26.400 ;
        RECT 32.400 25.800 33.400 26.030 ;
        RECT 31.735 25.240 32.235 25.800 ;
        RECT 33.585 25.240 34.085 25.800 ;
        RECT 32.400 25.010 33.400 25.240 ;
        RECT 32.650 24.730 33.150 25.010 ;
        RECT 34.585 24.730 35.085 28.320 ;
        RECT 35.785 28.290 36.285 28.850 ;
        RECT 37.585 28.300 38.085 28.860 ;
        RECT 36.445 28.060 37.445 28.290 ;
        RECT 38.285 28.080 41.085 29.080 ;
        RECT 36.695 27.690 37.195 28.060 ;
        RECT 38.285 28.050 39.285 28.080 ;
        RECT 35.775 27.320 38.115 27.690 ;
        RECT 36.695 27.280 38.115 27.320 ;
        RECT 36.695 26.780 39.065 27.280 ;
        RECT 36.695 26.770 38.115 26.780 ;
        RECT 35.775 26.400 38.115 26.770 ;
        RECT 36.695 26.030 37.195 26.400 ;
        RECT 36.445 25.800 37.445 26.030 ;
        RECT 35.785 25.240 36.285 25.800 ;
        RECT 37.585 25.240 38.085 25.800 ;
        RECT 36.445 25.010 37.445 25.240 ;
        RECT 36.695 24.730 37.195 25.010 ;
        RECT 32.650 24.230 37.195 24.730 ;
        RECT 34.585 24.200 35.085 24.230 ;
        RECT 40.085 23.900 41.085 28.080 ;
        RECT 34.325 23.045 35.350 23.075 ;
        RECT 53.585 23.055 54.610 30.415 ;
        RECT 54.810 30.010 55.630 30.030 ;
        RECT 54.800 29.780 58.800 30.010 ;
        RECT 54.810 29.760 55.630 29.780 ;
        RECT 59.010 29.730 60.035 30.415 ;
        RECT 59.005 29.270 60.035 29.730 ;
        RECT 57.970 29.220 58.790 29.240 ;
        RECT 54.800 28.990 58.800 29.220 ;
        RECT 57.970 28.970 58.790 28.990 ;
        RECT 59.010 28.940 60.035 29.270 ;
        RECT 59.005 28.480 60.035 28.940 ;
        RECT 54.810 28.430 55.630 28.450 ;
        RECT 54.800 28.200 58.800 28.430 ;
        RECT 54.810 28.180 55.630 28.200 ;
        RECT 59.010 28.150 60.035 28.480 ;
        RECT 59.005 27.690 60.035 28.150 ;
        RECT 78.185 29.980 82.315 30.980 ;
        RECT 78.185 28.880 79.185 29.980 ;
        RECT 80.285 29.950 82.285 29.980 ;
        RECT 79.385 29.080 80.085 29.780 ;
        RECT 80.285 28.880 81.285 29.950 ;
        RECT 78.185 27.880 81.285 28.880 ;
        RECT 57.970 27.640 58.790 27.660 ;
        RECT 54.800 27.410 58.800 27.640 ;
        RECT 57.970 27.390 58.790 27.410 ;
        RECT 59.010 27.360 60.035 27.690 ;
        RECT 80.285 27.535 81.285 27.880 ;
        RECT 59.005 26.900 60.035 27.360 ;
        RECT 54.810 26.850 55.630 26.870 ;
        RECT 54.800 26.620 58.800 26.850 ;
        RECT 54.810 26.600 55.630 26.620 ;
        RECT 59.010 26.570 60.035 26.900 ;
        RECT 59.005 26.110 60.035 26.570 ;
        RECT 57.970 26.060 58.790 26.080 ;
        RECT 54.800 25.830 58.800 26.060 ;
        RECT 57.970 25.810 58.790 25.830 ;
        RECT 59.010 25.780 60.035 26.110 ;
        RECT 59.005 25.320 60.035 25.780 ;
        RECT 54.810 25.270 55.630 25.290 ;
        RECT 54.800 25.040 58.800 25.270 ;
        RECT 54.810 25.020 55.630 25.040 ;
        RECT 59.010 24.990 60.035 25.320 ;
        RECT 59.005 24.530 60.035 24.990 ;
        RECT 57.970 24.480 58.790 24.500 ;
        RECT 54.800 24.250 58.800 24.480 ;
        RECT 57.970 24.230 58.790 24.250 ;
        RECT 59.010 24.200 60.035 24.530 ;
        RECT 59.005 23.740 60.035 24.200 ;
        RECT 54.810 23.690 55.630 23.710 ;
        RECT 54.800 23.460 58.800 23.690 ;
        RECT 54.810 23.440 55.630 23.460 ;
        RECT 59.010 23.055 60.035 23.740 ;
        RECT 53.585 23.045 60.035 23.055 ;
        RECT 34.325 22.030 60.035 23.045 ;
        RECT 60.585 25.735 76.535 27.230 ;
        RECT 77.435 26.535 82.010 27.535 ;
        RECT 60.585 24.735 79.235 25.735 ;
        RECT 79.385 24.880 80.085 25.580 ;
        RECT 60.585 23.230 76.535 24.735 ;
        RECT 81.010 24.180 82.010 26.535 ;
        RECT 81.010 23.955 82.285 24.180 ;
        RECT 34.325 22.020 54.595 22.030 ;
        RECT 34.325 21.990 35.350 22.020 ;
        RECT 60.585 21.030 64.585 23.230 ;
        RECT 77.485 23.120 82.285 23.955 ;
        RECT 77.485 22.955 82.010 23.120 ;
        RECT 79.235 21.930 80.235 21.960 ;
        RECT 26.305 17.030 64.585 21.030 ;
        RECT 79.205 20.930 87.295 21.930 ;
        RECT 86.265 20.910 87.265 20.930 ;
        RECT 79.235 19.830 80.235 19.860 ;
        RECT 88.245 19.830 89.245 47.910 ;
        RECT 111.815 46.760 113.815 46.790 ;
        RECT 115.595 46.760 117.595 58.610 ;
        RECT 133.595 57.210 134.595 178.460 ;
        RECT 111.815 44.760 117.595 46.760 ;
        RECT 119.145 56.210 134.595 57.210 ;
        RECT 111.815 44.730 113.815 44.760 ;
        RECT 114.915 43.660 115.915 43.690 ;
        RECT 119.145 43.660 120.145 56.210 ;
        RECT 121.640 53.095 124.330 55.125 ;
        RECT 114.915 42.660 120.145 43.660 ;
        RECT 114.915 42.630 115.915 42.660 ;
        RECT 103.610 40.640 105.620 40.670 ;
        RECT 117.310 40.640 119.320 40.670 ;
        RECT 103.610 39.630 119.320 40.640 ;
        RECT 103.610 38.630 119.345 39.630 ;
        RECT 103.610 38.600 105.620 38.630 ;
        RECT 117.310 38.600 119.320 38.630 ;
        RECT 106.735 37.630 115.665 37.640 ;
        RECT 91.285 36.390 92.345 37.390 ;
        RECT 99.785 36.390 104.615 37.390 ;
        RECT 106.735 36.640 120.315 37.630 ;
        RECT 79.235 18.830 89.245 19.830 ;
        RECT 79.235 18.800 80.235 18.830 ;
        RECT 86.315 18.810 87.315 18.830 ;
        RECT 79.235 17.830 80.235 17.860 ;
        RECT 79.235 17.810 87.315 17.830 ;
        RECT 91.315 17.810 92.315 36.390 ;
        RECT 100.065 35.610 100.565 36.140 ;
        RECT 103.615 35.640 104.615 36.390 ;
        RECT 113.965 36.630 120.315 36.640 ;
        RECT 98.470 35.110 102.115 35.610 ;
        RECT 98.470 34.850 98.970 35.110 ;
        RECT 101.615 34.850 102.115 35.110 ;
        RECT 97.665 34.260 98.065 34.760 ;
        RECT 98.220 34.620 99.220 34.850 ;
        RECT 98.220 34.180 99.220 34.410 ;
        RECT 99.365 34.260 99.815 34.760 ;
        RECT 100.815 34.260 101.215 34.760 ;
        RECT 101.365 34.620 102.365 34.850 ;
        RECT 101.365 34.180 102.365 34.410 ;
        RECT 102.515 34.260 102.915 34.760 ;
        RECT 103.615 34.640 112.965 35.640 ;
        RECT 98.465 33.910 98.965 34.180 ;
        RECT 101.615 33.910 102.115 34.180 ;
        RECT 97.685 33.540 99.755 33.910 ;
        RECT 100.875 33.540 102.855 33.910 ;
        RECT 98.465 32.880 98.965 33.540 ;
        RECT 101.615 32.880 102.115 33.540 ;
        RECT 103.615 32.630 104.615 33.690 ;
        RECT 106.765 33.640 107.765 33.670 ;
        RECT 106.765 32.640 110.865 33.640 ;
        RECT 106.765 32.610 107.765 32.640 ;
        RECT 98.185 31.640 99.245 31.700 ;
        RECT 105.465 31.640 107.465 31.670 ;
        RECT 98.185 30.580 107.465 31.640 ;
        RECT 98.215 29.640 107.465 30.580 ;
        RECT 105.465 29.610 107.465 29.640 ;
        RECT 99.815 28.810 100.815 28.840 ;
        RECT 109.865 28.810 110.865 32.640 ;
        RECT 99.815 27.810 110.865 28.810 ;
        RECT 111.965 28.820 112.965 34.640 ;
        RECT 113.965 31.110 114.965 36.630 ;
        RECT 115.125 35.900 115.945 35.920 ;
        RECT 115.115 35.670 119.115 35.900 ;
        RECT 115.125 35.650 115.945 35.670 ;
        RECT 118.285 35.420 119.105 35.440 ;
        RECT 115.115 35.190 119.115 35.420 ;
        RECT 118.285 35.170 119.105 35.190 ;
        RECT 115.125 34.940 115.945 34.960 ;
        RECT 115.115 34.710 119.115 34.940 ;
        RECT 115.125 34.690 115.945 34.710 ;
        RECT 118.285 34.460 119.105 34.480 ;
        RECT 115.115 34.230 119.115 34.460 ;
        RECT 118.285 34.210 119.105 34.230 ;
        RECT 115.125 33.980 115.945 34.000 ;
        RECT 115.115 33.750 119.115 33.980 ;
        RECT 115.125 33.730 115.945 33.750 ;
        RECT 118.285 33.500 119.105 33.520 ;
        RECT 115.115 33.270 119.115 33.500 ;
        RECT 118.285 33.250 119.105 33.270 ;
        RECT 115.125 33.020 115.945 33.040 ;
        RECT 115.115 32.790 119.115 33.020 ;
        RECT 115.125 32.770 115.945 32.790 ;
        RECT 118.285 32.540 119.105 32.560 ;
        RECT 115.115 32.310 119.115 32.540 ;
        RECT 118.285 32.290 119.105 32.310 ;
        RECT 115.125 32.060 115.945 32.080 ;
        RECT 115.115 31.830 119.115 32.060 ;
        RECT 115.125 31.810 115.945 31.830 ;
        RECT 119.265 31.110 120.315 36.630 ;
        RECT 113.965 30.110 120.315 31.110 ;
        RECT 111.965 27.820 120.315 28.820 ;
        RECT 99.815 27.780 100.815 27.810 ;
        RECT 29.335 17.000 30.335 17.030 ;
        RECT 79.235 16.830 92.315 17.810 ;
        RECT 79.235 16.800 80.235 16.830 ;
        RECT 86.265 16.810 92.315 16.830 ;
        RECT 79.235 15.730 80.235 15.760 ;
        RECT 79.235 15.710 87.315 15.730 ;
        RECT 91.315 15.710 92.315 15.740 ;
        RECT 79.235 14.730 92.315 15.710 ;
        RECT 79.235 14.700 80.235 14.730 ;
        RECT 86.265 14.710 92.315 14.730 ;
        RECT 91.315 14.680 92.315 14.710 ;
        RECT 79.235 13.630 80.235 13.660 ;
        RECT 79.235 13.610 87.315 13.630 ;
        RECT 93.265 13.610 94.265 26.120 ;
        RECT 100.065 25.340 100.565 25.870 ;
        RECT 98.470 24.840 102.115 25.340 ;
        RECT 98.470 24.580 98.970 24.840 ;
        RECT 101.615 24.580 102.115 24.840 ;
        RECT 97.665 23.990 98.065 24.490 ;
        RECT 98.220 24.350 99.220 24.580 ;
        RECT 98.220 23.910 99.220 24.140 ;
        RECT 99.365 23.990 99.815 24.490 ;
        RECT 100.815 23.990 101.215 24.490 ;
        RECT 101.365 24.350 102.365 24.580 ;
        RECT 101.365 23.910 102.365 24.140 ;
        RECT 102.515 23.990 102.915 24.490 ;
        RECT 98.465 23.640 98.965 23.910 ;
        RECT 101.615 23.640 102.115 23.910 ;
        RECT 97.685 23.270 99.755 23.640 ;
        RECT 100.875 23.270 102.855 23.640 ;
        RECT 98.465 22.610 98.965 23.270 ;
        RECT 101.615 22.610 102.115 23.270 ;
        RECT 104.465 22.340 105.465 27.810 ;
        RECT 105.680 27.130 106.500 27.150 ;
        RECT 105.670 26.900 109.670 27.130 ;
        RECT 105.680 26.880 106.500 26.900 ;
        RECT 108.840 26.650 109.660 26.670 ;
        RECT 105.670 26.420 109.670 26.650 ;
        RECT 108.840 26.400 109.660 26.420 ;
        RECT 105.680 26.170 106.500 26.190 ;
        RECT 105.670 25.940 109.670 26.170 ;
        RECT 105.680 25.920 106.500 25.940 ;
        RECT 108.840 25.690 109.660 25.710 ;
        RECT 105.670 25.460 109.670 25.690 ;
        RECT 108.840 25.440 109.660 25.460 ;
        RECT 105.680 25.210 106.500 25.230 ;
        RECT 105.670 24.980 109.670 25.210 ;
        RECT 105.680 24.960 106.500 24.980 ;
        RECT 108.840 24.730 109.660 24.750 ;
        RECT 105.670 24.500 109.670 24.730 ;
        RECT 108.840 24.480 109.660 24.500 ;
        RECT 105.680 24.250 106.500 24.270 ;
        RECT 105.670 24.020 109.670 24.250 ;
        RECT 105.680 24.000 106.500 24.020 ;
        RECT 108.840 23.770 109.660 23.790 ;
        RECT 105.670 23.540 109.670 23.770 ;
        RECT 108.840 23.520 109.660 23.540 ;
        RECT 105.680 23.290 106.500 23.310 ;
        RECT 105.670 23.060 109.670 23.290 ;
        RECT 105.680 23.040 106.500 23.060 ;
        RECT 109.865 22.340 110.865 27.810 ;
        RECT 104.465 21.340 110.865 22.340 ;
        RECT 113.965 22.350 114.965 27.820 ;
        RECT 115.125 27.140 115.945 27.160 ;
        RECT 115.115 26.910 119.115 27.140 ;
        RECT 115.125 26.890 115.945 26.910 ;
        RECT 118.285 26.660 119.105 26.680 ;
        RECT 115.115 26.430 119.115 26.660 ;
        RECT 119.315 26.450 120.315 27.820 ;
        RECT 118.285 26.410 119.105 26.430 ;
        RECT 115.125 26.180 115.945 26.200 ;
        RECT 115.115 25.950 119.115 26.180 ;
        RECT 119.275 26.160 120.315 26.450 ;
        RECT 115.125 25.930 115.945 25.950 ;
        RECT 118.285 25.700 119.105 25.720 ;
        RECT 115.115 25.470 119.115 25.700 ;
        RECT 119.315 25.490 120.315 26.160 ;
        RECT 118.285 25.450 119.105 25.470 ;
        RECT 115.125 25.220 115.945 25.240 ;
        RECT 115.115 24.990 119.115 25.220 ;
        RECT 119.275 25.200 120.315 25.490 ;
        RECT 115.125 24.970 115.945 24.990 ;
        RECT 118.285 24.740 119.105 24.760 ;
        RECT 115.115 24.510 119.115 24.740 ;
        RECT 119.315 24.530 120.315 25.200 ;
        RECT 118.285 24.490 119.105 24.510 ;
        RECT 115.125 24.260 115.945 24.280 ;
        RECT 115.115 24.030 119.115 24.260 ;
        RECT 119.275 24.240 120.315 24.530 ;
        RECT 115.125 24.010 115.945 24.030 ;
        RECT 118.285 23.780 119.105 23.800 ;
        RECT 115.115 23.550 119.115 23.780 ;
        RECT 119.315 23.570 120.315 24.240 ;
        RECT 118.285 23.530 119.105 23.550 ;
        RECT 115.125 23.300 115.945 23.320 ;
        RECT 115.115 23.070 119.115 23.300 ;
        RECT 119.275 23.280 120.315 23.570 ;
        RECT 115.125 23.050 115.945 23.070 ;
        RECT 119.315 22.350 120.315 23.280 ;
        RECT 113.965 21.350 120.315 22.350 ;
        RECT 119.315 21.340 120.315 21.350 ;
        RECT 98.155 20.390 99.275 20.420 ;
        RECT 105.465 20.390 107.465 20.420 ;
        RECT 98.155 19.360 107.465 20.390 ;
        RECT 98.165 18.390 107.465 19.360 ;
        RECT 105.465 18.360 107.465 18.390 ;
        RECT 79.235 12.630 94.265 13.610 ;
        RECT 105.450 15.175 107.480 15.205 ;
        RECT 122.300 15.175 124.330 53.095 ;
        RECT 105.450 13.145 124.330 15.175 ;
        RECT 105.450 13.115 107.480 13.145 ;
        RECT 79.235 12.600 80.235 12.630 ;
        RECT 86.315 12.610 94.265 12.630 ;
        RECT 79.235 11.480 80.235 11.510 ;
        RECT 79.235 11.460 87.315 11.480 ;
        RECT 93.265 11.460 94.265 11.490 ;
        RECT 79.235 10.480 94.265 11.460 ;
        RECT 79.235 10.450 80.235 10.480 ;
        RECT 86.265 10.460 94.265 10.480 ;
        RECT 93.265 10.430 94.265 10.460 ;
        RECT 122.570 5.050 126.690 9.110 ;
        RECT 122.600 5.020 126.660 5.050 ;
        RECT 0.000 0.000 1.000 1.000 ;
        RECT 144.360 0.000 145.360 1.000 ;
      LAYER met2 ;
        RECT 17.600 198.395 18.100 207.880 ;
        RECT 18.350 201.920 18.850 207.880 ;
        RECT 19.655 203.150 19.935 203.205 ;
        RECT 21.155 203.150 21.435 203.205 ;
        RECT 22.655 203.150 22.935 203.205 ;
        RECT 24.155 203.150 24.435 203.205 ;
        RECT 25.655 203.150 25.935 203.205 ;
        RECT 27.155 203.150 27.435 203.205 ;
        RECT 28.655 203.150 28.935 203.205 ;
        RECT 30.155 203.150 30.435 203.205 ;
        RECT 19.635 202.890 19.955 203.150 ;
        RECT 21.135 202.890 21.455 203.150 ;
        RECT 22.635 202.890 22.955 203.150 ;
        RECT 24.135 202.890 24.455 203.150 ;
        RECT 25.635 202.890 25.955 203.150 ;
        RECT 27.135 202.890 27.455 203.150 ;
        RECT 28.635 202.890 28.955 203.150 ;
        RECT 30.135 202.890 30.455 203.150 ;
        RECT 19.655 202.835 19.935 202.890 ;
        RECT 21.155 202.835 21.435 202.890 ;
        RECT 22.655 202.835 22.935 202.890 ;
        RECT 24.155 202.835 24.435 202.890 ;
        RECT 25.655 202.835 25.935 202.890 ;
        RECT 27.155 202.835 27.435 202.890 ;
        RECT 28.655 202.835 28.935 202.890 ;
        RECT 30.155 202.835 30.435 202.890 ;
        RECT 30.830 201.920 31.330 207.880 ;
        RECT 18.350 201.420 19.350 201.920 ;
        RECT 18.850 200.395 19.350 201.420 ;
        RECT 30.330 201.420 31.330 201.920 ;
        RECT 30.330 200.395 30.830 201.420 ;
        RECT 18.580 199.445 19.620 200.395 ;
        RECT 30.060 199.445 31.100 200.395 ;
        RECT 31.580 198.395 32.080 207.880 ;
        RECT 39.680 198.395 40.180 207.880 ;
        RECT 40.430 201.920 40.930 207.880 ;
        RECT 41.735 203.150 42.015 203.205 ;
        RECT 43.235 203.150 43.515 203.205 ;
        RECT 44.735 203.150 45.015 203.205 ;
        RECT 46.235 203.150 46.515 203.205 ;
        RECT 47.735 203.150 48.015 203.205 ;
        RECT 49.235 203.150 49.515 203.205 ;
        RECT 50.735 203.150 51.015 203.205 ;
        RECT 52.235 203.150 52.515 203.205 ;
        RECT 41.715 202.890 42.035 203.150 ;
        RECT 43.215 202.890 43.535 203.150 ;
        RECT 44.715 202.890 45.035 203.150 ;
        RECT 46.215 202.890 46.535 203.150 ;
        RECT 47.715 202.890 48.035 203.150 ;
        RECT 49.215 202.890 49.535 203.150 ;
        RECT 50.715 202.890 51.035 203.150 ;
        RECT 52.215 202.890 52.535 203.150 ;
        RECT 41.735 202.835 42.015 202.890 ;
        RECT 43.235 202.835 43.515 202.890 ;
        RECT 44.735 202.835 45.015 202.890 ;
        RECT 46.235 202.835 46.515 202.890 ;
        RECT 47.735 202.835 48.015 202.890 ;
        RECT 49.235 202.835 49.515 202.890 ;
        RECT 50.735 202.835 51.015 202.890 ;
        RECT 52.235 202.835 52.515 202.890 ;
        RECT 52.910 201.920 53.410 207.880 ;
        RECT 40.430 201.420 41.430 201.920 ;
        RECT 40.930 200.395 41.430 201.420 ;
        RECT 52.410 201.420 53.410 201.920 ;
        RECT 52.410 200.395 52.910 201.420 ;
        RECT 40.660 199.445 41.700 200.395 ;
        RECT 52.140 199.445 53.180 200.395 ;
        RECT 53.660 198.395 54.160 207.880 ;
        RECT 61.760 198.395 62.260 207.880 ;
        RECT 62.510 201.920 63.010 207.880 ;
        RECT 63.815 203.150 64.095 203.205 ;
        RECT 65.315 203.150 65.595 203.205 ;
        RECT 66.815 203.150 67.095 203.205 ;
        RECT 68.315 203.150 68.595 203.205 ;
        RECT 69.815 203.150 70.095 203.205 ;
        RECT 71.315 203.150 71.595 203.205 ;
        RECT 72.815 203.150 73.095 203.205 ;
        RECT 74.315 203.150 74.595 203.205 ;
        RECT 63.795 202.890 64.115 203.150 ;
        RECT 65.295 202.890 65.615 203.150 ;
        RECT 66.795 202.890 67.115 203.150 ;
        RECT 68.295 202.890 68.615 203.150 ;
        RECT 69.795 202.890 70.115 203.150 ;
        RECT 71.295 202.890 71.615 203.150 ;
        RECT 72.795 202.890 73.115 203.150 ;
        RECT 74.295 202.890 74.615 203.150 ;
        RECT 63.815 202.835 64.095 202.890 ;
        RECT 65.315 202.835 65.595 202.890 ;
        RECT 66.815 202.835 67.095 202.890 ;
        RECT 68.315 202.835 68.595 202.890 ;
        RECT 69.815 202.835 70.095 202.890 ;
        RECT 71.315 202.835 71.595 202.890 ;
        RECT 72.815 202.835 73.095 202.890 ;
        RECT 74.315 202.835 74.595 202.890 ;
        RECT 74.990 201.920 75.490 207.880 ;
        RECT 62.510 201.420 63.510 201.920 ;
        RECT 63.010 200.395 63.510 201.420 ;
        RECT 74.490 201.420 75.490 201.920 ;
        RECT 74.490 200.395 74.990 201.420 ;
        RECT 62.740 199.445 63.780 200.395 ;
        RECT 74.220 199.445 75.260 200.395 ;
        RECT 75.740 198.395 76.240 207.880 ;
        RECT 17.330 197.445 18.370 198.395 ;
        RECT 31.310 197.445 32.350 198.395 ;
        RECT 39.410 197.445 40.450 198.395 ;
        RECT 53.390 197.445 54.430 198.395 ;
        RECT 61.490 197.445 62.530 198.395 ;
        RECT 75.470 197.445 76.510 198.395 ;
        RECT 132.295 182.510 136.295 182.565 ;
        RECT 132.250 179.510 136.340 182.510 ;
        RECT 98.245 178.560 136.340 179.510 ;
        RECT 98.245 178.510 136.295 178.560 ;
        RECT 132.295 178.465 136.295 178.510 ;
        RECT 121.250 177.460 121.840 177.960 ;
        RECT 100.195 176.905 100.690 176.935 ;
        RECT 20.545 176.660 20.845 176.760 ;
        RECT 12.295 175.910 81.995 176.660 ;
        RECT 95.545 176.410 100.690 176.905 ;
        RECT 121.295 176.660 121.795 177.460 ;
        RECT 95.545 175.910 96.045 176.410 ;
        RECT 100.195 176.380 100.690 176.410 ;
        RECT 115.495 175.910 132.225 176.660 ;
        RECT 12.295 175.410 96.045 175.910 ;
        RECT 96.765 175.410 132.225 175.910 ;
        RECT 12.295 174.660 81.995 175.410 ;
        RECT 12.295 62.660 14.295 174.660 ;
        RECT 19.995 170.110 21.995 174.660 ;
        RECT 20.295 169.060 20.795 170.110 ;
        RECT 20.250 168.560 20.840 169.060 ;
        RECT 89.195 166.580 89.695 175.410 ;
        RECT 92.920 174.335 93.415 175.410 ;
        RECT 94.245 174.310 94.745 175.410 ;
        RECT 96.045 174.390 98.325 174.890 ;
        RECT 99.115 174.390 101.345 174.890 ;
        RECT 94.245 173.810 95.325 174.310 ;
        RECT 94.245 171.710 94.745 173.810 ;
        RECT 95.165 170.910 95.665 173.060 ;
        RECT 97.365 170.910 97.865 173.060 ;
        RECT 99.615 170.910 100.115 173.060 ;
        RECT 101.715 170.910 102.215 173.060 ;
        RECT 102.545 172.260 103.045 175.410 ;
        RECT 103.845 174.330 104.345 175.410 ;
        RECT 115.495 174.660 132.225 175.410 ;
        RECT 102.515 171.760 103.075 172.260 ;
        RECT 95.165 170.410 102.215 170.910 ;
        RECT 98.495 160.710 98.995 170.410 ;
        RECT 98.245 160.010 99.245 160.710 ;
        RECT 98.245 159.010 123.340 160.010 ;
        RECT 19.450 150.160 69.395 151.160 ;
        RECT 16.145 138.910 20.145 138.940 ;
        RECT 45.995 138.910 49.995 142.860 ;
        RECT 16.145 134.910 49.995 138.910 ;
        RECT 16.145 134.880 20.545 134.910 ;
        RECT 16.545 134.460 20.545 134.880 ;
        RECT 16.500 130.460 20.590 134.460 ;
        RECT 45.995 129.460 49.995 134.910 ;
        RECT 68.395 140.360 69.395 150.160 ;
        RECT 68.395 139.360 119.425 140.360 ;
        RECT 59.945 133.210 60.945 134.510 ;
        RECT 68.395 133.210 69.395 139.360 ;
        RECT 121.645 138.910 134.495 142.910 ;
        RECT 121.645 138.260 125.645 138.910 ;
        RECT 79.795 134.260 125.690 138.260 ;
        RECT 59.945 132.210 81.365 133.210 ;
        RECT 59.945 130.460 60.945 132.210 ;
        RECT 45.995 125.460 77.575 129.460 ;
        RECT 80.365 129.160 81.365 132.210 ;
        RECT 81.845 126.410 83.645 134.260 ;
        RECT 121.645 126.915 122.645 128.005 ;
        RECT 85.865 124.860 128.395 125.860 ;
        RECT 121.800 123.760 122.800 123.805 ;
        RECT 37.765 117.460 60.945 118.460 ;
        RECT 16.600 112.410 49.995 116.410 ;
        RECT 45.995 79.410 49.995 112.410 ;
        RECT 59.945 112.560 60.945 117.460 ;
        RECT 90.745 115.410 95.945 119.210 ;
        RECT 99.845 117.810 100.845 121.310 ;
        RECT 96.815 116.810 100.845 117.810 ;
        RECT 99.845 116.460 100.845 116.810 ;
        RECT 103.145 119.760 125.745 123.760 ;
        RECT 103.145 115.410 107.145 119.760 ;
        RECT 59.945 111.560 63.995 112.560 ;
        RECT 59.945 107.460 60.945 110.510 ;
        RECT 62.995 110.310 63.995 111.560 ;
        RECT 84.045 112.360 85.045 115.410 ;
        RECT 90.745 115.210 107.145 115.410 ;
        RECT 84.045 111.360 90.895 112.360 ;
        RECT 91.945 111.410 107.145 115.210 ;
        RECT 94.945 111.360 95.945 111.410 ;
        RECT 89.895 110.360 90.895 111.360 ;
        RECT 62.995 109.310 85.045 110.310 ;
        RECT 89.895 109.360 95.945 110.360 ;
        RECT 42.845 75.410 49.995 79.410 ;
        RECT 54.395 106.460 63.995 107.460 ;
        RECT 51.145 77.625 53.395 77.655 ;
        RECT 54.395 77.625 55.395 106.460 ;
        RECT 59.945 80.210 60.945 105.410 ;
        RECT 62.995 83.110 63.995 106.460 ;
        RECT 84.045 84.160 85.045 109.310 ;
        RECT 94.945 84.160 95.945 109.360 ;
        RECT 100.145 105.610 104.145 111.410 ;
        RECT 121.700 105.610 122.700 105.660 ;
        RECT 100.145 104.610 122.700 105.610 ;
        RECT 100.145 85.060 104.145 104.610 ;
        RECT 121.700 104.565 122.700 104.610 ;
        RECT 121.700 96.710 122.700 96.740 ;
        RECT 121.655 95.710 122.745 96.710 ;
        RECT 121.700 95.680 122.700 95.710 ;
        RECT 121.700 87.460 122.700 87.490 ;
        RECT 121.655 86.460 122.745 87.460 ;
        RECT 121.700 86.430 122.700 86.460 ;
        RECT 100.145 83.110 123.340 85.060 ;
        RECT 62.995 82.110 85.045 83.110 ;
        RECT 59.945 79.210 65.545 80.210 ;
        RECT 51.145 76.625 55.395 77.625 ;
        RECT 64.545 77.655 65.545 79.210 ;
        RECT 84.045 80.060 85.045 82.110 ;
        RECT 91.945 83.060 123.340 83.110 ;
        RECT 84.045 79.060 90.195 80.060 ;
        RECT 64.545 77.625 66.745 77.655 ;
        RECT 84.045 77.625 85.045 78.060 ;
        RECT 64.545 76.625 85.045 77.625 ;
        RECT 51.145 76.595 53.395 76.625 ;
        RECT 64.545 76.595 66.745 76.625 ;
        RECT 38.045 64.580 42.045 68.640 ;
        RECT 45.995 68.610 49.995 75.410 ;
        RECT 72.815 74.710 73.875 75.710 ;
        RECT 72.845 70.360 73.845 74.710 ;
        RECT 72.845 69.360 82.845 70.360 ;
        RECT 45.965 64.610 50.025 68.610 ;
        RECT 55.940 64.610 60.030 68.610 ;
        RECT 62.255 64.610 66.315 68.610 ;
        RECT 68.635 64.610 72.695 68.610 ;
        RECT 55.985 63.160 59.985 64.610 ;
        RECT 62.285 63.160 66.285 64.610 ;
        RECT 12.265 60.660 14.325 62.660 ;
        RECT 55.965 59.160 59.985 63.160 ;
        RECT 62.265 59.160 66.285 63.160 ;
        RECT 68.665 63.130 72.665 64.610 ;
        RECT 75.115 63.130 79.115 68.655 ;
        RECT 81.845 67.510 82.845 69.360 ;
        RECT 84.045 69.560 85.045 76.625 ;
        RECT 89.195 70.880 90.195 79.060 ;
        RECT 91.945 79.110 104.145 83.060 ;
        RECT 121.675 82.210 122.675 82.240 ;
        RECT 121.630 81.210 122.720 82.210 ;
        RECT 121.675 81.180 122.675 81.210 ;
        RECT 91.945 76.360 95.945 79.110 ;
        RECT 94.945 71.260 95.945 73.890 ;
        RECT 84.045 68.560 90.245 69.560 ;
        RECT 100.145 68.610 104.145 79.110 ;
        RECT 127.395 78.560 128.395 124.860 ;
        RECT 121.655 77.560 128.395 78.560 ;
        RECT 106.115 76.560 122.700 77.560 ;
        RECT 130.495 71.110 134.495 138.910 ;
        RECT 81.845 66.510 88.195 67.510 ;
        RECT 68.665 59.160 72.685 63.130 ;
        RECT 75.115 59.160 79.135 63.130 ;
        RECT 40.055 55.130 44.115 59.130 ;
        RECT 55.985 55.880 59.985 59.160 ;
        RECT 16.765 46.760 20.765 46.790 ;
        RECT 16.720 42.760 20.810 46.760 ;
        RECT 26.315 44.630 30.335 47.630 ;
        RECT 34.335 46.730 35.335 52.120 ;
        RECT 33.585 45.920 34.085 45.950 ;
        RECT 31.705 45.420 34.115 45.920 ;
        RECT 33.585 45.390 34.085 45.420 ;
        RECT 26.315 43.630 31.485 44.630 ;
        RECT 16.765 42.730 20.765 42.760 ;
        RECT 26.335 38.680 30.335 43.630 ;
        RECT 33.585 42.870 34.085 42.880 ;
        RECT 34.585 42.870 35.085 46.730 ;
        RECT 38.255 45.930 39.315 46.180 ;
        RECT 35.920 45.920 39.315 45.930 ;
        RECT 35.755 45.420 39.315 45.920 ;
        RECT 38.255 45.180 39.315 45.420 ;
        RECT 40.085 44.630 44.085 55.130 ;
        RECT 48.625 54.240 49.650 54.280 ;
        RECT 48.595 53.215 49.680 54.240 ;
        RECT 38.285 43.630 44.085 44.630 ;
        RECT 38.255 42.870 39.345 43.130 ;
        RECT 31.705 42.370 35.085 42.870 ;
        RECT 35.755 42.370 39.345 42.870 ;
        RECT 38.255 42.130 39.345 42.370 ;
        RECT 34.555 41.580 35.115 41.830 ;
        RECT 34.335 41.180 35.335 41.580 ;
        RECT 34.305 40.180 35.365 41.180 ;
        RECT 11.045 35.410 15.045 35.425 ;
        RECT 11.045 35.380 15.075 35.410 ;
        RECT 11.000 31.380 15.120 35.380 ;
        RECT 11.045 31.350 15.075 31.380 ;
        RECT 11.045 31.335 15.045 31.350 ;
        RECT 16.765 14.430 20.765 38.105 ;
        RECT 26.305 34.680 30.365 38.680 ;
        RECT 26.335 27.530 30.335 34.680 ;
        RECT 34.295 31.120 35.380 32.145 ;
        RECT 34.325 30.320 35.350 31.120 ;
        RECT 34.335 29.630 35.335 30.320 ;
        RECT 33.585 28.820 34.085 28.850 ;
        RECT 31.705 28.320 34.115 28.820 ;
        RECT 33.585 28.290 34.085 28.320 ;
        RECT 26.335 26.530 31.485 27.530 ;
        RECT 26.335 18.030 30.335 26.530 ;
        RECT 33.585 25.770 34.085 25.780 ;
        RECT 34.585 25.770 35.085 29.630 ;
        RECT 38.255 28.830 39.315 29.080 ;
        RECT 35.920 28.820 39.315 28.830 ;
        RECT 35.755 28.320 39.315 28.820 ;
        RECT 38.255 28.080 39.315 28.320 ;
        RECT 40.085 27.530 44.085 43.630 ;
        RECT 38.285 26.530 44.085 27.530 ;
        RECT 38.285 25.770 39.285 26.030 ;
        RECT 31.705 25.270 35.085 25.770 ;
        RECT 35.755 25.270 39.285 25.770 ;
        RECT 34.555 24.480 35.115 24.730 ;
        RECT 34.335 24.240 35.335 24.480 ;
        RECT 34.325 23.045 35.350 24.240 ;
        RECT 34.295 22.020 35.380 23.045 ;
        RECT 26.335 17.030 30.365 18.030 ;
        RECT 26.335 14.430 30.335 17.030 ;
        RECT 16.765 10.430 30.380 14.430 ;
        RECT 38.285 11.480 39.285 25.270 ;
        RECT 40.055 23.930 41.115 24.930 ;
        RECT 40.085 13.630 41.085 23.930 ;
        RECT 44.885 15.730 45.885 43.160 ;
        RECT 46.685 17.830 47.685 46.210 ;
        RECT 48.625 40.995 49.650 53.215 ;
        RECT 55.985 51.880 60.485 55.880 ;
        RECT 48.595 39.970 49.680 40.995 ;
        RECT 51.635 38.710 55.635 50.740 ;
        RECT 57.985 44.030 60.485 51.880 ;
        RECT 62.285 40.340 66.285 59.160 ;
        RECT 48.635 34.680 55.635 38.710 ;
        RECT 48.635 34.650 51.535 34.680 ;
        RECT 49.755 32.880 50.815 33.880 ;
        RECT 52.635 33.180 55.635 34.680 ;
        RECT 57.985 36.330 66.285 40.340 ;
        RECT 68.685 40.280 72.685 59.160 ;
        RECT 75.135 55.880 79.135 59.160 ;
        RECT 80.435 59.130 84.435 59.160 ;
        RECT 74.735 51.880 79.135 55.880 ;
        RECT 80.405 55.130 84.465 59.130 ;
        RECT 74.735 44.230 77.135 51.880 ;
        RECT 80.435 50.990 84.435 55.130 ;
        RECT 74.785 40.280 77.135 40.390 ;
        RECT 57.985 33.180 61.235 36.330 ;
        RECT 68.685 36.280 77.135 40.280 ;
        RECT 74.785 33.230 77.135 36.280 ;
        RECT 79.485 37.230 84.435 50.990 ;
        RECT 79.485 33.230 85.285 37.230 ;
        RECT 49.785 30.080 50.785 32.880 ;
        RECT 51.645 31.120 75.530 32.145 ;
        RECT 81.285 30.980 85.285 33.230 ;
        RECT 54.635 30.080 55.635 30.090 ;
        RECT 49.785 29.080 55.635 30.080 ;
        RECT 54.635 23.380 55.635 29.080 ;
        RECT 57.985 19.830 58.985 30.090 ;
        RECT 81.255 29.980 85.285 30.980 ;
        RECT 79.235 25.735 80.235 29.930 ;
        RECT 79.230 24.735 80.235 25.735 ;
        RECT 79.235 21.930 80.235 24.735 ;
        RECT 81.285 24.150 85.285 29.980 ;
        RECT 81.255 23.150 85.285 24.150 ;
        RECT 79.205 20.930 80.265 21.930 ;
        RECT 79.235 20.900 80.235 20.930 ;
        RECT 57.985 18.830 80.265 19.830 ;
        RECT 81.285 18.430 85.285 23.150 ;
        RECT 87.195 21.960 88.195 66.510 ;
        RECT 86.265 20.900 88.195 21.960 ;
        RECT 46.685 16.830 80.265 17.830 ;
        RECT 44.885 14.730 80.265 15.730 ;
        RECT 81.240 14.430 85.330 18.430 ;
        RECT 81.265 14.410 85.265 14.430 ;
        RECT 81.285 14.385 85.235 14.410 ;
        RECT 40.085 12.630 80.265 13.630 ;
        RECT 38.285 10.480 80.265 11.480 ;
        RECT 26.315 10.410 30.315 10.430 ;
        RECT 87.195 9.060 88.195 20.900 ;
        RECT 89.245 13.610 90.245 68.560 ;
        RECT 100.115 64.610 104.175 68.610 ;
        RECT 107.995 68.585 134.495 71.110 ;
        RECT 107.975 67.110 134.495 68.585 ;
        RECT 107.975 64.635 112.015 67.110 ;
        RECT 107.995 64.610 111.995 64.635 ;
        RECT 108.835 60.660 110.895 62.660 ;
        RECT 117.015 61.960 123.715 63.960 ;
        RECT 103.580 38.630 105.650 40.640 ;
        RECT 91.315 37.390 92.315 37.420 ;
        RECT 99.815 37.390 100.815 37.420 ;
        RECT 91.315 36.390 100.815 37.390 ;
        RECT 91.315 36.360 92.315 36.390 ;
        RECT 99.815 35.360 100.815 36.390 ;
        RECT 97.650 34.760 102.890 34.765 ;
        RECT 97.650 34.265 102.915 34.760 ;
        RECT 100.065 33.660 100.565 34.265 ;
        RECT 102.515 34.260 102.915 34.265 ;
        RECT 103.610 33.660 105.620 38.630 ;
        RECT 98.215 31.590 99.215 33.660 ;
        RECT 98.185 30.590 99.245 31.590 ;
        RECT 99.815 28.810 100.815 33.660 ;
        RECT 101.365 32.660 105.620 33.660 ;
        RECT 106.765 33.640 107.765 37.670 ;
        RECT 101.365 28.810 102.365 32.660 ;
        RECT 103.610 32.635 105.620 32.660 ;
        RECT 106.735 32.640 107.795 33.640 ;
        RECT 105.435 29.640 107.495 31.640 ;
        RECT 99.785 28.790 100.845 28.810 ;
        RECT 91.315 27.810 100.845 28.790 ;
        RECT 101.365 27.810 104.615 28.810 ;
        RECT 91.315 27.790 100.815 27.810 ;
        RECT 91.315 15.710 92.315 27.790 ;
        RECT 93.235 25.090 100.815 26.090 ;
        RECT 97.650 24.490 102.890 24.495 ;
        RECT 97.650 23.995 102.915 24.490 ;
        RECT 100.065 23.390 100.565 23.995 ;
        RECT 102.515 23.990 102.915 23.995 ;
        RECT 103.615 23.390 104.615 27.810 ;
        RECT 98.215 22.390 99.215 23.390 ;
        RECT 99.815 21.390 100.815 23.390 ;
        RECT 101.365 22.390 104.615 23.390 ;
        RECT 93.265 20.390 100.815 21.390 ;
        RECT 105.465 20.420 107.465 29.640 ;
        RECT 108.865 22.940 110.865 60.660 ;
        RECT 117.015 50.610 119.015 61.960 ;
        RECT 121.640 55.155 123.670 55.185 ;
        RECT 121.640 55.125 123.700 55.155 ;
        RECT 121.625 53.095 123.745 55.125 ;
        RECT 121.640 53.065 123.700 53.095 ;
        RECT 121.640 53.035 123.670 53.065 ;
        RECT 117.015 48.610 124.315 50.610 ;
        RECT 111.785 44.760 113.845 46.760 ;
        RECT 111.815 27.240 113.815 44.760 ;
        RECT 114.885 42.660 115.945 43.660 ;
        RECT 114.915 31.760 115.915 42.660 ;
        RECT 117.285 38.640 119.345 40.640 ;
        RECT 111.815 25.240 115.915 27.240 ;
        RECT 113.915 22.940 115.915 25.240 ;
        RECT 105.435 20.390 107.465 20.420 ;
        RECT 91.270 14.710 92.360 15.710 ;
        RECT 89.245 12.610 92.295 13.610 ;
        RECT 91.295 9.510 92.295 12.610 ;
        RECT 93.265 11.460 94.265 20.390 ;
        RECT 105.435 18.360 107.495 20.390 ;
        RECT 117.315 19.360 119.315 38.640 ;
        RECT 122.315 19.360 124.315 48.610 ;
        RECT 105.435 18.025 107.465 18.360 ;
        RECT 105.435 15.560 107.480 18.025 ;
        RECT 117.315 17.360 124.315 19.360 ;
        RECT 108.870 15.710 109.820 15.730 ;
        RECT 105.450 15.175 107.480 15.560 ;
        RECT 105.420 13.145 107.510 15.175 ;
        RECT 108.845 14.710 121.990 15.710 ;
        RECT 108.870 14.690 109.820 14.710 ;
        RECT 108.870 11.460 109.820 11.480 ;
        RECT 93.220 10.460 94.310 11.460 ;
        RECT 108.845 10.460 122.040 11.460 ;
        RECT 108.870 10.440 109.820 10.460 ;
        RECT 84.150 5.060 88.240 9.060 ;
        RECT 91.295 8.510 103.145 9.510 ;
        RECT 122.600 9.050 126.660 9.095 ;
        RECT 99.145 5.015 103.145 8.510 ;
        RECT 122.570 5.050 126.690 9.050 ;
        RECT 122.600 5.005 126.660 5.050 ;
        RECT 122.650 5.000 126.650 5.005 ;
      LAYER met3 ;
        RECT 14.990 224.750 15.370 225.070 ;
        RECT 17.750 224.750 18.130 225.070 ;
        RECT 20.510 224.750 20.890 225.070 ;
        RECT 23.270 224.750 23.650 225.070 ;
        RECT 26.030 224.750 26.410 225.070 ;
        RECT 28.790 224.750 29.170 225.070 ;
        RECT 31.550 224.750 31.930 225.070 ;
        RECT 34.310 224.750 34.690 225.070 ;
        RECT 37.070 224.750 37.450 225.070 ;
        RECT 39.830 224.750 40.210 225.070 ;
        RECT 42.590 224.750 42.970 225.070 ;
        RECT 45.350 224.750 45.730 225.070 ;
        RECT 48.110 224.750 48.490 225.070 ;
        RECT 50.870 224.750 51.250 225.070 ;
        RECT 53.630 224.750 54.010 225.070 ;
        RECT 56.390 224.750 56.770 225.070 ;
        RECT 59.150 224.750 59.530 225.070 ;
        RECT 61.910 224.750 62.290 225.070 ;
        RECT 64.670 224.750 65.050 225.070 ;
        RECT 67.430 224.750 67.810 225.070 ;
        RECT 70.190 224.750 70.570 225.070 ;
        RECT 72.950 224.750 73.330 225.070 ;
        RECT 75.710 224.750 76.090 225.070 ;
        RECT 78.470 224.750 78.850 225.070 ;
        RECT 119.870 224.760 120.250 225.080 ;
        RECT 15.030 208.880 15.330 224.750 ;
        RECT 17.790 209.880 18.090 224.750 ;
        RECT 20.550 210.880 20.850 224.750 ;
        RECT 23.310 211.880 23.610 224.750 ;
        RECT 26.070 211.880 26.370 224.750 ;
        RECT 23.310 211.580 24.445 211.880 ;
        RECT 20.550 210.580 22.945 210.880 ;
        RECT 17.790 209.580 21.445 209.880 ;
        RECT 15.030 208.580 19.945 208.880 ;
        RECT 19.645 203.185 19.945 208.580 ;
        RECT 21.145 203.185 21.445 209.580 ;
        RECT 22.645 203.185 22.945 210.580 ;
        RECT 24.145 203.185 24.445 211.580 ;
        RECT 25.645 211.580 26.370 211.880 ;
        RECT 25.645 203.185 25.945 211.580 ;
        RECT 28.830 210.880 29.130 224.750 ;
        RECT 27.145 210.580 29.130 210.880 ;
        RECT 27.145 203.185 27.445 210.580 ;
        RECT 31.590 209.880 31.890 224.750 ;
        RECT 28.645 209.580 31.890 209.880 ;
        RECT 28.645 203.185 28.945 209.580 ;
        RECT 34.350 208.880 34.650 224.750 ;
        RECT 30.145 208.580 34.650 208.880 ;
        RECT 37.110 208.880 37.410 224.750 ;
        RECT 39.870 209.880 40.170 224.750 ;
        RECT 42.630 210.880 42.930 224.750 ;
        RECT 45.390 211.880 45.690 224.750 ;
        RECT 48.150 211.880 48.450 224.750 ;
        RECT 45.390 211.580 46.525 211.880 ;
        RECT 42.630 210.580 45.025 210.880 ;
        RECT 39.870 209.580 43.525 209.880 ;
        RECT 37.110 208.580 42.025 208.880 ;
        RECT 30.145 203.185 30.445 208.580 ;
        RECT 41.725 203.185 42.025 208.580 ;
        RECT 43.225 203.185 43.525 209.580 ;
        RECT 44.725 203.185 45.025 210.580 ;
        RECT 46.225 203.185 46.525 211.580 ;
        RECT 47.725 211.580 48.450 211.880 ;
        RECT 47.725 203.185 48.025 211.580 ;
        RECT 50.910 210.880 51.210 224.750 ;
        RECT 49.225 210.580 51.210 210.880 ;
        RECT 49.225 203.185 49.525 210.580 ;
        RECT 53.670 209.880 53.970 224.750 ;
        RECT 50.725 209.580 53.970 209.880 ;
        RECT 50.725 203.185 51.025 209.580 ;
        RECT 56.430 208.880 56.730 224.750 ;
        RECT 52.225 208.580 56.730 208.880 ;
        RECT 59.190 208.880 59.490 224.750 ;
        RECT 61.950 209.880 62.250 224.750 ;
        RECT 64.710 210.880 65.010 224.750 ;
        RECT 67.470 211.880 67.770 224.750 ;
        RECT 70.230 211.880 70.530 224.750 ;
        RECT 67.470 211.580 68.605 211.880 ;
        RECT 64.710 210.580 67.105 210.880 ;
        RECT 61.950 209.580 65.605 209.880 ;
        RECT 59.190 208.580 64.105 208.880 ;
        RECT 52.225 203.185 52.525 208.580 ;
        RECT 63.805 203.185 64.105 208.580 ;
        RECT 65.305 203.185 65.605 209.580 ;
        RECT 66.805 203.185 67.105 210.580 ;
        RECT 68.305 203.185 68.605 211.580 ;
        RECT 69.805 211.580 70.530 211.880 ;
        RECT 69.805 203.185 70.105 211.580 ;
        RECT 72.990 210.880 73.290 224.750 ;
        RECT 71.305 210.580 73.290 210.880 ;
        RECT 71.305 203.185 71.605 210.580 ;
        RECT 75.750 209.880 76.050 224.750 ;
        RECT 72.805 209.580 76.050 209.880 ;
        RECT 72.805 203.185 73.105 209.580 ;
        RECT 19.630 202.855 19.960 203.185 ;
        RECT 21.130 202.855 21.460 203.185 ;
        RECT 22.630 202.855 22.960 203.185 ;
        RECT 24.130 202.855 24.460 203.185 ;
        RECT 25.630 202.855 25.960 203.185 ;
        RECT 27.130 202.855 27.460 203.185 ;
        RECT 28.630 202.855 28.960 203.185 ;
        RECT 30.130 202.855 30.460 203.185 ;
        RECT 41.710 202.855 42.040 203.185 ;
        RECT 43.210 202.855 43.540 203.185 ;
        RECT 44.710 202.855 45.040 203.185 ;
        RECT 46.210 202.855 46.540 203.185 ;
        RECT 47.710 202.855 48.040 203.185 ;
        RECT 49.210 202.855 49.540 203.185 ;
        RECT 50.710 202.855 51.040 203.185 ;
        RECT 52.210 202.855 52.540 203.185 ;
        RECT 63.790 202.855 64.120 203.185 ;
        RECT 65.290 202.855 65.620 203.185 ;
        RECT 66.790 202.855 67.120 203.185 ;
        RECT 68.290 202.855 68.620 203.185 ;
        RECT 69.790 202.855 70.120 203.185 ;
        RECT 71.290 202.855 71.620 203.185 ;
        RECT 72.790 202.855 73.120 203.185 ;
        RECT 2.470 199.420 75.240 200.420 ;
        RECT 5.470 197.420 76.490 198.420 ;
        RECT 78.510 187.520 78.810 224.750 ;
        RECT 119.910 220.310 120.210 224.760 ;
        RECT 122.630 224.750 123.010 225.070 ;
        RECT 122.670 223.070 122.970 224.750 ;
        RECT 122.670 222.750 142.500 223.070 ;
        RECT 119.910 219.990 139.500 220.310 ;
        RECT 132.295 187.520 133.295 187.535 ;
        RECT 78.510 186.520 133.295 187.520 ;
        RECT 132.295 182.535 133.295 186.520 ;
        RECT 132.270 178.485 136.320 182.535 ;
        RECT 20.270 168.535 20.850 169.085 ;
        RECT 22.045 161.060 37.445 177.920 ;
        RECT 38.645 161.060 54.045 177.920 ;
        RECT 55.245 161.060 70.645 177.920 ;
        RECT 71.845 161.060 87.245 177.920 ;
        RECT 88.445 161.060 103.845 177.920 ;
        RECT 105.045 161.060 120.445 177.920 ;
        RECT 121.240 177.435 121.820 177.985 ;
        RECT 19.470 150.135 20.550 151.185 ;
        RECT 22.045 142.910 37.445 159.770 ;
        RECT 38.645 142.910 54.045 159.770 ;
        RECT 55.245 142.910 70.645 159.770 ;
        RECT 71.845 142.910 87.245 159.770 ;
        RECT 88.445 142.910 103.845 159.770 ;
        RECT 105.045 142.910 120.445 159.770 ;
        RECT 122.240 158.985 123.320 160.035 ;
        RECT 16.490 132.985 20.570 134.485 ;
        RECT 16.490 131.935 20.600 132.985 ;
        RECT 16.490 130.435 20.570 131.935 ;
        RECT 22.045 124.760 37.445 141.620 ;
        RECT 38.645 124.760 54.045 141.620 ;
        RECT 55.245 124.760 70.645 141.620 ;
        RECT 71.845 124.760 87.245 141.620 ;
        RECT 88.445 124.760 103.845 141.620 ;
        RECT 105.045 124.760 120.445 141.620 ;
        RECT 121.590 134.235 125.670 138.285 ;
        RECT 121.620 126.935 122.670 128.015 ;
        RECT 123.870 126.260 126.270 130.120 ;
        RECT 16.620 112.385 20.700 116.435 ;
        RECT 22.045 106.660 37.445 123.520 ;
        RECT 38.645 106.660 54.045 123.520 ;
        RECT 55.245 106.660 70.645 123.520 ;
        RECT 71.845 106.660 87.245 123.520 ;
        RECT 88.445 106.660 103.845 123.520 ;
        RECT 105.045 106.660 120.445 123.520 ;
        RECT 121.645 119.735 125.725 123.785 ;
        RECT 22.045 88.510 37.445 105.370 ;
        RECT 38.645 88.510 54.045 105.370 ;
        RECT 55.245 88.510 70.645 105.370 ;
        RECT 71.845 88.510 87.245 105.370 ;
        RECT 88.445 88.510 103.845 105.370 ;
        RECT 105.045 88.510 120.445 105.370 ;
        RECT 121.645 104.585 122.725 105.635 ;
        RECT 121.645 95.685 122.725 96.735 ;
        RECT 22.045 70.360 37.445 87.220 ;
        RECT 38.645 70.360 54.045 87.220 ;
        RECT 55.245 70.360 70.645 87.220 ;
        RECT 71.845 70.360 87.245 87.220 ;
        RECT 88.445 70.360 103.845 87.220 ;
        RECT 105.045 70.360 120.445 87.220 ;
        RECT 121.645 86.435 122.725 87.485 ;
        RECT 121.645 83.035 123.350 85.085 ;
        RECT 121.650 81.185 122.730 82.235 ;
        RECT 124.550 80.460 126.950 84.320 ;
        RECT 121.645 77.535 122.725 78.585 ;
        RECT 55.960 68.610 60.010 68.635 ;
        RECT 38.045 64.610 60.010 68.610 ;
        RECT 55.960 64.585 60.010 64.610 ;
        RECT 75.090 68.610 79.140 68.635 ;
        RECT 75.090 64.610 111.995 68.610 ;
        RECT 75.090 64.585 79.140 64.610 ;
        RECT 121.615 63.950 123.695 63.985 ;
        RECT 16.690 45.335 20.820 46.785 ;
        RECT 22.015 46.310 37.415 63.170 ;
        RECT 38.615 46.310 54.015 63.170 ;
        RECT 55.215 46.310 70.615 63.170 ;
        RECT 71.815 46.310 87.215 63.170 ;
        RECT 88.415 46.310 103.815 63.170 ;
        RECT 105.015 46.310 120.415 63.170 ;
        RECT 121.615 61.935 123.730 63.950 ;
        RECT 121.620 61.870 123.730 61.935 ;
        RECT 121.615 55.085 123.725 55.150 ;
        RECT 121.615 53.070 123.760 55.085 ;
        RECT 121.680 53.035 123.760 53.070 ;
        RECT 16.690 45.310 21.060 45.335 ;
        RECT 16.690 44.310 21.065 45.310 ;
        RECT 16.690 44.285 21.060 44.310 ;
        RECT 16.690 42.735 20.820 44.285 ;
        RECT 16.740 38.035 20.790 38.085 ;
        RECT 16.640 36.535 20.790 38.035 ;
        RECT 16.640 35.485 20.805 36.535 ;
        RECT 11.020 31.355 15.100 35.405 ;
        RECT 16.640 34.035 20.790 35.485 ;
        RECT 16.640 33.985 20.720 34.035 ;
        RECT 16.640 33.935 20.690 33.985 ;
        RECT 14.075 1.000 15.075 31.355 ;
        RECT 22.015 28.210 37.415 45.070 ;
        RECT 38.615 28.210 54.015 45.070 ;
        RECT 55.215 28.210 70.615 45.070 ;
        RECT 71.815 28.210 87.215 45.070 ;
        RECT 88.415 28.210 103.815 45.070 ;
        RECT 105.015 28.210 120.415 45.070 ;
        RECT 105.410 20.375 107.490 20.400 ;
        RECT 81.260 18.430 85.310 18.455 ;
        RECT 26.310 10.405 30.360 14.455 ;
        RECT 54.845 14.430 85.310 18.430 ;
        RECT 105.410 18.345 113.310 20.375 ;
        RECT 105.410 18.320 107.490 18.345 ;
        RECT 91.290 15.710 92.340 15.735 ;
        RECT 91.290 14.710 109.845 15.710 ;
        RECT 91.290 14.685 92.340 14.710 ;
        RECT 26.335 9.060 30.335 10.405 ;
        RECT 26.335 5.060 30.340 9.060 ;
        RECT 54.845 9.055 58.845 14.430 ;
        RECT 81.260 14.405 85.310 14.430 ;
        RECT 93.240 11.460 94.290 11.485 ;
        RECT 93.240 10.460 109.845 11.460 ;
        RECT 93.240 10.435 94.290 10.460 ;
        RECT 54.820 5.065 58.870 9.055 ;
        RECT 54.845 5.060 58.845 5.065 ;
        RECT 26.345 5.035 30.335 5.060 ;
        RECT 84.170 5.035 88.220 9.085 ;
        RECT 99.120 5.035 103.170 9.085 ;
        RECT 111.280 9.060 113.310 18.345 ;
        RECT 117.290 18.335 119.340 20.385 ;
        RECT 132.345 20.010 136.345 21.510 ;
        RECT 138.500 20.010 139.500 219.990 ;
        RECT 120.945 19.010 139.500 20.010 ;
        RECT 117.315 9.060 119.315 18.335 ;
        RECT 120.945 15.735 121.945 19.010 ;
        RECT 132.345 17.510 136.345 19.010 ;
        RECT 120.920 14.685 121.970 15.735 ;
        RECT 120.970 11.460 122.020 11.485 ;
        RECT 132.345 11.460 136.345 12.960 ;
        RECT 141.500 11.460 142.500 222.750 ;
        RECT 120.970 10.460 142.500 11.460 ;
        RECT 120.970 10.435 122.020 10.460 ;
        RECT 110.295 9.055 114.315 9.060 ;
        RECT 116.295 9.055 120.295 9.060 ;
        RECT 110.290 5.065 114.340 9.055 ;
        RECT 116.270 5.065 120.320 9.055 ;
        RECT 110.295 5.060 114.315 5.065 ;
        RECT 116.295 5.060 120.295 5.065 ;
        RECT 87.195 3.500 88.195 5.035 ;
        RECT 102.145 3.500 103.145 5.035 ;
        RECT 122.575 5.025 126.685 9.075 ;
        RECT 132.345 8.960 136.345 10.460 ;
        RECT 122.595 5.010 126.675 5.025 ;
        RECT 122.625 5.005 126.675 5.010 ;
        RECT 122.650 5.000 126.650 5.005 ;
        RECT 87.195 2.500 100.645 3.500 ;
        RECT 102.145 2.500 137.120 3.500 ;
        RECT 97.535 1.000 98.425 1.025 ;
        RECT 99.645 1.000 100.645 2.500 ;
        RECT 116.855 1.000 117.745 1.025 ;
        RECT 14.075 0.000 98.430 1.000 ;
        RECT 99.645 0.000 117.750 1.000 ;
        RECT 136.120 0.000 137.120 2.500 ;
      LAYER met4 ;
        RECT 15.015 224.760 15.030 225.075 ;
        RECT 15.330 224.760 15.345 225.075 ;
        RECT 15.015 224.745 15.345 224.760 ;
        RECT 17.775 224.760 17.790 225.075 ;
        RECT 18.090 224.760 18.105 225.075 ;
        RECT 17.775 224.745 18.105 224.760 ;
        RECT 20.535 224.760 20.550 225.075 ;
        RECT 20.850 224.760 20.865 225.075 ;
        RECT 20.535 224.745 20.865 224.760 ;
        RECT 23.295 224.760 23.310 225.075 ;
        RECT 23.610 224.760 23.625 225.075 ;
        RECT 23.295 224.745 23.625 224.760 ;
        RECT 26.055 224.760 26.070 225.075 ;
        RECT 26.370 224.760 26.385 225.075 ;
        RECT 26.055 224.745 26.385 224.760 ;
        RECT 28.815 224.760 28.830 225.075 ;
        RECT 29.130 224.760 29.145 225.075 ;
        RECT 28.815 224.745 29.145 224.760 ;
        RECT 31.575 224.760 31.590 225.075 ;
        RECT 31.890 224.760 31.905 225.075 ;
        RECT 31.575 224.745 31.905 224.760 ;
        RECT 34.335 224.760 34.350 225.075 ;
        RECT 34.650 224.760 34.665 225.075 ;
        RECT 34.335 224.745 34.665 224.760 ;
        RECT 37.095 224.760 37.110 225.075 ;
        RECT 37.410 224.760 37.425 225.075 ;
        RECT 37.095 224.745 37.425 224.760 ;
        RECT 39.855 224.760 39.870 225.075 ;
        RECT 40.170 224.760 40.185 225.075 ;
        RECT 39.855 224.745 40.185 224.760 ;
        RECT 42.615 224.760 42.630 225.075 ;
        RECT 42.930 224.760 42.945 225.075 ;
        RECT 42.615 224.745 42.945 224.760 ;
        RECT 45.375 224.760 45.390 225.075 ;
        RECT 45.690 224.760 45.705 225.075 ;
        RECT 45.375 224.745 45.705 224.760 ;
        RECT 48.135 224.760 48.150 225.075 ;
        RECT 48.450 224.760 48.465 225.075 ;
        RECT 48.135 224.745 48.465 224.760 ;
        RECT 50.895 224.760 50.910 225.075 ;
        RECT 51.210 224.760 51.225 225.075 ;
        RECT 50.895 224.745 51.225 224.760 ;
        RECT 53.655 224.760 53.670 225.075 ;
        RECT 53.970 224.760 53.985 225.075 ;
        RECT 53.655 224.745 53.985 224.760 ;
        RECT 56.415 224.760 56.430 225.075 ;
        RECT 56.730 224.760 56.745 225.075 ;
        RECT 56.415 224.745 56.745 224.760 ;
        RECT 59.175 224.760 59.190 225.075 ;
        RECT 59.490 224.760 59.505 225.075 ;
        RECT 59.175 224.745 59.505 224.760 ;
        RECT 61.935 224.760 61.950 225.075 ;
        RECT 62.250 224.760 62.265 225.075 ;
        RECT 61.935 224.745 62.265 224.760 ;
        RECT 64.695 224.760 64.710 225.075 ;
        RECT 65.010 224.760 65.025 225.075 ;
        RECT 64.695 224.745 65.025 224.760 ;
        RECT 67.455 224.760 67.470 225.075 ;
        RECT 67.770 224.760 67.785 225.075 ;
        RECT 67.455 224.745 67.785 224.760 ;
        RECT 70.215 224.760 70.230 225.075 ;
        RECT 70.530 224.760 70.545 225.075 ;
        RECT 70.215 224.745 70.545 224.760 ;
        RECT 72.975 224.760 72.990 225.075 ;
        RECT 73.290 224.760 73.305 225.075 ;
        RECT 72.975 224.745 73.305 224.760 ;
        RECT 75.735 224.760 75.750 225.075 ;
        RECT 76.050 224.760 76.065 225.075 ;
        RECT 75.735 224.745 76.065 224.760 ;
        RECT 78.495 224.760 78.510 225.075 ;
        RECT 78.810 224.760 78.825 225.075 ;
        RECT 78.495 224.745 78.825 224.760 ;
        RECT 119.895 224.760 119.910 225.085 ;
        RECT 120.210 224.760 120.225 225.085 ;
        RECT 119.895 224.755 120.225 224.760 ;
        RECT 122.655 224.760 122.670 225.075 ;
        RECT 122.970 224.760 122.985 225.075 ;
        RECT 122.655 224.745 122.985 224.760 ;
        RECT 21.445 177.410 121.820 178.010 ;
        RECT 21.445 177.400 121.045 177.410 ;
        RECT 22.440 169.110 37.050 176.065 ;
        RECT 39.040 169.110 53.650 176.065 ;
        RECT 55.640 169.110 70.250 176.065 ;
        RECT 72.240 169.110 86.850 176.065 ;
        RECT 88.840 169.110 103.450 176.065 ;
        RECT 105.440 169.110 120.050 176.065 ;
        RECT 20.270 168.510 121.045 169.110 ;
        RECT 21.445 168.500 121.045 168.510 ;
        RECT 22.440 161.455 37.050 168.500 ;
        RECT 39.040 161.455 53.650 168.500 ;
        RECT 55.640 161.455 70.250 168.500 ;
        RECT 72.240 161.455 86.850 168.500 ;
        RECT 88.840 161.455 103.450 168.500 ;
        RECT 105.440 161.455 120.050 168.500 ;
        RECT 122.265 160.010 123.275 160.040 ;
        RECT 21.445 159.010 123.275 160.010 ;
        RECT 122.265 158.980 123.275 159.010 ;
        RECT 19.515 151.160 20.525 151.190 ;
        RECT 22.440 151.160 37.050 157.915 ;
        RECT 39.040 151.160 53.650 157.915 ;
        RECT 55.640 151.160 70.250 157.915 ;
        RECT 72.240 151.160 86.850 157.915 ;
        RECT 88.840 151.160 103.450 157.915 ;
        RECT 105.440 151.160 120.050 157.915 ;
        RECT 19.515 150.160 121.045 151.160 ;
        RECT 19.515 150.130 20.525 150.160 ;
        RECT 22.440 143.305 37.050 150.160 ;
        RECT 39.040 143.305 53.650 150.160 ;
        RECT 55.640 143.305 70.250 150.160 ;
        RECT 72.240 143.305 86.850 150.160 ;
        RECT 88.840 143.305 103.450 150.160 ;
        RECT 105.440 143.305 120.050 150.160 ;
        RECT 21.445 140.835 122.645 141.835 ;
        RECT 16.515 132.990 20.525 134.490 ;
        RECT 16.515 132.960 20.575 132.990 ;
        RECT 22.440 132.960 37.050 139.765 ;
        RECT 39.040 132.960 53.650 139.765 ;
        RECT 55.640 132.960 70.250 139.765 ;
        RECT 72.240 132.960 86.850 139.765 ;
        RECT 88.840 132.960 103.450 139.765 ;
        RECT 105.440 132.960 120.050 139.765 ;
        RECT 121.645 138.290 122.645 140.835 ;
        RECT 121.615 134.230 125.625 138.290 ;
        RECT 16.515 131.960 121.045 132.960 ;
        RECT 16.515 131.930 20.575 131.960 ;
        RECT 16.515 130.430 20.525 131.930 ;
        RECT 22.440 125.155 37.050 131.960 ;
        RECT 39.040 125.155 53.650 131.960 ;
        RECT 55.640 125.155 70.250 131.960 ;
        RECT 72.240 125.155 86.850 131.960 ;
        RECT 88.840 125.155 103.450 131.960 ;
        RECT 105.440 125.155 120.050 131.960 ;
        RECT 124.570 130.360 125.570 134.230 ;
        RECT 123.920 129.360 126.220 130.360 ;
        RECT 121.615 127.985 122.675 127.990 ;
        RECT 121.615 127.960 122.695 127.985 ;
        RECT 124.265 127.960 125.875 128.265 ;
        RECT 121.615 126.980 125.875 127.960 ;
        RECT 121.645 126.960 125.875 126.980 ;
        RECT 124.265 126.655 125.875 126.960 ;
        RECT 121.670 123.760 125.680 123.790 ;
        RECT 21.445 122.760 125.680 123.760 ;
        RECT 16.665 114.875 20.675 116.440 ;
        RECT 22.440 114.875 37.050 121.665 ;
        RECT 39.040 114.875 53.650 121.665 ;
        RECT 55.640 114.875 70.250 121.665 ;
        RECT 72.240 114.875 86.850 121.665 ;
        RECT 88.840 114.875 103.450 121.665 ;
        RECT 105.440 114.875 120.050 121.665 ;
        RECT 121.670 119.730 125.680 122.760 ;
        RECT 16.665 113.875 121.045 114.875 ;
        RECT 16.665 112.380 20.675 113.875 ;
        RECT 22.440 107.055 37.050 113.875 ;
        RECT 39.040 107.055 53.650 113.875 ;
        RECT 55.640 107.055 70.250 113.875 ;
        RECT 72.240 107.055 86.850 113.875 ;
        RECT 88.840 107.055 103.450 113.875 ;
        RECT 105.440 107.055 120.050 113.875 ;
        RECT 121.670 105.610 122.680 105.640 ;
        RECT 21.445 104.610 122.680 105.610 ;
        RECT 121.670 104.580 122.680 104.610 ;
        RECT 22.440 96.710 37.050 103.515 ;
        RECT 39.040 96.710 53.650 103.515 ;
        RECT 55.640 96.710 70.250 103.515 ;
        RECT 72.240 96.710 86.850 103.515 ;
        RECT 88.840 96.710 103.450 103.515 ;
        RECT 105.440 96.710 120.050 103.515 ;
        RECT 121.670 96.710 122.680 96.740 ;
        RECT 21.445 95.710 122.680 96.710 ;
        RECT 22.440 88.905 37.050 95.710 ;
        RECT 39.040 88.905 53.650 95.710 ;
        RECT 55.640 88.905 70.250 95.710 ;
        RECT 72.240 88.905 86.850 95.710 ;
        RECT 88.840 88.905 103.450 95.710 ;
        RECT 105.440 88.905 120.050 95.710 ;
        RECT 121.670 95.680 122.680 95.710 ;
        RECT 21.440 87.460 119.850 87.470 ;
        RECT 121.670 87.460 122.680 87.490 ;
        RECT 21.440 86.460 122.680 87.460 ;
        RECT 21.440 86.455 119.850 86.460 ;
        RECT 121.670 86.430 122.680 86.460 ;
        RECT 22.440 78.560 37.050 85.365 ;
        RECT 39.040 78.560 53.650 85.365 ;
        RECT 55.640 78.560 70.250 85.365 ;
        RECT 72.240 78.560 86.850 85.365 ;
        RECT 88.840 78.560 103.450 85.365 ;
        RECT 105.440 78.560 120.050 85.365 ;
        RECT 121.670 85.060 123.325 85.090 ;
        RECT 121.670 83.060 126.900 85.060 ;
        RECT 121.670 83.030 123.325 83.060 ;
        RECT 121.695 82.210 122.705 82.240 ;
        RECT 124.945 82.210 126.555 82.465 ;
        RECT 121.695 81.210 126.555 82.210 ;
        RECT 121.695 81.180 122.705 81.210 ;
        RECT 124.945 80.855 126.555 81.210 ;
        RECT 121.670 78.560 122.680 78.590 ;
        RECT 21.445 77.560 122.680 78.560 ;
        RECT 22.440 70.755 37.050 77.560 ;
        RECT 39.040 70.755 53.650 77.560 ;
        RECT 55.640 70.755 70.250 77.560 ;
        RECT 72.240 70.755 86.850 77.560 ;
        RECT 88.840 70.755 103.450 77.560 ;
        RECT 105.440 70.755 120.050 77.560 ;
        RECT 121.670 77.530 122.680 77.560 ;
        RECT 121.640 63.955 123.650 63.990 ;
        RECT 121.640 63.410 123.685 63.955 ;
        RECT 21.415 62.410 123.685 63.410 ;
        RECT 121.640 61.930 123.685 62.410 ;
        RECT 121.645 61.865 123.685 61.930 ;
        RECT 22.410 54.535 37.020 61.315 ;
        RECT 39.010 54.535 53.620 61.315 ;
        RECT 55.610 54.535 70.220 61.315 ;
        RECT 72.210 54.535 86.820 61.315 ;
        RECT 88.810 54.535 103.420 61.315 ;
        RECT 105.410 54.535 120.020 61.315 ;
        RECT 121.640 55.090 123.680 55.155 ;
        RECT 121.640 55.065 123.715 55.090 ;
        RECT 121.640 54.535 123.740 55.065 ;
        RECT 21.415 53.535 123.740 54.535 ;
        RECT 16.735 45.310 20.795 46.790 ;
        RECT 22.410 46.705 37.020 53.535 ;
        RECT 39.010 46.705 53.620 53.535 ;
        RECT 55.610 46.705 70.220 53.535 ;
        RECT 72.210 46.705 86.820 53.535 ;
        RECT 88.810 46.705 103.420 53.535 ;
        RECT 105.410 46.705 120.020 53.535 ;
        RECT 121.640 53.065 123.740 53.535 ;
        RECT 121.705 53.055 123.740 53.065 ;
        RECT 121.705 53.030 123.715 53.055 ;
        RECT 16.735 44.310 121.165 45.310 ;
        RECT 16.735 42.730 20.795 44.310 ;
        RECT 16.685 36.560 20.695 38.040 ;
        RECT 16.685 36.510 20.815 36.560 ;
        RECT 22.410 36.510 37.020 43.215 ;
        RECT 39.010 36.510 53.620 43.215 ;
        RECT 55.610 36.510 70.220 43.215 ;
        RECT 72.210 36.510 86.820 43.215 ;
        RECT 88.810 36.510 103.420 43.215 ;
        RECT 105.410 36.510 120.020 43.215 ;
        RECT 16.685 35.510 121.115 36.510 ;
        RECT 16.685 35.460 20.815 35.510 ;
        RECT 16.685 33.980 20.695 35.460 ;
        RECT 22.410 28.605 37.020 35.510 ;
        RECT 39.010 28.605 53.620 35.510 ;
        RECT 55.610 28.605 70.220 35.510 ;
        RECT 72.210 28.605 86.820 35.510 ;
        RECT 88.810 28.605 103.420 35.510 ;
        RECT 105.410 28.605 120.020 35.510 ;
        RECT 26.340 7.000 30.340 9.060 ;
        RECT 10.000 5.000 30.340 7.000 ;
        RECT 5.000 4.000 7.000 5.000 ;
        RECT 54.845 4.000 58.845 9.060 ;
        RECT 5.000 2.000 58.845 4.000 ;
        RECT 110.315 4.000 114.315 9.060 ;
        RECT 116.295 7.000 120.295 9.060 ;
        RECT 122.650 7.000 126.650 9.000 ;
        RECT 116.295 5.000 138.000 7.000 ;
        RECT 141.000 4.000 143.000 5.000 ;
        RECT 110.315 2.000 143.000 4.000 ;
  END
END tt_um_htfab_hsxo
END LIBRARY

